VERSION 5.8 ;
BUSBITCHARS "[]" ;
DIVIDERCHAR "/" ;
UNITS
    DATABASE MICRONS 1000 ;
END UNITS

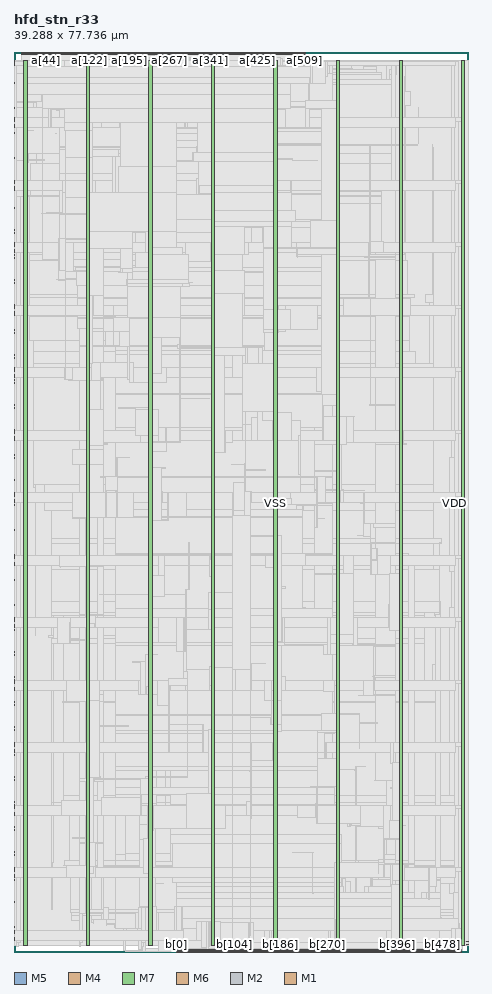
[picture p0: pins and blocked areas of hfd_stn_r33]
MACRO hfd_stn_r33
  FOREIGN hfd_stn_r33 0 0 ;
  CLASS BLOCK ;
  SIZE 39.288 BY 77.736 ;
  PIN a[0]
    DIRECTION INPUT ;
    USE SIGNAL ;
    PORT
      LAYER M5 ;
        RECT  0.624 77.544 0.648 77.736 ;
    END
  END a[0]
  PIN a[100]
    DIRECTION INPUT ;
    USE SIGNAL ;
    PORT
      LAYER M5 ;
        RECT  5.424 77.544 5.448 77.736 ;
    END
  END a[100]
  PIN a[101]
    DIRECTION INPUT ;
    USE SIGNAL ;
    PORT
      LAYER M5 ;
        RECT  5.472 77.544 5.496 77.736 ;
    END
  END a[101]
  PIN a[102]
    DIRECTION INPUT ;
    USE SIGNAL ;
    PORT
      LAYER M5 ;
        RECT  5.52 77.544 5.544 77.736 ;
    END
  END a[102]
  PIN a[103]
    DIRECTION INPUT ;
    USE SIGNAL ;
    PORT
      LAYER M5 ;
        RECT  5.568 77.544 5.592 77.736 ;
    END
  END a[103]
  PIN a[104]
    DIRECTION INPUT ;
    USE SIGNAL ;
    PORT
      LAYER M5 ;
        RECT  5.616 77.544 5.64 77.736 ;
    END
  END a[104]
  PIN a[105]
    DIRECTION INPUT ;
    USE SIGNAL ;
    PORT
      LAYER M5 ;
        RECT  5.664 77.544 5.688 77.736 ;
    END
  END a[105]
  PIN a[106]
    DIRECTION INPUT ;
    USE SIGNAL ;
    PORT
      LAYER M5 ;
        RECT  5.712 77.544 5.736 77.736 ;
    END
  END a[106]
  PIN a[107]
    DIRECTION INPUT ;
    USE SIGNAL ;
    PORT
      LAYER M5 ;
        RECT  5.76 77.544 5.784 77.736 ;
    END
  END a[107]
  PIN a[108]
    DIRECTION INPUT ;
    USE SIGNAL ;
    PORT
      LAYER M5 ;
        RECT  5.808 77.544 5.832 77.736 ;
    END
  END a[108]
  PIN a[109]
    DIRECTION INPUT ;
    USE SIGNAL ;
    PORT
      LAYER M5 ;
        RECT  5.856 77.544 5.88 77.736 ;
    END
  END a[109]
  PIN a[10]
    DIRECTION INPUT ;
    USE SIGNAL ;
    PORT
      LAYER M5 ;
        RECT  1.104 77.544 1.128 77.736 ;
    END
  END a[10]
  PIN a[110]
    DIRECTION INPUT ;
    USE SIGNAL ;
    PORT
      LAYER M5 ;
        RECT  5.904 77.544 5.928 77.736 ;
    END
  END a[110]
  PIN a[111]
    DIRECTION INPUT ;
    USE SIGNAL ;
    PORT
      LAYER M5 ;
        RECT  5.952 77.544 5.976 77.736 ;
    END
  END a[111]
  PIN a[112]
    DIRECTION INPUT ;
    USE SIGNAL ;
    PORT
      LAYER M5 ;
        RECT  6 77.544 6.024 77.736 ;
    END
  END a[112]
  PIN a[113]
    DIRECTION INPUT ;
    USE SIGNAL ;
    PORT
      LAYER M5 ;
        RECT  6.048 77.544 6.072 77.736 ;
    END
  END a[113]
  PIN a[114]
    DIRECTION INPUT ;
    USE SIGNAL ;
    PORT
      LAYER M5 ;
        RECT  6.096 77.544 6.12 77.736 ;
    END
  END a[114]
  PIN a[115]
    DIRECTION INPUT ;
    USE SIGNAL ;
    PORT
      LAYER M5 ;
        RECT  6.144 77.544 6.168 77.736 ;
    END
  END a[115]
  PIN a[116]
    DIRECTION INPUT ;
    USE SIGNAL ;
    PORT
      LAYER M5 ;
        RECT  6.192 77.544 6.216 77.736 ;
    END
  END a[116]
  PIN a[117]
    DIRECTION INPUT ;
    USE SIGNAL ;
    PORT
      LAYER M5 ;
        RECT  6.24 77.544 6.264 77.736 ;
    END
  END a[117]
  PIN a[118]
    DIRECTION INPUT ;
    USE SIGNAL ;
    PORT
      LAYER M5 ;
        RECT  6.288 77.544 6.312 77.736 ;
    END
  END a[118]
  PIN a[119]
    DIRECTION INPUT ;
    USE SIGNAL ;
    PORT
      LAYER M5 ;
        RECT  6.336 77.544 6.36 77.736 ;
    END
  END a[119]
  PIN a[11]
    DIRECTION INPUT ;
    USE SIGNAL ;
    PORT
      LAYER M5 ;
        RECT  1.152 77.544 1.176 77.736 ;
    END
  END a[11]
  PIN a[120]
    DIRECTION INPUT ;
    USE SIGNAL ;
    PORT
      LAYER M5 ;
        RECT  6.384 77.544 6.408 77.736 ;
    END
  END a[120]
  PIN a[121]
    DIRECTION INPUT ;
    USE SIGNAL ;
    PORT
      LAYER M5 ;
        RECT  6.432 77.544 6.456 77.736 ;
    END
  END a[121]
  PIN a[122]
    DIRECTION INPUT ;
    USE SIGNAL ;
    PORT
      LAYER M5 ;
        RECT  6.48 77.544 6.504 77.736 ;
    END
  END a[122]
  PIN a[123]
    DIRECTION INPUT ;
    USE SIGNAL ;
    PORT
      LAYER M5 ;
        RECT  6.528 77.544 6.552 77.736 ;
    END
  END a[123]
  PIN a[124]
    DIRECTION INPUT ;
    USE SIGNAL ;
    PORT
      LAYER M5 ;
        RECT  6.576 77.544 6.6 77.736 ;
    END
  END a[124]
  PIN a[125]
    DIRECTION INPUT ;
    USE SIGNAL ;
    PORT
      LAYER M5 ;
        RECT  6.624 77.544 6.648 77.736 ;
    END
  END a[125]
  PIN a[126]
    DIRECTION INPUT ;
    USE SIGNAL ;
    PORT
      LAYER M5 ;
        RECT  6.672 77.544 6.696 77.736 ;
    END
  END a[126]
  PIN a[127]
    DIRECTION INPUT ;
    USE SIGNAL ;
    PORT
      LAYER M5 ;
        RECT  6.72 77.544 6.744 77.736 ;
    END
  END a[127]
  PIN a[128]
    DIRECTION INPUT ;
    USE SIGNAL ;
    PORT
      LAYER M5 ;
        RECT  6.768 77.544 6.792 77.736 ;
    END
  END a[128]
  PIN a[129]
    DIRECTION INPUT ;
    USE SIGNAL ;
    PORT
      LAYER M5 ;
        RECT  6.816 77.544 6.84 77.736 ;
    END
  END a[129]
  PIN a[12]
    DIRECTION INPUT ;
    USE SIGNAL ;
    PORT
      LAYER M5 ;
        RECT  1.2 77.544 1.224 77.736 ;
    END
  END a[12]
  PIN a[130]
    DIRECTION INPUT ;
    USE SIGNAL ;
    PORT
      LAYER M5 ;
        RECT  6.864 77.544 6.888 77.736 ;
    END
  END a[130]
  PIN a[131]
    DIRECTION INPUT ;
    USE SIGNAL ;
    PORT
      LAYER M5 ;
        RECT  6.912 77.544 6.936 77.736 ;
    END
  END a[131]
  PIN a[132]
    DIRECTION INPUT ;
    USE SIGNAL ;
    PORT
      LAYER M5 ;
        RECT  6.96 77.544 6.984 77.736 ;
    END
  END a[132]
  PIN a[133]
    DIRECTION INPUT ;
    USE SIGNAL ;
    PORT
      LAYER M5 ;
        RECT  7.008 77.544 7.032 77.736 ;
    END
  END a[133]
  PIN a[134]
    DIRECTION INPUT ;
    USE SIGNAL ;
    PORT
      LAYER M5 ;
        RECT  7.056 77.544 7.08 77.736 ;
    END
  END a[134]
  PIN a[135]
    DIRECTION INPUT ;
    USE SIGNAL ;
    PORT
      LAYER M5 ;
        RECT  7.104 77.544 7.128 77.736 ;
    END
  END a[135]
  PIN a[136]
    DIRECTION INPUT ;
    USE SIGNAL ;
    PORT
      LAYER M5 ;
        RECT  7.152 77.544 7.176 77.736 ;
    END
  END a[136]
  PIN a[137]
    DIRECTION INPUT ;
    USE SIGNAL ;
    PORT
      LAYER M5 ;
        RECT  7.2 77.544 7.224 77.736 ;
    END
  END a[137]
  PIN a[138]
    DIRECTION INPUT ;
    USE SIGNAL ;
    PORT
      LAYER M5 ;
        RECT  7.248 77.544 7.272 77.736 ;
    END
  END a[138]
  PIN a[139]
    DIRECTION INPUT ;
    USE SIGNAL ;
    PORT
      LAYER M5 ;
        RECT  7.296 77.544 7.32 77.736 ;
    END
  END a[139]
  PIN a[13]
    DIRECTION INPUT ;
    USE SIGNAL ;
    PORT
      LAYER M5 ;
        RECT  1.248 77.544 1.272 77.736 ;
    END
  END a[13]
  PIN a[140]
    DIRECTION INPUT ;
    USE SIGNAL ;
    PORT
      LAYER M5 ;
        RECT  7.344 77.544 7.368 77.736 ;
    END
  END a[140]
  PIN a[141]
    DIRECTION INPUT ;
    USE SIGNAL ;
    PORT
      LAYER M5 ;
        RECT  7.392 77.544 7.416 77.736 ;
    END
  END a[141]
  PIN a[142]
    DIRECTION INPUT ;
    USE SIGNAL ;
    PORT
      LAYER M5 ;
        RECT  7.44 77.544 7.464 77.736 ;
    END
  END a[142]
  PIN a[143]
    DIRECTION INPUT ;
    USE SIGNAL ;
    PORT
      LAYER M5 ;
        RECT  7.488 77.544 7.512 77.736 ;
    END
  END a[143]
  PIN a[144]
    DIRECTION INPUT ;
    USE SIGNAL ;
    PORT
      LAYER M5 ;
        RECT  7.536 77.544 7.56 77.736 ;
    END
  END a[144]
  PIN a[145]
    DIRECTION INPUT ;
    USE SIGNAL ;
    PORT
      LAYER M5 ;
        RECT  7.584 77.544 7.608 77.736 ;
    END
  END a[145]
  PIN a[146]
    DIRECTION INPUT ;
    USE SIGNAL ;
    PORT
      LAYER M5 ;
        RECT  7.632 77.544 7.656 77.736 ;
    END
  END a[146]
  PIN a[147]
    DIRECTION INPUT ;
    USE SIGNAL ;
    PORT
      LAYER M5 ;
        RECT  7.68 77.544 7.704 77.736 ;
    END
  END a[147]
  PIN a[148]
    DIRECTION INPUT ;
    USE SIGNAL ;
    PORT
      LAYER M5 ;
        RECT  7.728 77.544 7.752 77.736 ;
    END
  END a[148]
  PIN a[149]
    DIRECTION INPUT ;
    USE SIGNAL ;
    PORT
      LAYER M5 ;
        RECT  7.776 77.544 7.8 77.736 ;
    END
  END a[149]
  PIN a[14]
    DIRECTION INPUT ;
    USE SIGNAL ;
    PORT
      LAYER M5 ;
        RECT  1.296 77.544 1.32 77.736 ;
    END
  END a[14]
  PIN a[150]
    DIRECTION INPUT ;
    USE SIGNAL ;
    PORT
      LAYER M5 ;
        RECT  7.824 77.544 7.848 77.736 ;
    END
  END a[150]
  PIN a[151]
    DIRECTION INPUT ;
    USE SIGNAL ;
    PORT
      LAYER M5 ;
        RECT  7.872 77.544 7.896 77.736 ;
    END
  END a[151]
  PIN a[152]
    DIRECTION INPUT ;
    USE SIGNAL ;
    PORT
      LAYER M5 ;
        RECT  7.92 77.544 7.944 77.736 ;
    END
  END a[152]
  PIN a[153]
    DIRECTION INPUT ;
    USE SIGNAL ;
    PORT
      LAYER M5 ;
        RECT  7.968 77.544 7.992 77.736 ;
    END
  END a[153]
  PIN a[154]
    DIRECTION INPUT ;
    USE SIGNAL ;
    PORT
      LAYER M5 ;
        RECT  8.016 77.544 8.04 77.736 ;
    END
  END a[154]
  PIN a[155]
    DIRECTION INPUT ;
    USE SIGNAL ;
    PORT
      LAYER M5 ;
        RECT  8.064 77.544 8.088 77.736 ;
    END
  END a[155]
  PIN a[156]
    DIRECTION INPUT ;
    USE SIGNAL ;
    PORT
      LAYER M5 ;
        RECT  8.112 77.544 8.136 77.736 ;
    END
  END a[156]
  PIN a[157]
    DIRECTION INPUT ;
    USE SIGNAL ;
    PORT
      LAYER M5 ;
        RECT  8.16 77.544 8.184 77.736 ;
    END
  END a[157]
  PIN a[158]
    DIRECTION INPUT ;
    USE SIGNAL ;
    PORT
      LAYER M5 ;
        RECT  8.208 77.544 8.232 77.736 ;
    END
  END a[158]
  PIN a[159]
    DIRECTION INPUT ;
    USE SIGNAL ;
    PORT
      LAYER M5 ;
        RECT  8.256 77.544 8.28 77.736 ;
    END
  END a[159]
  PIN a[15]
    DIRECTION INPUT ;
    USE SIGNAL ;
    PORT
      LAYER M5 ;
        RECT  1.344 77.544 1.368 77.736 ;
    END
  END a[15]
  PIN a[160]
    DIRECTION INPUT ;
    USE SIGNAL ;
    PORT
      LAYER M5 ;
        RECT  8.304 77.544 8.328 77.736 ;
    END
  END a[160]
  PIN a[161]
    DIRECTION INPUT ;
    USE SIGNAL ;
    PORT
      LAYER M5 ;
        RECT  8.352 77.544 8.376 77.736 ;
    END
  END a[161]
  PIN a[162]
    DIRECTION INPUT ;
    USE SIGNAL ;
    PORT
      LAYER M5 ;
        RECT  8.4 77.544 8.424 77.736 ;
    END
  END a[162]
  PIN a[163]
    DIRECTION INPUT ;
    USE SIGNAL ;
    PORT
      LAYER M5 ;
        RECT  8.448 77.544 8.472 77.736 ;
    END
  END a[163]
  PIN a[164]
    DIRECTION INPUT ;
    USE SIGNAL ;
    PORT
      LAYER M5 ;
        RECT  8.496 77.544 8.52 77.736 ;
    END
  END a[164]
  PIN a[165]
    DIRECTION INPUT ;
    USE SIGNAL ;
    PORT
      LAYER M5 ;
        RECT  8.544 77.544 8.568 77.736 ;
    END
  END a[165]
  PIN a[166]
    DIRECTION INPUT ;
    USE SIGNAL ;
    PORT
      LAYER M5 ;
        RECT  8.592 77.544 8.616 77.736 ;
    END
  END a[166]
  PIN a[167]
    DIRECTION INPUT ;
    USE SIGNAL ;
    PORT
      LAYER M5 ;
        RECT  8.64 77.544 8.664 77.736 ;
    END
  END a[167]
  PIN a[168]
    DIRECTION INPUT ;
    USE SIGNAL ;
    PORT
      LAYER M5 ;
        RECT  8.688 77.544 8.712 77.736 ;
    END
  END a[168]
  PIN a[169]
    DIRECTION INPUT ;
    USE SIGNAL ;
    PORT
      LAYER M5 ;
        RECT  8.736 77.544 8.76 77.736 ;
    END
  END a[169]
  PIN a[16]
    DIRECTION INPUT ;
    USE SIGNAL ;
    PORT
      LAYER M5 ;
        RECT  1.392 77.544 1.416 77.736 ;
    END
  END a[16]
  PIN a[170]
    DIRECTION INPUT ;
    USE SIGNAL ;
    PORT
      LAYER M5 ;
        RECT  8.784 77.544 8.808 77.736 ;
    END
  END a[170]
  PIN a[171]
    DIRECTION INPUT ;
    USE SIGNAL ;
    PORT
      LAYER M5 ;
        RECT  8.832 77.544 8.856 77.736 ;
    END
  END a[171]
  PIN a[172]
    DIRECTION INPUT ;
    USE SIGNAL ;
    PORT
      LAYER M5 ;
        RECT  8.88 77.544 8.904 77.736 ;
    END
  END a[172]
  PIN a[173]
    DIRECTION INPUT ;
    USE SIGNAL ;
    PORT
      LAYER M5 ;
        RECT  8.928 77.544 8.952 77.736 ;
    END
  END a[173]
  PIN a[174]
    DIRECTION INPUT ;
    USE SIGNAL ;
    PORT
      LAYER M5 ;
        RECT  8.976 77.544 9 77.736 ;
    END
  END a[174]
  PIN a[175]
    DIRECTION INPUT ;
    USE SIGNAL ;
    PORT
      LAYER M5 ;
        RECT  9.024 77.544 9.048 77.736 ;
    END
  END a[175]
  PIN a[176]
    DIRECTION INPUT ;
    USE SIGNAL ;
    PORT
      LAYER M5 ;
        RECT  9.072 77.544 9.096 77.736 ;
    END
  END a[176]
  PIN a[177]
    DIRECTION INPUT ;
    USE SIGNAL ;
    PORT
      LAYER M5 ;
        RECT  9.12 77.544 9.144 77.736 ;
    END
  END a[177]
  PIN a[178]
    DIRECTION INPUT ;
    USE SIGNAL ;
    PORT
      LAYER M5 ;
        RECT  9.168 77.544 9.192 77.736 ;
    END
  END a[178]
  PIN a[179]
    DIRECTION INPUT ;
    USE SIGNAL ;
    PORT
      LAYER M5 ;
        RECT  9.216 77.544 9.24 77.736 ;
    END
  END a[179]
  PIN a[17]
    DIRECTION INPUT ;
    USE SIGNAL ;
    PORT
      LAYER M5 ;
        RECT  1.44 77.544 1.464 77.736 ;
    END
  END a[17]
  PIN a[180]
    DIRECTION INPUT ;
    USE SIGNAL ;
    PORT
      LAYER M5 ;
        RECT  9.264 77.544 9.288 77.736 ;
    END
  END a[180]
  PIN a[181]
    DIRECTION INPUT ;
    USE SIGNAL ;
    PORT
      LAYER M5 ;
        RECT  9.312 77.544 9.336 77.736 ;
    END
  END a[181]
  PIN a[182]
    DIRECTION INPUT ;
    USE SIGNAL ;
    PORT
      LAYER M5 ;
        RECT  9.36 77.544 9.384 77.736 ;
    END
  END a[182]
  PIN a[183]
    DIRECTION INPUT ;
    USE SIGNAL ;
    PORT
      LAYER M5 ;
        RECT  9.408 77.544 9.432 77.736 ;
    END
  END a[183]
  PIN a[184]
    DIRECTION INPUT ;
    USE SIGNAL ;
    PORT
      LAYER M5 ;
        RECT  9.456 77.544 9.48 77.736 ;
    END
  END a[184]
  PIN a[185]
    DIRECTION INPUT ;
    USE SIGNAL ;
    PORT
      LAYER M5 ;
        RECT  9.504 77.544 9.528 77.736 ;
    END
  END a[185]
  PIN a[186]
    DIRECTION INPUT ;
    USE SIGNAL ;
    PORT
      LAYER M5 ;
        RECT  9.552 77.544 9.576 77.736 ;
    END
  END a[186]
  PIN a[187]
    DIRECTION INPUT ;
    USE SIGNAL ;
    PORT
      LAYER M5 ;
        RECT  9.6 77.544 9.624 77.736 ;
    END
  END a[187]
  PIN a[188]
    DIRECTION INPUT ;
    USE SIGNAL ;
    PORT
      LAYER M5 ;
        RECT  9.648 77.544 9.672 77.736 ;
    END
  END a[188]
  PIN a[189]
    DIRECTION INPUT ;
    USE SIGNAL ;
    PORT
      LAYER M5 ;
        RECT  9.696 77.544 9.72 77.736 ;
    END
  END a[189]
  PIN a[18]
    DIRECTION INPUT ;
    USE SIGNAL ;
    PORT
      LAYER M5 ;
        RECT  1.488 77.544 1.512 77.736 ;
    END
  END a[18]
  PIN a[190]
    DIRECTION INPUT ;
    USE SIGNAL ;
    PORT
      LAYER M5 ;
        RECT  9.744 77.544 9.768 77.736 ;
    END
  END a[190]
  PIN a[191]
    DIRECTION INPUT ;
    USE SIGNAL ;
    PORT
      LAYER M5 ;
        RECT  9.792 77.544 9.816 77.736 ;
    END
  END a[191]
  PIN a[192]
    DIRECTION INPUT ;
    USE SIGNAL ;
    PORT
      LAYER M5 ;
        RECT  9.84 77.544 9.864 77.736 ;
    END
  END a[192]
  PIN a[193]
    DIRECTION INPUT ;
    USE SIGNAL ;
    PORT
      LAYER M5 ;
        RECT  9.888 77.544 9.912 77.736 ;
    END
  END a[193]
  PIN a[194]
    DIRECTION INPUT ;
    USE SIGNAL ;
    PORT
      LAYER M5 ;
        RECT  9.936 77.544 9.96 77.736 ;
    END
  END a[194]
  PIN a[195]
    DIRECTION INPUT ;
    USE SIGNAL ;
    PORT
      LAYER M5 ;
        RECT  9.984 77.544 10.008 77.736 ;
    END
  END a[195]
  PIN a[196]
    DIRECTION INPUT ;
    USE SIGNAL ;
    PORT
      LAYER M5 ;
        RECT  10.032 77.544 10.056 77.736 ;
    END
  END a[196]
  PIN a[197]
    DIRECTION INPUT ;
    USE SIGNAL ;
    PORT
      LAYER M5 ;
        RECT  10.08 77.544 10.104 77.736 ;
    END
  END a[197]
  PIN a[198]
    DIRECTION INPUT ;
    USE SIGNAL ;
    PORT
      LAYER M5 ;
        RECT  10.128 77.544 10.152 77.736 ;
    END
  END a[198]
  PIN a[199]
    DIRECTION INPUT ;
    USE SIGNAL ;
    PORT
      LAYER M5 ;
        RECT  10.176 77.544 10.2 77.736 ;
    END
  END a[199]
  PIN a[19]
    DIRECTION INPUT ;
    USE SIGNAL ;
    PORT
      LAYER M5 ;
        RECT  1.536 77.544 1.56 77.736 ;
    END
  END a[19]
  PIN a[1]
    DIRECTION INPUT ;
    USE SIGNAL ;
    PORT
      LAYER M5 ;
        RECT  0.672 77.544 0.696 77.736 ;
    END
  END a[1]
  PIN a[200]
    DIRECTION INPUT ;
    USE SIGNAL ;
    PORT
      LAYER M5 ;
        RECT  10.224 77.544 10.248 77.736 ;
    END
  END a[200]
  PIN a[201]
    DIRECTION INPUT ;
    USE SIGNAL ;
    PORT
      LAYER M5 ;
        RECT  10.272 77.544 10.296 77.736 ;
    END
  END a[201]
  PIN a[202]
    DIRECTION INPUT ;
    USE SIGNAL ;
    PORT
      LAYER M5 ;
        RECT  10.32 77.544 10.344 77.736 ;
    END
  END a[202]
  PIN a[203]
    DIRECTION INPUT ;
    USE SIGNAL ;
    PORT
      LAYER M5 ;
        RECT  10.368 77.544 10.392 77.736 ;
    END
  END a[203]
  PIN a[204]
    DIRECTION INPUT ;
    USE SIGNAL ;
    PORT
      LAYER M5 ;
        RECT  10.416 77.544 10.44 77.736 ;
    END
  END a[204]
  PIN a[205]
    DIRECTION INPUT ;
    USE SIGNAL ;
    PORT
      LAYER M5 ;
        RECT  10.464 77.544 10.488 77.736 ;
    END
  END a[205]
  PIN a[206]
    DIRECTION INPUT ;
    USE SIGNAL ;
    PORT
      LAYER M5 ;
        RECT  10.512 77.544 10.536 77.736 ;
    END
  END a[206]
  PIN a[207]
    DIRECTION INPUT ;
    USE SIGNAL ;
    PORT
      LAYER M5 ;
        RECT  10.56 77.544 10.584 77.736 ;
    END
  END a[207]
  PIN a[208]
    DIRECTION INPUT ;
    USE SIGNAL ;
    PORT
      LAYER M5 ;
        RECT  10.608 77.544 10.632 77.736 ;
    END
  END a[208]
  PIN a[209]
    DIRECTION INPUT ;
    USE SIGNAL ;
    PORT
      LAYER M5 ;
        RECT  10.656 77.544 10.68 77.736 ;
    END
  END a[209]
  PIN a[20]
    DIRECTION INPUT ;
    USE SIGNAL ;
    PORT
      LAYER M5 ;
        RECT  1.584 77.544 1.608 77.736 ;
    END
  END a[20]
  PIN a[210]
    DIRECTION INPUT ;
    USE SIGNAL ;
    PORT
      LAYER M5 ;
        RECT  10.704 77.544 10.728 77.736 ;
    END
  END a[210]
  PIN a[211]
    DIRECTION INPUT ;
    USE SIGNAL ;
    PORT
      LAYER M5 ;
        RECT  10.752 77.544 10.776 77.736 ;
    END
  END a[211]
  PIN a[212]
    DIRECTION INPUT ;
    USE SIGNAL ;
    PORT
      LAYER M5 ;
        RECT  10.8 77.544 10.824 77.736 ;
    END
  END a[212]
  PIN a[213]
    DIRECTION INPUT ;
    USE SIGNAL ;
    PORT
      LAYER M5 ;
        RECT  10.848 77.544 10.872 77.736 ;
    END
  END a[213]
  PIN a[214]
    DIRECTION INPUT ;
    USE SIGNAL ;
    PORT
      LAYER M5 ;
        RECT  10.896 77.544 10.92 77.736 ;
    END
  END a[214]
  PIN a[215]
    DIRECTION INPUT ;
    USE SIGNAL ;
    PORT
      LAYER M5 ;
        RECT  10.944 77.544 10.968 77.736 ;
    END
  END a[215]
  PIN a[216]
    DIRECTION INPUT ;
    USE SIGNAL ;
    PORT
      LAYER M5 ;
        RECT  10.992 77.544 11.016 77.736 ;
    END
  END a[216]
  PIN a[217]
    DIRECTION INPUT ;
    USE SIGNAL ;
    PORT
      LAYER M5 ;
        RECT  11.04 77.544 11.064 77.736 ;
    END
  END a[217]
  PIN a[218]
    DIRECTION INPUT ;
    USE SIGNAL ;
    PORT
      LAYER M5 ;
        RECT  11.088 77.544 11.112 77.736 ;
    END
  END a[218]
  PIN a[219]
    DIRECTION INPUT ;
    USE SIGNAL ;
    PORT
      LAYER M5 ;
        RECT  11.136 77.544 11.16 77.736 ;
    END
  END a[219]
  PIN a[21]
    DIRECTION INPUT ;
    USE SIGNAL ;
    PORT
      LAYER M5 ;
        RECT  1.632 77.544 1.656 77.736 ;
    END
  END a[21]
  PIN a[220]
    DIRECTION INPUT ;
    USE SIGNAL ;
    PORT
      LAYER M5 ;
        RECT  11.184 77.544 11.208 77.736 ;
    END
  END a[220]
  PIN a[221]
    DIRECTION INPUT ;
    USE SIGNAL ;
    PORT
      LAYER M5 ;
        RECT  11.232 77.544 11.256 77.736 ;
    END
  END a[221]
  PIN a[222]
    DIRECTION INPUT ;
    USE SIGNAL ;
    PORT
      LAYER M5 ;
        RECT  11.28 77.544 11.304 77.736 ;
    END
  END a[222]
  PIN a[223]
    DIRECTION INPUT ;
    USE SIGNAL ;
    PORT
      LAYER M5 ;
        RECT  11.328 77.544 11.352 77.736 ;
    END
  END a[223]
  PIN a[224]
    DIRECTION INPUT ;
    USE SIGNAL ;
    PORT
      LAYER M5 ;
        RECT  11.376 77.544 11.4 77.736 ;
    END
  END a[224]
  PIN a[225]
    DIRECTION INPUT ;
    USE SIGNAL ;
    PORT
      LAYER M5 ;
        RECT  11.424 77.544 11.448 77.736 ;
    END
  END a[225]
  PIN a[226]
    DIRECTION INPUT ;
    USE SIGNAL ;
    PORT
      LAYER M5 ;
        RECT  11.472 77.544 11.496 77.736 ;
    END
  END a[226]
  PIN a[227]
    DIRECTION INPUT ;
    USE SIGNAL ;
    PORT
      LAYER M5 ;
        RECT  11.52 77.544 11.544 77.736 ;
    END
  END a[227]
  PIN a[228]
    DIRECTION INPUT ;
    USE SIGNAL ;
    PORT
      LAYER M5 ;
        RECT  11.568 77.544 11.592 77.736 ;
    END
  END a[228]
  PIN a[229]
    DIRECTION INPUT ;
    USE SIGNAL ;
    PORT
      LAYER M5 ;
        RECT  11.616 77.544 11.64 77.736 ;
    END
  END a[229]
  PIN a[22]
    DIRECTION INPUT ;
    USE SIGNAL ;
    PORT
      LAYER M5 ;
        RECT  1.68 77.544 1.704 77.736 ;
    END
  END a[22]
  PIN a[230]
    DIRECTION INPUT ;
    USE SIGNAL ;
    PORT
      LAYER M5 ;
        RECT  11.664 77.544 11.688 77.736 ;
    END
  END a[230]
  PIN a[231]
    DIRECTION INPUT ;
    USE SIGNAL ;
    PORT
      LAYER M5 ;
        RECT  11.712 77.544 11.736 77.736 ;
    END
  END a[231]
  PIN a[232]
    DIRECTION INPUT ;
    USE SIGNAL ;
    PORT
      LAYER M5 ;
        RECT  11.76 77.544 11.784 77.736 ;
    END
  END a[232]
  PIN a[233]
    DIRECTION INPUT ;
    USE SIGNAL ;
    PORT
      LAYER M5 ;
        RECT  11.808 77.544 11.832 77.736 ;
    END
  END a[233]
  PIN a[234]
    DIRECTION INPUT ;
    USE SIGNAL ;
    PORT
      LAYER M5 ;
        RECT  11.856 77.544 11.88 77.736 ;
    END
  END a[234]
  PIN a[235]
    DIRECTION INPUT ;
    USE SIGNAL ;
    PORT
      LAYER M5 ;
        RECT  11.904 77.544 11.928 77.736 ;
    END
  END a[235]
  PIN a[236]
    DIRECTION INPUT ;
    USE SIGNAL ;
    PORT
      LAYER M5 ;
        RECT  11.952 77.544 11.976 77.736 ;
    END
  END a[236]
  PIN a[237]
    DIRECTION INPUT ;
    USE SIGNAL ;
    PORT
      LAYER M5 ;
        RECT  12 77.544 12.024 77.736 ;
    END
  END a[237]
  PIN a[238]
    DIRECTION INPUT ;
    USE SIGNAL ;
    PORT
      LAYER M5 ;
        RECT  12.048 77.544 12.072 77.736 ;
    END
  END a[238]
  PIN a[239]
    DIRECTION INPUT ;
    USE SIGNAL ;
    PORT
      LAYER M5 ;
        RECT  12.096 77.544 12.12 77.736 ;
    END
  END a[239]
  PIN a[23]
    DIRECTION INPUT ;
    USE SIGNAL ;
    PORT
      LAYER M5 ;
        RECT  1.728 77.544 1.752 77.736 ;
    END
  END a[23]
  PIN a[240]
    DIRECTION INPUT ;
    USE SIGNAL ;
    PORT
      LAYER M5 ;
        RECT  12.144 77.544 12.168 77.736 ;
    END
  END a[240]
  PIN a[241]
    DIRECTION INPUT ;
    USE SIGNAL ;
    PORT
      LAYER M5 ;
        RECT  12.192 77.544 12.216 77.736 ;
    END
  END a[241]
  PIN a[242]
    DIRECTION INPUT ;
    USE SIGNAL ;
    PORT
      LAYER M5 ;
        RECT  12.24 77.544 12.264 77.736 ;
    END
  END a[242]
  PIN a[243]
    DIRECTION INPUT ;
    USE SIGNAL ;
    PORT
      LAYER M5 ;
        RECT  12.288 77.544 12.312 77.736 ;
    END
  END a[243]
  PIN a[244]
    DIRECTION INPUT ;
    USE SIGNAL ;
    PORT
      LAYER M5 ;
        RECT  12.336 77.544 12.36 77.736 ;
    END
  END a[244]
  PIN a[245]
    DIRECTION INPUT ;
    USE SIGNAL ;
    PORT
      LAYER M5 ;
        RECT  12.384 77.544 12.408 77.736 ;
    END
  END a[245]
  PIN a[246]
    DIRECTION INPUT ;
    USE SIGNAL ;
    PORT
      LAYER M5 ;
        RECT  12.432 77.544 12.456 77.736 ;
    END
  END a[246]
  PIN a[247]
    DIRECTION INPUT ;
    USE SIGNAL ;
    PORT
      LAYER M5 ;
        RECT  12.48 77.544 12.504 77.736 ;
    END
  END a[247]
  PIN a[248]
    DIRECTION INPUT ;
    USE SIGNAL ;
    PORT
      LAYER M5 ;
        RECT  12.528 77.544 12.552 77.736 ;
    END
  END a[248]
  PIN a[249]
    DIRECTION INPUT ;
    USE SIGNAL ;
    PORT
      LAYER M5 ;
        RECT  12.576 77.544 12.6 77.736 ;
    END
  END a[249]
  PIN a[24]
    DIRECTION INPUT ;
    USE SIGNAL ;
    PORT
      LAYER M5 ;
        RECT  1.776 77.544 1.8 77.736 ;
    END
  END a[24]
  PIN a[250]
    DIRECTION INPUT ;
    USE SIGNAL ;
    PORT
      LAYER M5 ;
        RECT  12.624 77.544 12.648 77.736 ;
    END
  END a[250]
  PIN a[251]
    DIRECTION INPUT ;
    USE SIGNAL ;
    PORT
      LAYER M5 ;
        RECT  12.672 77.544 12.696 77.736 ;
    END
  END a[251]
  PIN a[252]
    DIRECTION INPUT ;
    USE SIGNAL ;
    PORT
      LAYER M5 ;
        RECT  12.72 77.544 12.744 77.736 ;
    END
  END a[252]
  PIN a[253]
    DIRECTION INPUT ;
    USE SIGNAL ;
    PORT
      LAYER M5 ;
        RECT  12.768 77.544 12.792 77.736 ;
    END
  END a[253]
  PIN a[254]
    DIRECTION INPUT ;
    USE SIGNAL ;
    PORT
      LAYER M5 ;
        RECT  12.816 77.544 12.84 77.736 ;
    END
  END a[254]
  PIN a[255]
    DIRECTION INPUT ;
    USE SIGNAL ;
    PORT
      LAYER M5 ;
        RECT  12.864 77.544 12.888 77.736 ;
    END
  END a[255]
  PIN a[256]
    DIRECTION INPUT ;
    USE SIGNAL ;
    PORT
      LAYER M5 ;
        RECT  12.912 77.544 12.936 77.736 ;
    END
  END a[256]
  PIN a[257]
    DIRECTION INPUT ;
    USE SIGNAL ;
    PORT
      LAYER M5 ;
        RECT  12.96 77.544 12.984 77.736 ;
    END
  END a[257]
  PIN a[258]
    DIRECTION INPUT ;
    USE SIGNAL ;
    PORT
      LAYER M5 ;
        RECT  13.008 77.544 13.032 77.736 ;
    END
  END a[258]
  PIN a[259]
    DIRECTION INPUT ;
    USE SIGNAL ;
    PORT
      LAYER M5 ;
        RECT  13.056 77.544 13.08 77.736 ;
    END
  END a[259]
  PIN a[25]
    DIRECTION INPUT ;
    USE SIGNAL ;
    PORT
      LAYER M5 ;
        RECT  1.824 77.544 1.848 77.736 ;
    END
  END a[25]
  PIN a[260]
    DIRECTION INPUT ;
    USE SIGNAL ;
    PORT
      LAYER M5 ;
        RECT  13.104 77.544 13.128 77.736 ;
    END
  END a[260]
  PIN a[261]
    DIRECTION INPUT ;
    USE SIGNAL ;
    PORT
      LAYER M5 ;
        RECT  13.152 77.544 13.176 77.736 ;
    END
  END a[261]
  PIN a[262]
    DIRECTION INPUT ;
    USE SIGNAL ;
    PORT
      LAYER M5 ;
        RECT  13.2 77.544 13.224 77.736 ;
    END
  END a[262]
  PIN a[263]
    DIRECTION INPUT ;
    USE SIGNAL ;
    PORT
      LAYER M5 ;
        RECT  13.248 77.544 13.272 77.736 ;
    END
  END a[263]
  PIN a[264]
    DIRECTION INPUT ;
    USE SIGNAL ;
    PORT
      LAYER M5 ;
        RECT  13.296 77.544 13.32 77.736 ;
    END
  END a[264]
  PIN a[265]
    DIRECTION INPUT ;
    USE SIGNAL ;
    PORT
      LAYER M5 ;
        RECT  13.344 77.544 13.368 77.736 ;
    END
  END a[265]
  PIN a[266]
    DIRECTION INPUT ;
    USE SIGNAL ;
    PORT
      LAYER M5 ;
        RECT  13.392 77.544 13.416 77.736 ;
    END
  END a[266]
  PIN a[267]
    DIRECTION INPUT ;
    USE SIGNAL ;
    PORT
      LAYER M5 ;
        RECT  13.44 77.544 13.464 77.736 ;
    END
  END a[267]
  PIN a[268]
    DIRECTION INPUT ;
    USE SIGNAL ;
    PORT
      LAYER M5 ;
        RECT  13.488 77.544 13.512 77.736 ;
    END
  END a[268]
  PIN a[269]
    DIRECTION INPUT ;
    USE SIGNAL ;
    PORT
      LAYER M5 ;
        RECT  13.536 77.544 13.56 77.736 ;
    END
  END a[269]
  PIN a[26]
    DIRECTION INPUT ;
    USE SIGNAL ;
    PORT
      LAYER M5 ;
        RECT  1.872 77.544 1.896 77.736 ;
    END
  END a[26]
  PIN a[270]
    DIRECTION INPUT ;
    USE SIGNAL ;
    PORT
      LAYER M5 ;
        RECT  13.584 77.544 13.608 77.736 ;
    END
  END a[270]
  PIN a[271]
    DIRECTION INPUT ;
    USE SIGNAL ;
    PORT
      LAYER M5 ;
        RECT  13.632 77.544 13.656 77.736 ;
    END
  END a[271]
  PIN a[272]
    DIRECTION INPUT ;
    USE SIGNAL ;
    PORT
      LAYER M5 ;
        RECT  13.68 77.544 13.704 77.736 ;
    END
  END a[272]
  PIN a[273]
    DIRECTION INPUT ;
    USE SIGNAL ;
    PORT
      LAYER M5 ;
        RECT  13.728 77.544 13.752 77.736 ;
    END
  END a[273]
  PIN a[274]
    DIRECTION INPUT ;
    USE SIGNAL ;
    PORT
      LAYER M5 ;
        RECT  13.776 77.544 13.8 77.736 ;
    END
  END a[274]
  PIN a[275]
    DIRECTION INPUT ;
    USE SIGNAL ;
    PORT
      LAYER M5 ;
        RECT  13.824 77.544 13.848 77.736 ;
    END
  END a[275]
  PIN a[276]
    DIRECTION INPUT ;
    USE SIGNAL ;
    PORT
      LAYER M5 ;
        RECT  13.872 77.544 13.896 77.736 ;
    END
  END a[276]
  PIN a[277]
    DIRECTION INPUT ;
    USE SIGNAL ;
    PORT
      LAYER M5 ;
        RECT  13.92 77.544 13.944 77.736 ;
    END
  END a[277]
  PIN a[278]
    DIRECTION INPUT ;
    USE SIGNAL ;
    PORT
      LAYER M5 ;
        RECT  13.968 77.544 13.992 77.736 ;
    END
  END a[278]
  PIN a[279]
    DIRECTION INPUT ;
    USE SIGNAL ;
    PORT
      LAYER M5 ;
        RECT  14.016 77.544 14.04 77.736 ;
    END
  END a[279]
  PIN a[27]
    DIRECTION INPUT ;
    USE SIGNAL ;
    PORT
      LAYER M5 ;
        RECT  1.92 77.544 1.944 77.736 ;
    END
  END a[27]
  PIN a[280]
    DIRECTION INPUT ;
    USE SIGNAL ;
    PORT
      LAYER M5 ;
        RECT  14.064 77.544 14.088 77.736 ;
    END
  END a[280]
  PIN a[281]
    DIRECTION INPUT ;
    USE SIGNAL ;
    PORT
      LAYER M5 ;
        RECT  14.112 77.544 14.136 77.736 ;
    END
  END a[281]
  PIN a[282]
    DIRECTION INPUT ;
    USE SIGNAL ;
    PORT
      LAYER M5 ;
        RECT  14.16 77.544 14.184 77.736 ;
    END
  END a[282]
  PIN a[283]
    DIRECTION INPUT ;
    USE SIGNAL ;
    PORT
      LAYER M5 ;
        RECT  14.208 77.544 14.232 77.736 ;
    END
  END a[283]
  PIN a[284]
    DIRECTION INPUT ;
    USE SIGNAL ;
    PORT
      LAYER M5 ;
        RECT  14.256 77.544 14.28 77.736 ;
    END
  END a[284]
  PIN a[285]
    DIRECTION INPUT ;
    USE SIGNAL ;
    PORT
      LAYER M5 ;
        RECT  14.304 77.544 14.328 77.736 ;
    END
  END a[285]
  PIN a[286]
    DIRECTION INPUT ;
    USE SIGNAL ;
    PORT
      LAYER M5 ;
        RECT  14.352 77.544 14.376 77.736 ;
    END
  END a[286]
  PIN a[287]
    DIRECTION INPUT ;
    USE SIGNAL ;
    PORT
      LAYER M5 ;
        RECT  14.4 77.544 14.424 77.736 ;
    END
  END a[287]
  PIN a[288]
    DIRECTION INPUT ;
    USE SIGNAL ;
    PORT
      LAYER M5 ;
        RECT  14.448 77.544 14.472 77.736 ;
    END
  END a[288]
  PIN a[289]
    DIRECTION INPUT ;
    USE SIGNAL ;
    PORT
      LAYER M5 ;
        RECT  14.496 77.544 14.52 77.736 ;
    END
  END a[289]
  PIN a[28]
    DIRECTION INPUT ;
    USE SIGNAL ;
    PORT
      LAYER M5 ;
        RECT  1.968 77.544 1.992 77.736 ;
    END
  END a[28]
  PIN a[290]
    DIRECTION INPUT ;
    USE SIGNAL ;
    PORT
      LAYER M5 ;
        RECT  14.544 77.544 14.568 77.736 ;
    END
  END a[290]
  PIN a[291]
    DIRECTION INPUT ;
    USE SIGNAL ;
    PORT
      LAYER M5 ;
        RECT  14.592 77.544 14.616 77.736 ;
    END
  END a[291]
  PIN a[292]
    DIRECTION INPUT ;
    USE SIGNAL ;
    PORT
      LAYER M5 ;
        RECT  14.64 77.544 14.664 77.736 ;
    END
  END a[292]
  PIN a[293]
    DIRECTION INPUT ;
    USE SIGNAL ;
    PORT
      LAYER M5 ;
        RECT  14.688 77.544 14.712 77.736 ;
    END
  END a[293]
  PIN a[294]
    DIRECTION INPUT ;
    USE SIGNAL ;
    PORT
      LAYER M5 ;
        RECT  14.736 77.544 14.76 77.736 ;
    END
  END a[294]
  PIN a[295]
    DIRECTION INPUT ;
    USE SIGNAL ;
    PORT
      LAYER M5 ;
        RECT  14.784 77.544 14.808 77.736 ;
    END
  END a[295]
  PIN a[296]
    DIRECTION INPUT ;
    USE SIGNAL ;
    PORT
      LAYER M5 ;
        RECT  14.832 77.544 14.856 77.736 ;
    END
  END a[296]
  PIN a[297]
    DIRECTION INPUT ;
    USE SIGNAL ;
    PORT
      LAYER M5 ;
        RECT  14.88 77.544 14.904 77.736 ;
    END
  END a[297]
  PIN a[298]
    DIRECTION INPUT ;
    USE SIGNAL ;
    PORT
      LAYER M5 ;
        RECT  14.928 77.544 14.952 77.736 ;
    END
  END a[298]
  PIN a[299]
    DIRECTION INPUT ;
    USE SIGNAL ;
    PORT
      LAYER M5 ;
        RECT  14.976 77.544 15 77.736 ;
    END
  END a[299]
  PIN a[29]
    DIRECTION INPUT ;
    USE SIGNAL ;
    PORT
      LAYER M5 ;
        RECT  2.016 77.544 2.04 77.736 ;
    END
  END a[29]
  PIN a[2]
    DIRECTION INPUT ;
    USE SIGNAL ;
    PORT
      LAYER M5 ;
        RECT  0.72 77.544 0.744 77.736 ;
    END
  END a[2]
  PIN a[300]
    DIRECTION INPUT ;
    USE SIGNAL ;
    PORT
      LAYER M5 ;
        RECT  15.024 77.544 15.048 77.736 ;
    END
  END a[300]
  PIN a[301]
    DIRECTION INPUT ;
    USE SIGNAL ;
    PORT
      LAYER M5 ;
        RECT  15.072 77.544 15.096 77.736 ;
    END
  END a[301]
  PIN a[302]
    DIRECTION INPUT ;
    USE SIGNAL ;
    PORT
      LAYER M5 ;
        RECT  15.12 77.544 15.144 77.736 ;
    END
  END a[302]
  PIN a[303]
    DIRECTION INPUT ;
    USE SIGNAL ;
    PORT
      LAYER M5 ;
        RECT  15.168 77.544 15.192 77.736 ;
    END
  END a[303]
  PIN a[304]
    DIRECTION INPUT ;
    USE SIGNAL ;
    PORT
      LAYER M5 ;
        RECT  15.216 77.544 15.24 77.736 ;
    END
  END a[304]
  PIN a[305]
    DIRECTION INPUT ;
    USE SIGNAL ;
    PORT
      LAYER M5 ;
        RECT  15.264 77.544 15.288 77.736 ;
    END
  END a[305]
  PIN a[306]
    DIRECTION INPUT ;
    USE SIGNAL ;
    PORT
      LAYER M5 ;
        RECT  15.312 77.544 15.336 77.736 ;
    END
  END a[306]
  PIN a[307]
    DIRECTION INPUT ;
    USE SIGNAL ;
    PORT
      LAYER M5 ;
        RECT  15.36 77.544 15.384 77.736 ;
    END
  END a[307]
  PIN a[308]
    DIRECTION INPUT ;
    USE SIGNAL ;
    PORT
      LAYER M5 ;
        RECT  15.408 77.544 15.432 77.736 ;
    END
  END a[308]
  PIN a[309]
    DIRECTION INPUT ;
    USE SIGNAL ;
    PORT
      LAYER M5 ;
        RECT  15.456 77.544 15.48 77.736 ;
    END
  END a[309]
  PIN a[30]
    DIRECTION INPUT ;
    USE SIGNAL ;
    PORT
      LAYER M5 ;
        RECT  2.064 77.544 2.088 77.736 ;
    END
  END a[30]
  PIN a[310]
    DIRECTION INPUT ;
    USE SIGNAL ;
    PORT
      LAYER M5 ;
        RECT  15.504 77.544 15.528 77.736 ;
    END
  END a[310]
  PIN a[311]
    DIRECTION INPUT ;
    USE SIGNAL ;
    PORT
      LAYER M5 ;
        RECT  15.552 77.544 15.576 77.736 ;
    END
  END a[311]
  PIN a[312]
    DIRECTION INPUT ;
    USE SIGNAL ;
    PORT
      LAYER M5 ;
        RECT  15.6 77.544 15.624 77.736 ;
    END
  END a[312]
  PIN a[313]
    DIRECTION INPUT ;
    USE SIGNAL ;
    PORT
      LAYER M5 ;
        RECT  15.648 77.544 15.672 77.736 ;
    END
  END a[313]
  PIN a[314]
    DIRECTION INPUT ;
    USE SIGNAL ;
    PORT
      LAYER M5 ;
        RECT  15.696 77.544 15.72 77.736 ;
    END
  END a[314]
  PIN a[315]
    DIRECTION INPUT ;
    USE SIGNAL ;
    PORT
      LAYER M5 ;
        RECT  15.744 77.544 15.768 77.736 ;
    END
  END a[315]
  PIN a[316]
    DIRECTION INPUT ;
    USE SIGNAL ;
    PORT
      LAYER M5 ;
        RECT  15.792 77.544 15.816 77.736 ;
    END
  END a[316]
  PIN a[317]
    DIRECTION INPUT ;
    USE SIGNAL ;
    PORT
      LAYER M5 ;
        RECT  15.84 77.544 15.864 77.736 ;
    END
  END a[317]
  PIN a[318]
    DIRECTION INPUT ;
    USE SIGNAL ;
    PORT
      LAYER M5 ;
        RECT  15.888 77.544 15.912 77.736 ;
    END
  END a[318]
  PIN a[319]
    DIRECTION INPUT ;
    USE SIGNAL ;
    PORT
      LAYER M5 ;
        RECT  15.936 77.544 15.96 77.736 ;
    END
  END a[319]
  PIN a[31]
    DIRECTION INPUT ;
    USE SIGNAL ;
    PORT
      LAYER M5 ;
        RECT  2.112 77.544 2.136 77.736 ;
    END
  END a[31]
  PIN a[320]
    DIRECTION INPUT ;
    USE SIGNAL ;
    PORT
      LAYER M5 ;
        RECT  15.984 77.544 16.008 77.736 ;
    END
  END a[320]
  PIN a[321]
    DIRECTION INPUT ;
    USE SIGNAL ;
    PORT
      LAYER M5 ;
        RECT  16.032 77.544 16.056 77.736 ;
    END
  END a[321]
  PIN a[322]
    DIRECTION INPUT ;
    USE SIGNAL ;
    PORT
      LAYER M5 ;
        RECT  16.08 77.544 16.104 77.736 ;
    END
  END a[322]
  PIN a[323]
    DIRECTION INPUT ;
    USE SIGNAL ;
    PORT
      LAYER M5 ;
        RECT  16.128 77.544 16.152 77.736 ;
    END
  END a[323]
  PIN a[324]
    DIRECTION INPUT ;
    USE SIGNAL ;
    PORT
      LAYER M5 ;
        RECT  16.176 77.544 16.2 77.736 ;
    END
  END a[324]
  PIN a[325]
    DIRECTION INPUT ;
    USE SIGNAL ;
    PORT
      LAYER M5 ;
        RECT  16.224 77.544 16.248 77.736 ;
    END
  END a[325]
  PIN a[326]
    DIRECTION INPUT ;
    USE SIGNAL ;
    PORT
      LAYER M5 ;
        RECT  16.272 77.544 16.296 77.736 ;
    END
  END a[326]
  PIN a[327]
    DIRECTION INPUT ;
    USE SIGNAL ;
    PORT
      LAYER M5 ;
        RECT  16.32 77.544 16.344 77.736 ;
    END
  END a[327]
  PIN a[328]
    DIRECTION INPUT ;
    USE SIGNAL ;
    PORT
      LAYER M5 ;
        RECT  16.368 77.544 16.392 77.736 ;
    END
  END a[328]
  PIN a[329]
    DIRECTION INPUT ;
    USE SIGNAL ;
    PORT
      LAYER M5 ;
        RECT  16.416 77.544 16.44 77.736 ;
    END
  END a[329]
  PIN a[32]
    DIRECTION INPUT ;
    USE SIGNAL ;
    PORT
      LAYER M5 ;
        RECT  2.16 77.544 2.184 77.736 ;
    END
  END a[32]
  PIN a[330]
    DIRECTION INPUT ;
    USE SIGNAL ;
    PORT
      LAYER M5 ;
        RECT  16.464 77.544 16.488 77.736 ;
    END
  END a[330]
  PIN a[331]
    DIRECTION INPUT ;
    USE SIGNAL ;
    PORT
      LAYER M5 ;
        RECT  16.512 77.544 16.536 77.736 ;
    END
  END a[331]
  PIN a[332]
    DIRECTION INPUT ;
    USE SIGNAL ;
    PORT
      LAYER M5 ;
        RECT  16.56 77.544 16.584 77.736 ;
    END
  END a[332]
  PIN a[333]
    DIRECTION INPUT ;
    USE SIGNAL ;
    PORT
      LAYER M5 ;
        RECT  16.608 77.544 16.632 77.736 ;
    END
  END a[333]
  PIN a[334]
    DIRECTION INPUT ;
    USE SIGNAL ;
    PORT
      LAYER M5 ;
        RECT  16.656 77.544 16.68 77.736 ;
    END
  END a[334]
  PIN a[335]
    DIRECTION INPUT ;
    USE SIGNAL ;
    PORT
      LAYER M5 ;
        RECT  16.704 77.544 16.728 77.736 ;
    END
  END a[335]
  PIN a[336]
    DIRECTION INPUT ;
    USE SIGNAL ;
    PORT
      LAYER M5 ;
        RECT  16.752 77.544 16.776 77.736 ;
    END
  END a[336]
  PIN a[337]
    DIRECTION INPUT ;
    USE SIGNAL ;
    PORT
      LAYER M5 ;
        RECT  16.8 77.544 16.824 77.736 ;
    END
  END a[337]
  PIN a[338]
    DIRECTION INPUT ;
    USE SIGNAL ;
    PORT
      LAYER M5 ;
        RECT  16.848 77.544 16.872 77.736 ;
    END
  END a[338]
  PIN a[339]
    DIRECTION INPUT ;
    USE SIGNAL ;
    PORT
      LAYER M5 ;
        RECT  16.896 77.544 16.92 77.736 ;
    END
  END a[339]
  PIN a[33]
    DIRECTION INPUT ;
    USE SIGNAL ;
    PORT
      LAYER M5 ;
        RECT  2.208 77.544 2.232 77.736 ;
    END
  END a[33]
  PIN a[340]
    DIRECTION INPUT ;
    USE SIGNAL ;
    PORT
      LAYER M5 ;
        RECT  16.944 77.544 16.968 77.736 ;
    END
  END a[340]
  PIN a[341]
    DIRECTION INPUT ;
    USE SIGNAL ;
    PORT
      LAYER M5 ;
        RECT  16.992 77.544 17.016 77.736 ;
    END
  END a[341]
  PIN a[342]
    DIRECTION INPUT ;
    USE SIGNAL ;
    PORT
      LAYER M5 ;
        RECT  17.04 77.544 17.064 77.736 ;
    END
  END a[342]
  PIN a[343]
    DIRECTION INPUT ;
    USE SIGNAL ;
    PORT
      LAYER M5 ;
        RECT  17.088 77.544 17.112 77.736 ;
    END
  END a[343]
  PIN a[344]
    DIRECTION INPUT ;
    USE SIGNAL ;
    PORT
      LAYER M5 ;
        RECT  17.136 77.544 17.16 77.736 ;
    END
  END a[344]
  PIN a[345]
    DIRECTION INPUT ;
    USE SIGNAL ;
    PORT
      LAYER M5 ;
        RECT  17.184 77.544 17.208 77.736 ;
    END
  END a[345]
  PIN a[346]
    DIRECTION INPUT ;
    USE SIGNAL ;
    PORT
      LAYER M5 ;
        RECT  17.232 77.544 17.256 77.736 ;
    END
  END a[346]
  PIN a[347]
    DIRECTION INPUT ;
    USE SIGNAL ;
    PORT
      LAYER M5 ;
        RECT  17.28 77.544 17.304 77.736 ;
    END
  END a[347]
  PIN a[348]
    DIRECTION INPUT ;
    USE SIGNAL ;
    PORT
      LAYER M5 ;
        RECT  17.328 77.544 17.352 77.736 ;
    END
  END a[348]
  PIN a[349]
    DIRECTION INPUT ;
    USE SIGNAL ;
    PORT
      LAYER M5 ;
        RECT  17.376 77.544 17.4 77.736 ;
    END
  END a[349]
  PIN a[34]
    DIRECTION INPUT ;
    USE SIGNAL ;
    PORT
      LAYER M5 ;
        RECT  2.256 77.544 2.28 77.736 ;
    END
  END a[34]
  PIN a[350]
    DIRECTION INPUT ;
    USE SIGNAL ;
    PORT
      LAYER M5 ;
        RECT  17.424 77.544 17.448 77.736 ;
    END
  END a[350]
  PIN a[351]
    DIRECTION INPUT ;
    USE SIGNAL ;
    PORT
      LAYER M5 ;
        RECT  17.472 77.544 17.496 77.736 ;
    END
  END a[351]
  PIN a[352]
    DIRECTION INPUT ;
    USE SIGNAL ;
    PORT
      LAYER M5 ;
        RECT  17.52 77.544 17.544 77.736 ;
    END
  END a[352]
  PIN a[353]
    DIRECTION INPUT ;
    USE SIGNAL ;
    PORT
      LAYER M5 ;
        RECT  17.568 77.544 17.592 77.736 ;
    END
  END a[353]
  PIN a[354]
    DIRECTION INPUT ;
    USE SIGNAL ;
    PORT
      LAYER M5 ;
        RECT  17.616 77.544 17.64 77.736 ;
    END
  END a[354]
  PIN a[355]
    DIRECTION INPUT ;
    USE SIGNAL ;
    PORT
      LAYER M5 ;
        RECT  17.664 77.544 17.688 77.736 ;
    END
  END a[355]
  PIN a[356]
    DIRECTION INPUT ;
    USE SIGNAL ;
    PORT
      LAYER M5 ;
        RECT  17.712 77.544 17.736 77.736 ;
    END
  END a[356]
  PIN a[357]
    DIRECTION INPUT ;
    USE SIGNAL ;
    PORT
      LAYER M5 ;
        RECT  17.76 77.544 17.784 77.736 ;
    END
  END a[357]
  PIN a[358]
    DIRECTION INPUT ;
    USE SIGNAL ;
    PORT
      LAYER M5 ;
        RECT  17.808 77.544 17.832 77.736 ;
    END
  END a[358]
  PIN a[359]
    DIRECTION INPUT ;
    USE SIGNAL ;
    PORT
      LAYER M5 ;
        RECT  17.856 77.544 17.88 77.736 ;
    END
  END a[359]
  PIN a[35]
    DIRECTION INPUT ;
    USE SIGNAL ;
    PORT
      LAYER M5 ;
        RECT  2.304 77.544 2.328 77.736 ;
    END
  END a[35]
  PIN a[360]
    DIRECTION INPUT ;
    USE SIGNAL ;
    PORT
      LAYER M5 ;
        RECT  17.904 77.544 17.928 77.736 ;
    END
  END a[360]
  PIN a[361]
    DIRECTION INPUT ;
    USE SIGNAL ;
    PORT
      LAYER M5 ;
        RECT  17.952 77.544 17.976 77.736 ;
    END
  END a[361]
  PIN a[362]
    DIRECTION INPUT ;
    USE SIGNAL ;
    PORT
      LAYER M5 ;
        RECT  18 77.544 18.024 77.736 ;
    END
  END a[362]
  PIN a[363]
    DIRECTION INPUT ;
    USE SIGNAL ;
    PORT
      LAYER M5 ;
        RECT  18.048 77.544 18.072 77.736 ;
    END
  END a[363]
  PIN a[364]
    DIRECTION INPUT ;
    USE SIGNAL ;
    PORT
      LAYER M5 ;
        RECT  18.096 77.544 18.12 77.736 ;
    END
  END a[364]
  PIN a[365]
    DIRECTION INPUT ;
    USE SIGNAL ;
    PORT
      LAYER M5 ;
        RECT  18.144 77.544 18.168 77.736 ;
    END
  END a[365]
  PIN a[366]
    DIRECTION INPUT ;
    USE SIGNAL ;
    PORT
      LAYER M5 ;
        RECT  18.192 77.544 18.216 77.736 ;
    END
  END a[366]
  PIN a[367]
    DIRECTION INPUT ;
    USE SIGNAL ;
    PORT
      LAYER M5 ;
        RECT  18.24 77.544 18.264 77.736 ;
    END
  END a[367]
  PIN a[368]
    DIRECTION INPUT ;
    USE SIGNAL ;
    PORT
      LAYER M5 ;
        RECT  18.288 77.544 18.312 77.736 ;
    END
  END a[368]
  PIN a[369]
    DIRECTION INPUT ;
    USE SIGNAL ;
    PORT
      LAYER M5 ;
        RECT  18.336 77.544 18.36 77.736 ;
    END
  END a[369]
  PIN a[36]
    DIRECTION INPUT ;
    USE SIGNAL ;
    PORT
      LAYER M5 ;
        RECT  2.352 77.544 2.376 77.736 ;
    END
  END a[36]
  PIN a[370]
    DIRECTION INPUT ;
    USE SIGNAL ;
    PORT
      LAYER M5 ;
        RECT  18.384 77.544 18.408 77.736 ;
    END
  END a[370]
  PIN a[371]
    DIRECTION INPUT ;
    USE SIGNAL ;
    PORT
      LAYER M5 ;
        RECT  18.432 77.544 18.456 77.736 ;
    END
  END a[371]
  PIN a[372]
    DIRECTION INPUT ;
    USE SIGNAL ;
    PORT
      LAYER M5 ;
        RECT  18.48 77.544 18.504 77.736 ;
    END
  END a[372]
  PIN a[373]
    DIRECTION INPUT ;
    USE SIGNAL ;
    PORT
      LAYER M5 ;
        RECT  18.528 77.544 18.552 77.736 ;
    END
  END a[373]
  PIN a[374]
    DIRECTION INPUT ;
    USE SIGNAL ;
    PORT
      LAYER M5 ;
        RECT  18.576 77.544 18.6 77.736 ;
    END
  END a[374]
  PIN a[375]
    DIRECTION INPUT ;
    USE SIGNAL ;
    PORT
      LAYER M5 ;
        RECT  18.624 77.544 18.648 77.736 ;
    END
  END a[375]
  PIN a[376]
    DIRECTION INPUT ;
    USE SIGNAL ;
    PORT
      LAYER M5 ;
        RECT  18.672 77.544 18.696 77.736 ;
    END
  END a[376]
  PIN a[377]
    DIRECTION INPUT ;
    USE SIGNAL ;
    PORT
      LAYER M5 ;
        RECT  18.72 77.544 18.744 77.736 ;
    END
  END a[377]
  PIN a[378]
    DIRECTION INPUT ;
    USE SIGNAL ;
    PORT
      LAYER M5 ;
        RECT  18.768 77.544 18.792 77.736 ;
    END
  END a[378]
  PIN a[379]
    DIRECTION INPUT ;
    USE SIGNAL ;
    PORT
      LAYER M5 ;
        RECT  18.816 77.544 18.84 77.736 ;
    END
  END a[379]
  PIN a[37]
    DIRECTION INPUT ;
    USE SIGNAL ;
    PORT
      LAYER M5 ;
        RECT  2.4 77.544 2.424 77.736 ;
    END
  END a[37]
  PIN a[380]
    DIRECTION INPUT ;
    USE SIGNAL ;
    PORT
      LAYER M5 ;
        RECT  18.864 77.544 18.888 77.736 ;
    END
  END a[380]
  PIN a[381]
    DIRECTION INPUT ;
    USE SIGNAL ;
    PORT
      LAYER M5 ;
        RECT  18.912 77.544 18.936 77.736 ;
    END
  END a[381]
  PIN a[382]
    DIRECTION INPUT ;
    USE SIGNAL ;
    PORT
      LAYER M5 ;
        RECT  18.96 77.544 18.984 77.736 ;
    END
  END a[382]
  PIN a[383]
    DIRECTION INPUT ;
    USE SIGNAL ;
    PORT
      LAYER M5 ;
        RECT  19.008 77.544 19.032 77.736 ;
    END
  END a[383]
  PIN a[384]
    DIRECTION INPUT ;
    USE SIGNAL ;
    PORT
      LAYER M5 ;
        RECT  19.056 77.544 19.08 77.736 ;
    END
  END a[384]
  PIN a[385]
    DIRECTION INPUT ;
    USE SIGNAL ;
    PORT
      LAYER M5 ;
        RECT  19.104 77.544 19.128 77.736 ;
    END
  END a[385]
  PIN a[386]
    DIRECTION INPUT ;
    USE SIGNAL ;
    PORT
      LAYER M5 ;
        RECT  19.152 77.544 19.176 77.736 ;
    END
  END a[386]
  PIN a[387]
    DIRECTION INPUT ;
    USE SIGNAL ;
    PORT
      LAYER M5 ;
        RECT  19.2 77.544 19.224 77.736 ;
    END
  END a[387]
  PIN a[388]
    DIRECTION INPUT ;
    USE SIGNAL ;
    PORT
      LAYER M5 ;
        RECT  19.248 77.544 19.272 77.736 ;
    END
  END a[388]
  PIN a[389]
    DIRECTION INPUT ;
    USE SIGNAL ;
    PORT
      LAYER M5 ;
        RECT  19.296 77.544 19.32 77.736 ;
    END
  END a[389]
  PIN a[38]
    DIRECTION INPUT ;
    USE SIGNAL ;
    PORT
      LAYER M5 ;
        RECT  2.448 77.544 2.472 77.736 ;
    END
  END a[38]
  PIN a[390]
    DIRECTION INPUT ;
    USE SIGNAL ;
    PORT
      LAYER M5 ;
        RECT  19.344 77.544 19.368 77.736 ;
    END
  END a[390]
  PIN a[391]
    DIRECTION INPUT ;
    USE SIGNAL ;
    PORT
      LAYER M5 ;
        RECT  19.392 77.544 19.416 77.736 ;
    END
  END a[391]
  PIN a[392]
    DIRECTION INPUT ;
    USE SIGNAL ;
    PORT
      LAYER M5 ;
        RECT  19.44 77.544 19.464 77.736 ;
    END
  END a[392]
  PIN a[393]
    DIRECTION INPUT ;
    USE SIGNAL ;
    PORT
      LAYER M5 ;
        RECT  19.488 77.544 19.512 77.736 ;
    END
  END a[393]
  PIN a[394]
    DIRECTION INPUT ;
    USE SIGNAL ;
    PORT
      LAYER M5 ;
        RECT  19.536 77.544 19.56 77.736 ;
    END
  END a[394]
  PIN a[395]
    DIRECTION INPUT ;
    USE SIGNAL ;
    PORT
      LAYER M5 ;
        RECT  19.584 77.544 19.608 77.736 ;
    END
  END a[395]
  PIN a[396]
    DIRECTION INPUT ;
    USE SIGNAL ;
    PORT
      LAYER M5 ;
        RECT  19.632 77.544 19.656 77.736 ;
    END
  END a[396]
  PIN a[397]
    DIRECTION INPUT ;
    USE SIGNAL ;
    PORT
      LAYER M5 ;
        RECT  19.68 77.544 19.704 77.736 ;
    END
  END a[397]
  PIN a[398]
    DIRECTION INPUT ;
    USE SIGNAL ;
    PORT
      LAYER M5 ;
        RECT  19.728 77.544 19.752 77.736 ;
    END
  END a[398]
  PIN a[399]
    DIRECTION INPUT ;
    USE SIGNAL ;
    PORT
      LAYER M5 ;
        RECT  19.776 77.544 19.8 77.736 ;
    END
  END a[399]
  PIN a[39]
    DIRECTION INPUT ;
    USE SIGNAL ;
    PORT
      LAYER M5 ;
        RECT  2.496 77.544 2.52 77.736 ;
    END
  END a[39]
  PIN a[3]
    DIRECTION INPUT ;
    USE SIGNAL ;
    PORT
      LAYER M5 ;
        RECT  0.768 77.544 0.792 77.736 ;
    END
  END a[3]
  PIN a[400]
    DIRECTION INPUT ;
    USE SIGNAL ;
    PORT
      LAYER M5 ;
        RECT  19.824 77.544 19.848 77.736 ;
    END
  END a[400]
  PIN a[401]
    DIRECTION INPUT ;
    USE SIGNAL ;
    PORT
      LAYER M5 ;
        RECT  19.872 77.544 19.896 77.736 ;
    END
  END a[401]
  PIN a[402]
    DIRECTION INPUT ;
    USE SIGNAL ;
    PORT
      LAYER M5 ;
        RECT  19.92 77.544 19.944 77.736 ;
    END
  END a[402]
  PIN a[403]
    DIRECTION INPUT ;
    USE SIGNAL ;
    PORT
      LAYER M5 ;
        RECT  19.968 77.544 19.992 77.736 ;
    END
  END a[403]
  PIN a[404]
    DIRECTION INPUT ;
    USE SIGNAL ;
    PORT
      LAYER M5 ;
        RECT  20.016 77.544 20.04 77.736 ;
    END
  END a[404]
  PIN a[405]
    DIRECTION INPUT ;
    USE SIGNAL ;
    PORT
      LAYER M5 ;
        RECT  20.064 77.544 20.088 77.736 ;
    END
  END a[405]
  PIN a[406]
    DIRECTION INPUT ;
    USE SIGNAL ;
    PORT
      LAYER M5 ;
        RECT  20.112 77.544 20.136 77.736 ;
    END
  END a[406]
  PIN a[407]
    DIRECTION INPUT ;
    USE SIGNAL ;
    PORT
      LAYER M5 ;
        RECT  20.16 77.544 20.184 77.736 ;
    END
  END a[407]
  PIN a[408]
    DIRECTION INPUT ;
    USE SIGNAL ;
    PORT
      LAYER M5 ;
        RECT  20.208 77.544 20.232 77.736 ;
    END
  END a[408]
  PIN a[409]
    DIRECTION INPUT ;
    USE SIGNAL ;
    PORT
      LAYER M5 ;
        RECT  20.256 77.544 20.28 77.736 ;
    END
  END a[409]
  PIN a[40]
    DIRECTION INPUT ;
    USE SIGNAL ;
    PORT
      LAYER M5 ;
        RECT  2.544 77.544 2.568 77.736 ;
    END
  END a[40]
  PIN a[410]
    DIRECTION INPUT ;
    USE SIGNAL ;
    PORT
      LAYER M5 ;
        RECT  20.304 77.544 20.328 77.736 ;
    END
  END a[410]
  PIN a[411]
    DIRECTION INPUT ;
    USE SIGNAL ;
    PORT
      LAYER M5 ;
        RECT  20.352 77.544 20.376 77.736 ;
    END
  END a[411]
  PIN a[412]
    DIRECTION INPUT ;
    USE SIGNAL ;
    PORT
      LAYER M5 ;
        RECT  20.4 77.544 20.424 77.736 ;
    END
  END a[412]
  PIN a[413]
    DIRECTION INPUT ;
    USE SIGNAL ;
    PORT
      LAYER M5 ;
        RECT  20.448 77.544 20.472 77.736 ;
    END
  END a[413]
  PIN a[414]
    DIRECTION INPUT ;
    USE SIGNAL ;
    PORT
      LAYER M5 ;
        RECT  20.496 77.544 20.52 77.736 ;
    END
  END a[414]
  PIN a[415]
    DIRECTION INPUT ;
    USE SIGNAL ;
    PORT
      LAYER M5 ;
        RECT  20.544 77.544 20.568 77.736 ;
    END
  END a[415]
  PIN a[416]
    DIRECTION INPUT ;
    USE SIGNAL ;
    PORT
      LAYER M5 ;
        RECT  20.592 77.544 20.616 77.736 ;
    END
  END a[416]
  PIN a[417]
    DIRECTION INPUT ;
    USE SIGNAL ;
    PORT
      LAYER M5 ;
        RECT  20.64 77.544 20.664 77.736 ;
    END
  END a[417]
  PIN a[418]
    DIRECTION INPUT ;
    USE SIGNAL ;
    PORT
      LAYER M5 ;
        RECT  20.688 77.544 20.712 77.736 ;
    END
  END a[418]
  PIN a[419]
    DIRECTION INPUT ;
    USE SIGNAL ;
    PORT
      LAYER M5 ;
        RECT  20.736 77.544 20.76 77.736 ;
    END
  END a[419]
  PIN a[41]
    DIRECTION INPUT ;
    USE SIGNAL ;
    PORT
      LAYER M5 ;
        RECT  2.592 77.544 2.616 77.736 ;
    END
  END a[41]
  PIN a[420]
    DIRECTION INPUT ;
    USE SIGNAL ;
    PORT
      LAYER M5 ;
        RECT  20.784 77.544 20.808 77.736 ;
    END
  END a[420]
  PIN a[421]
    DIRECTION INPUT ;
    USE SIGNAL ;
    PORT
      LAYER M5 ;
        RECT  20.832 77.544 20.856 77.736 ;
    END
  END a[421]
  PIN a[422]
    DIRECTION INPUT ;
    USE SIGNAL ;
    PORT
      LAYER M5 ;
        RECT  20.88 77.544 20.904 77.736 ;
    END
  END a[422]
  PIN a[423]
    DIRECTION INPUT ;
    USE SIGNAL ;
    PORT
      LAYER M5 ;
        RECT  20.928 77.544 20.952 77.736 ;
    END
  END a[423]
  PIN a[424]
    DIRECTION INPUT ;
    USE SIGNAL ;
    PORT
      LAYER M5 ;
        RECT  20.976 77.544 21 77.736 ;
    END
  END a[424]
  PIN a[425]
    DIRECTION INPUT ;
    USE SIGNAL ;
    PORT
      LAYER M5 ;
        RECT  21.024 77.544 21.048 77.736 ;
    END
  END a[425]
  PIN a[426]
    DIRECTION INPUT ;
    USE SIGNAL ;
    PORT
      LAYER M5 ;
        RECT  21.072 77.544 21.096 77.736 ;
    END
  END a[426]
  PIN a[427]
    DIRECTION INPUT ;
    USE SIGNAL ;
    PORT
      LAYER M5 ;
        RECT  21.12 77.544 21.144 77.736 ;
    END
  END a[427]
  PIN a[428]
    DIRECTION INPUT ;
    USE SIGNAL ;
    PORT
      LAYER M5 ;
        RECT  21.168 77.544 21.192 77.736 ;
    END
  END a[428]
  PIN a[429]
    DIRECTION INPUT ;
    USE SIGNAL ;
    PORT
      LAYER M5 ;
        RECT  21.216 77.544 21.24 77.736 ;
    END
  END a[429]
  PIN a[42]
    DIRECTION INPUT ;
    USE SIGNAL ;
    PORT
      LAYER M5 ;
        RECT  2.64 77.544 2.664 77.736 ;
    END
  END a[42]
  PIN a[430]
    DIRECTION INPUT ;
    USE SIGNAL ;
    PORT
      LAYER M5 ;
        RECT  21.264 77.544 21.288 77.736 ;
    END
  END a[430]
  PIN a[431]
    DIRECTION INPUT ;
    USE SIGNAL ;
    PORT
      LAYER M5 ;
        RECT  21.312 77.544 21.336 77.736 ;
    END
  END a[431]
  PIN a[432]
    DIRECTION INPUT ;
    USE SIGNAL ;
    PORT
      LAYER M5 ;
        RECT  21.36 77.544 21.384 77.736 ;
    END
  END a[432]
  PIN a[433]
    DIRECTION INPUT ;
    USE SIGNAL ;
    PORT
      LAYER M5 ;
        RECT  21.408 77.544 21.432 77.736 ;
    END
  END a[433]
  PIN a[434]
    DIRECTION INPUT ;
    USE SIGNAL ;
    PORT
      LAYER M5 ;
        RECT  21.456 77.544 21.48 77.736 ;
    END
  END a[434]
  PIN a[435]
    DIRECTION INPUT ;
    USE SIGNAL ;
    PORT
      LAYER M5 ;
        RECT  21.504 77.544 21.528 77.736 ;
    END
  END a[435]
  PIN a[436]
    DIRECTION INPUT ;
    USE SIGNAL ;
    PORT
      LAYER M5 ;
        RECT  21.552 77.544 21.576 77.736 ;
    END
  END a[436]
  PIN a[437]
    DIRECTION INPUT ;
    USE SIGNAL ;
    PORT
      LAYER M5 ;
        RECT  21.6 77.544 21.624 77.736 ;
    END
  END a[437]
  PIN a[438]
    DIRECTION INPUT ;
    USE SIGNAL ;
    PORT
      LAYER M5 ;
        RECT  21.648 77.544 21.672 77.736 ;
    END
  END a[438]
  PIN a[439]
    DIRECTION INPUT ;
    USE SIGNAL ;
    PORT
      LAYER M5 ;
        RECT  21.696 77.544 21.72 77.736 ;
    END
  END a[439]
  PIN a[43]
    DIRECTION INPUT ;
    USE SIGNAL ;
    PORT
      LAYER M5 ;
        RECT  2.688 77.544 2.712 77.736 ;
    END
  END a[43]
  PIN a[440]
    DIRECTION INPUT ;
    USE SIGNAL ;
    PORT
      LAYER M5 ;
        RECT  21.744 77.544 21.768 77.736 ;
    END
  END a[440]
  PIN a[441]
    DIRECTION INPUT ;
    USE SIGNAL ;
    PORT
      LAYER M5 ;
        RECT  21.792 77.544 21.816 77.736 ;
    END
  END a[441]
  PIN a[442]
    DIRECTION INPUT ;
    USE SIGNAL ;
    PORT
      LAYER M5 ;
        RECT  21.84 77.544 21.864 77.736 ;
    END
  END a[442]
  PIN a[443]
    DIRECTION INPUT ;
    USE SIGNAL ;
    PORT
      LAYER M5 ;
        RECT  21.888 77.544 21.912 77.736 ;
    END
  END a[443]
  PIN a[444]
    DIRECTION INPUT ;
    USE SIGNAL ;
    PORT
      LAYER M5 ;
        RECT  21.936 77.544 21.96 77.736 ;
    END
  END a[444]
  PIN a[445]
    DIRECTION INPUT ;
    USE SIGNAL ;
    PORT
      LAYER M5 ;
        RECT  21.984 77.544 22.008 77.736 ;
    END
  END a[445]
  PIN a[446]
    DIRECTION INPUT ;
    USE SIGNAL ;
    PORT
      LAYER M5 ;
        RECT  22.032 77.544 22.056 77.736 ;
    END
  END a[446]
  PIN a[447]
    DIRECTION INPUT ;
    USE SIGNAL ;
    PORT
      LAYER M5 ;
        RECT  22.08 77.544 22.104 77.736 ;
    END
  END a[447]
  PIN a[448]
    DIRECTION INPUT ;
    USE SIGNAL ;
    PORT
      LAYER M5 ;
        RECT  22.128 77.544 22.152 77.736 ;
    END
  END a[448]
  PIN a[449]
    DIRECTION INPUT ;
    USE SIGNAL ;
    PORT
      LAYER M5 ;
        RECT  22.176 77.544 22.2 77.736 ;
    END
  END a[449]
  PIN a[44]
    DIRECTION INPUT ;
    USE SIGNAL ;
    PORT
      LAYER M5 ;
        RECT  2.736 77.544 2.76 77.736 ;
    END
  END a[44]
  PIN a[450]
    DIRECTION INPUT ;
    USE SIGNAL ;
    PORT
      LAYER M5 ;
        RECT  22.224 77.544 22.248 77.736 ;
    END
  END a[450]
  PIN a[451]
    DIRECTION INPUT ;
    USE SIGNAL ;
    PORT
      LAYER M5 ;
        RECT  22.272 77.544 22.296 77.736 ;
    END
  END a[451]
  PIN a[452]
    DIRECTION INPUT ;
    USE SIGNAL ;
    PORT
      LAYER M5 ;
        RECT  22.32 77.544 22.344 77.736 ;
    END
  END a[452]
  PIN a[453]
    DIRECTION INPUT ;
    USE SIGNAL ;
    PORT
      LAYER M5 ;
        RECT  22.368 77.544 22.392 77.736 ;
    END
  END a[453]
  PIN a[454]
    DIRECTION INPUT ;
    USE SIGNAL ;
    PORT
      LAYER M5 ;
        RECT  22.416 77.544 22.44 77.736 ;
    END
  END a[454]
  PIN a[455]
    DIRECTION INPUT ;
    USE SIGNAL ;
    PORT
      LAYER M5 ;
        RECT  22.464 77.544 22.488 77.736 ;
    END
  END a[455]
  PIN a[456]
    DIRECTION INPUT ;
    USE SIGNAL ;
    PORT
      LAYER M5 ;
        RECT  22.512 77.544 22.536 77.736 ;
    END
  END a[456]
  PIN a[457]
    DIRECTION INPUT ;
    USE SIGNAL ;
    PORT
      LAYER M5 ;
        RECT  22.56 77.544 22.584 77.736 ;
    END
  END a[457]
  PIN a[458]
    DIRECTION INPUT ;
    USE SIGNAL ;
    PORT
      LAYER M5 ;
        RECT  22.608 77.544 22.632 77.736 ;
    END
  END a[458]
  PIN a[459]
    DIRECTION INPUT ;
    USE SIGNAL ;
    PORT
      LAYER M5 ;
        RECT  22.656 77.544 22.68 77.736 ;
    END
  END a[459]
  PIN a[45]
    DIRECTION INPUT ;
    USE SIGNAL ;
    PORT
      LAYER M5 ;
        RECT  2.784 77.544 2.808 77.736 ;
    END
  END a[45]
  PIN a[460]
    DIRECTION INPUT ;
    USE SIGNAL ;
    PORT
      LAYER M5 ;
        RECT  22.704 77.544 22.728 77.736 ;
    END
  END a[460]
  PIN a[461]
    DIRECTION INPUT ;
    USE SIGNAL ;
    PORT
      LAYER M5 ;
        RECT  22.752 77.544 22.776 77.736 ;
    END
  END a[461]
  PIN a[462]
    DIRECTION INPUT ;
    USE SIGNAL ;
    PORT
      LAYER M5 ;
        RECT  22.8 77.544 22.824 77.736 ;
    END
  END a[462]
  PIN a[463]
    DIRECTION INPUT ;
    USE SIGNAL ;
    PORT
      LAYER M5 ;
        RECT  22.848 77.544 22.872 77.736 ;
    END
  END a[463]
  PIN a[464]
    DIRECTION INPUT ;
    USE SIGNAL ;
    PORT
      LAYER M5 ;
        RECT  22.896 77.544 22.92 77.736 ;
    END
  END a[464]
  PIN a[465]
    DIRECTION INPUT ;
    USE SIGNAL ;
    PORT
      LAYER M5 ;
        RECT  22.944 77.544 22.968 77.736 ;
    END
  END a[465]
  PIN a[466]
    DIRECTION INPUT ;
    USE SIGNAL ;
    PORT
      LAYER M5 ;
        RECT  22.992 77.544 23.016 77.736 ;
    END
  END a[466]
  PIN a[467]
    DIRECTION INPUT ;
    USE SIGNAL ;
    PORT
      LAYER M5 ;
        RECT  23.04 77.544 23.064 77.736 ;
    END
  END a[467]
  PIN a[468]
    DIRECTION INPUT ;
    USE SIGNAL ;
    PORT
      LAYER M5 ;
        RECT  23.088 77.544 23.112 77.736 ;
    END
  END a[468]
  PIN a[469]
    DIRECTION INPUT ;
    USE SIGNAL ;
    PORT
      LAYER M5 ;
        RECT  23.136 77.544 23.16 77.736 ;
    END
  END a[469]
  PIN a[46]
    DIRECTION INPUT ;
    USE SIGNAL ;
    PORT
      LAYER M5 ;
        RECT  2.832 77.544 2.856 77.736 ;
    END
  END a[46]
  PIN a[470]
    DIRECTION INPUT ;
    USE SIGNAL ;
    PORT
      LAYER M5 ;
        RECT  23.184 77.544 23.208 77.736 ;
    END
  END a[470]
  PIN a[471]
    DIRECTION INPUT ;
    USE SIGNAL ;
    PORT
      LAYER M5 ;
        RECT  23.232 77.544 23.256 77.736 ;
    END
  END a[471]
  PIN a[472]
    DIRECTION INPUT ;
    USE SIGNAL ;
    PORT
      LAYER M5 ;
        RECT  23.28 77.544 23.304 77.736 ;
    END
  END a[472]
  PIN a[473]
    DIRECTION INPUT ;
    USE SIGNAL ;
    PORT
      LAYER M5 ;
        RECT  23.328 77.544 23.352 77.736 ;
    END
  END a[473]
  PIN a[474]
    DIRECTION INPUT ;
    USE SIGNAL ;
    PORT
      LAYER M5 ;
        RECT  23.376 77.544 23.4 77.736 ;
    END
  END a[474]
  PIN a[475]
    DIRECTION INPUT ;
    USE SIGNAL ;
    PORT
      LAYER M5 ;
        RECT  23.424 77.544 23.448 77.736 ;
    END
  END a[475]
  PIN a[476]
    DIRECTION INPUT ;
    USE SIGNAL ;
    PORT
      LAYER M5 ;
        RECT  23.472 77.544 23.496 77.736 ;
    END
  END a[476]
  PIN a[477]
    DIRECTION INPUT ;
    USE SIGNAL ;
    PORT
      LAYER M5 ;
        RECT  23.52 77.544 23.544 77.736 ;
    END
  END a[477]
  PIN a[478]
    DIRECTION INPUT ;
    USE SIGNAL ;
    PORT
      LAYER M5 ;
        RECT  23.568 77.544 23.592 77.736 ;
    END
  END a[478]
  PIN a[479]
    DIRECTION INPUT ;
    USE SIGNAL ;
    PORT
      LAYER M5 ;
        RECT  23.616 77.544 23.64 77.736 ;
    END
  END a[479]
  PIN a[47]
    DIRECTION INPUT ;
    USE SIGNAL ;
    PORT
      LAYER M5 ;
        RECT  2.88 77.544 2.904 77.736 ;
    END
  END a[47]
  PIN a[480]
    DIRECTION INPUT ;
    USE SIGNAL ;
    PORT
      LAYER M5 ;
        RECT  23.664 77.544 23.688 77.736 ;
    END
  END a[480]
  PIN a[481]
    DIRECTION INPUT ;
    USE SIGNAL ;
    PORT
      LAYER M5 ;
        RECT  23.712 77.544 23.736 77.736 ;
    END
  END a[481]
  PIN a[482]
    DIRECTION INPUT ;
    USE SIGNAL ;
    PORT
      LAYER M5 ;
        RECT  23.76 77.544 23.784 77.736 ;
    END
  END a[482]
  PIN a[483]
    DIRECTION INPUT ;
    USE SIGNAL ;
    PORT
      LAYER M5 ;
        RECT  23.808 77.544 23.832 77.736 ;
    END
  END a[483]
  PIN a[484]
    DIRECTION INPUT ;
    USE SIGNAL ;
    PORT
      LAYER M5 ;
        RECT  23.856 77.544 23.88 77.736 ;
    END
  END a[484]
  PIN a[485]
    DIRECTION INPUT ;
    USE SIGNAL ;
    PORT
      LAYER M5 ;
        RECT  23.904 77.544 23.928 77.736 ;
    END
  END a[485]
  PIN a[486]
    DIRECTION INPUT ;
    USE SIGNAL ;
    PORT
      LAYER M5 ;
        RECT  23.952 77.544 23.976 77.736 ;
    END
  END a[486]
  PIN a[487]
    DIRECTION INPUT ;
    USE SIGNAL ;
    PORT
      LAYER M5 ;
        RECT  24 77.544 24.024 77.736 ;
    END
  END a[487]
  PIN a[488]
    DIRECTION INPUT ;
    USE SIGNAL ;
    PORT
      LAYER M5 ;
        RECT  24.048 77.544 24.072 77.736 ;
    END
  END a[488]
  PIN a[489]
    DIRECTION INPUT ;
    USE SIGNAL ;
    PORT
      LAYER M5 ;
        RECT  24.096 77.544 24.12 77.736 ;
    END
  END a[489]
  PIN a[48]
    DIRECTION INPUT ;
    USE SIGNAL ;
    PORT
      LAYER M5 ;
        RECT  2.928 77.544 2.952 77.736 ;
    END
  END a[48]
  PIN a[490]
    DIRECTION INPUT ;
    USE SIGNAL ;
    PORT
      LAYER M5 ;
        RECT  24.144 77.544 24.168 77.736 ;
    END
  END a[490]
  PIN a[491]
    DIRECTION INPUT ;
    USE SIGNAL ;
    PORT
      LAYER M5 ;
        RECT  24.192 77.544 24.216 77.736 ;
    END
  END a[491]
  PIN a[492]
    DIRECTION INPUT ;
    USE SIGNAL ;
    PORT
      LAYER M5 ;
        RECT  24.24 77.544 24.264 77.736 ;
    END
  END a[492]
  PIN a[493]
    DIRECTION INPUT ;
    USE SIGNAL ;
    PORT
      LAYER M5 ;
        RECT  24.288 77.544 24.312 77.736 ;
    END
  END a[493]
  PIN a[494]
    DIRECTION INPUT ;
    USE SIGNAL ;
    PORT
      LAYER M5 ;
        RECT  24.336 77.544 24.36 77.736 ;
    END
  END a[494]
  PIN a[495]
    DIRECTION INPUT ;
    USE SIGNAL ;
    PORT
      LAYER M5 ;
        RECT  24.384 77.544 24.408 77.736 ;
    END
  END a[495]
  PIN a[496]
    DIRECTION INPUT ;
    USE SIGNAL ;
    PORT
      LAYER M5 ;
        RECT  24.432 77.544 24.456 77.736 ;
    END
  END a[496]
  PIN a[497]
    DIRECTION INPUT ;
    USE SIGNAL ;
    PORT
      LAYER M5 ;
        RECT  24.48 77.544 24.504 77.736 ;
    END
  END a[497]
  PIN a[498]
    DIRECTION INPUT ;
    USE SIGNAL ;
    PORT
      LAYER M5 ;
        RECT  24.528 77.544 24.552 77.736 ;
    END
  END a[498]
  PIN a[499]
    DIRECTION INPUT ;
    USE SIGNAL ;
    PORT
      LAYER M5 ;
        RECT  24.576 77.544 24.6 77.736 ;
    END
  END a[499]
  PIN a[49]
    DIRECTION INPUT ;
    USE SIGNAL ;
    PORT
      LAYER M5 ;
        RECT  2.976 77.544 3 77.736 ;
    END
  END a[49]
  PIN a[4]
    DIRECTION INPUT ;
    USE SIGNAL ;
    PORT
      LAYER M5 ;
        RECT  0.816 77.544 0.84 77.736 ;
    END
  END a[4]
  PIN a[500]
    DIRECTION INPUT ;
    USE SIGNAL ;
    PORT
      LAYER M5 ;
        RECT  24.624 77.544 24.648 77.736 ;
    END
  END a[500]
  PIN a[501]
    DIRECTION INPUT ;
    USE SIGNAL ;
    PORT
      LAYER M5 ;
        RECT  24.672 77.544 24.696 77.736 ;
    END
  END a[501]
  PIN a[502]
    DIRECTION INPUT ;
    USE SIGNAL ;
    PORT
      LAYER M5 ;
        RECT  24.72 77.544 24.744 77.736 ;
    END
  END a[502]
  PIN a[503]
    DIRECTION INPUT ;
    USE SIGNAL ;
    PORT
      LAYER M5 ;
        RECT  24.768 77.544 24.792 77.736 ;
    END
  END a[503]
  PIN a[504]
    DIRECTION INPUT ;
    USE SIGNAL ;
    PORT
      LAYER M5 ;
        RECT  24.816 77.544 24.84 77.736 ;
    END
  END a[504]
  PIN a[505]
    DIRECTION INPUT ;
    USE SIGNAL ;
    PORT
      LAYER M5 ;
        RECT  24.864 77.544 24.888 77.736 ;
    END
  END a[505]
  PIN a[506]
    DIRECTION INPUT ;
    USE SIGNAL ;
    PORT
      LAYER M5 ;
        RECT  24.912 77.544 24.936 77.736 ;
    END
  END a[506]
  PIN a[507]
    DIRECTION INPUT ;
    USE SIGNAL ;
    PORT
      LAYER M5 ;
        RECT  24.96 77.544 24.984 77.736 ;
    END
  END a[507]
  PIN a[508]
    DIRECTION INPUT ;
    USE SIGNAL ;
    PORT
      LAYER M5 ;
        RECT  25.008 77.544 25.032 77.736 ;
    END
  END a[508]
  PIN a[509]
    DIRECTION INPUT ;
    USE SIGNAL ;
    PORT
      LAYER M5 ;
        RECT  25.056 77.544 25.08 77.736 ;
    END
  END a[509]
  PIN a[50]
    DIRECTION INPUT ;
    USE SIGNAL ;
    PORT
      LAYER M5 ;
        RECT  3.024 77.544 3.048 77.736 ;
    END
  END a[50]
  PIN a[510]
    DIRECTION INPUT ;
    USE SIGNAL ;
    PORT
      LAYER M5 ;
        RECT  25.104 77.544 25.128 77.736 ;
    END
  END a[510]
  PIN a[511]
    DIRECTION INPUT ;
    USE SIGNAL ;
    PORT
      LAYER M5 ;
        RECT  25.152 77.544 25.176 77.736 ;
    END
  END a[511]
  PIN a[51]
    DIRECTION INPUT ;
    USE SIGNAL ;
    PORT
      LAYER M5 ;
        RECT  3.072 77.544 3.096 77.736 ;
    END
  END a[51]
  PIN a[52]
    DIRECTION INPUT ;
    USE SIGNAL ;
    PORT
      LAYER M5 ;
        RECT  3.12 77.544 3.144 77.736 ;
    END
  END a[52]
  PIN a[53]
    DIRECTION INPUT ;
    USE SIGNAL ;
    PORT
      LAYER M5 ;
        RECT  3.168 77.544 3.192 77.736 ;
    END
  END a[53]
  PIN a[54]
    DIRECTION INPUT ;
    USE SIGNAL ;
    PORT
      LAYER M5 ;
        RECT  3.216 77.544 3.24 77.736 ;
    END
  END a[54]
  PIN a[55]
    DIRECTION INPUT ;
    USE SIGNAL ;
    PORT
      LAYER M5 ;
        RECT  3.264 77.544 3.288 77.736 ;
    END
  END a[55]
  PIN a[56]
    DIRECTION INPUT ;
    USE SIGNAL ;
    PORT
      LAYER M5 ;
        RECT  3.312 77.544 3.336 77.736 ;
    END
  END a[56]
  PIN a[57]
    DIRECTION INPUT ;
    USE SIGNAL ;
    PORT
      LAYER M5 ;
        RECT  3.36 77.544 3.384 77.736 ;
    END
  END a[57]
  PIN a[58]
    DIRECTION INPUT ;
    USE SIGNAL ;
    PORT
      LAYER M5 ;
        RECT  3.408 77.544 3.432 77.736 ;
    END
  END a[58]
  PIN a[59]
    DIRECTION INPUT ;
    USE SIGNAL ;
    PORT
      LAYER M5 ;
        RECT  3.456 77.544 3.48 77.736 ;
    END
  END a[59]
  PIN a[5]
    DIRECTION INPUT ;
    USE SIGNAL ;
    PORT
      LAYER M5 ;
        RECT  0.864 77.544 0.888 77.736 ;
    END
  END a[5]
  PIN a[60]
    DIRECTION INPUT ;
    USE SIGNAL ;
    PORT
      LAYER M5 ;
        RECT  3.504 77.544 3.528 77.736 ;
    END
  END a[60]
  PIN a[61]
    DIRECTION INPUT ;
    USE SIGNAL ;
    PORT
      LAYER M5 ;
        RECT  3.552 77.544 3.576 77.736 ;
    END
  END a[61]
  PIN a[62]
    DIRECTION INPUT ;
    USE SIGNAL ;
    PORT
      LAYER M5 ;
        RECT  3.6 77.544 3.624 77.736 ;
    END
  END a[62]
  PIN a[63]
    DIRECTION INPUT ;
    USE SIGNAL ;
    PORT
      LAYER M5 ;
        RECT  3.648 77.544 3.672 77.736 ;
    END
  END a[63]
  PIN a[64]
    DIRECTION INPUT ;
    USE SIGNAL ;
    PORT
      LAYER M5 ;
        RECT  3.696 77.544 3.72 77.736 ;
    END
  END a[64]
  PIN a[65]
    DIRECTION INPUT ;
    USE SIGNAL ;
    PORT
      LAYER M5 ;
        RECT  3.744 77.544 3.768 77.736 ;
    END
  END a[65]
  PIN a[66]
    DIRECTION INPUT ;
    USE SIGNAL ;
    PORT
      LAYER M5 ;
        RECT  3.792 77.544 3.816 77.736 ;
    END
  END a[66]
  PIN a[67]
    DIRECTION INPUT ;
    USE SIGNAL ;
    PORT
      LAYER M5 ;
        RECT  3.84 77.544 3.864 77.736 ;
    END
  END a[67]
  PIN a[68]
    DIRECTION INPUT ;
    USE SIGNAL ;
    PORT
      LAYER M5 ;
        RECT  3.888 77.544 3.912 77.736 ;
    END
  END a[68]
  PIN a[69]
    DIRECTION INPUT ;
    USE SIGNAL ;
    PORT
      LAYER M5 ;
        RECT  3.936 77.544 3.96 77.736 ;
    END
  END a[69]
  PIN a[6]
    DIRECTION INPUT ;
    USE SIGNAL ;
    PORT
      LAYER M5 ;
        RECT  0.912 77.544 0.936 77.736 ;
    END
  END a[6]
  PIN a[70]
    DIRECTION INPUT ;
    USE SIGNAL ;
    PORT
      LAYER M5 ;
        RECT  3.984 77.544 4.008 77.736 ;
    END
  END a[70]
  PIN a[71]
    DIRECTION INPUT ;
    USE SIGNAL ;
    PORT
      LAYER M5 ;
        RECT  4.032 77.544 4.056 77.736 ;
    END
  END a[71]
  PIN a[72]
    DIRECTION INPUT ;
    USE SIGNAL ;
    PORT
      LAYER M5 ;
        RECT  4.08 77.544 4.104 77.736 ;
    END
  END a[72]
  PIN a[73]
    DIRECTION INPUT ;
    USE SIGNAL ;
    PORT
      LAYER M5 ;
        RECT  4.128 77.544 4.152 77.736 ;
    END
  END a[73]
  PIN a[74]
    DIRECTION INPUT ;
    USE SIGNAL ;
    PORT
      LAYER M5 ;
        RECT  4.176 77.544 4.2 77.736 ;
    END
  END a[74]
  PIN a[75]
    DIRECTION INPUT ;
    USE SIGNAL ;
    PORT
      LAYER M5 ;
        RECT  4.224 77.544 4.248 77.736 ;
    END
  END a[75]
  PIN a[76]
    DIRECTION INPUT ;
    USE SIGNAL ;
    PORT
      LAYER M5 ;
        RECT  4.272 77.544 4.296 77.736 ;
    END
  END a[76]
  PIN a[77]
    DIRECTION INPUT ;
    USE SIGNAL ;
    PORT
      LAYER M5 ;
        RECT  4.32 77.544 4.344 77.736 ;
    END
  END a[77]
  PIN a[78]
    DIRECTION INPUT ;
    USE SIGNAL ;
    PORT
      LAYER M5 ;
        RECT  4.368 77.544 4.392 77.736 ;
    END
  END a[78]
  PIN a[79]
    DIRECTION INPUT ;
    USE SIGNAL ;
    PORT
      LAYER M5 ;
        RECT  4.416 77.544 4.44 77.736 ;
    END
  END a[79]
  PIN a[7]
    DIRECTION INPUT ;
    USE SIGNAL ;
    PORT
      LAYER M5 ;
        RECT  0.96 77.544 0.984 77.736 ;
    END
  END a[7]
  PIN a[80]
    DIRECTION INPUT ;
    USE SIGNAL ;
    PORT
      LAYER M5 ;
        RECT  4.464 77.544 4.488 77.736 ;
    END
  END a[80]
  PIN a[81]
    DIRECTION INPUT ;
    USE SIGNAL ;
    PORT
      LAYER M5 ;
        RECT  4.512 77.544 4.536 77.736 ;
    END
  END a[81]
  PIN a[82]
    DIRECTION INPUT ;
    USE SIGNAL ;
    PORT
      LAYER M5 ;
        RECT  4.56 77.544 4.584 77.736 ;
    END
  END a[82]
  PIN a[83]
    DIRECTION INPUT ;
    USE SIGNAL ;
    PORT
      LAYER M5 ;
        RECT  4.608 77.544 4.632 77.736 ;
    END
  END a[83]
  PIN a[84]
    DIRECTION INPUT ;
    USE SIGNAL ;
    PORT
      LAYER M5 ;
        RECT  4.656 77.544 4.68 77.736 ;
    END
  END a[84]
  PIN a[85]
    DIRECTION INPUT ;
    USE SIGNAL ;
    PORT
      LAYER M5 ;
        RECT  4.704 77.544 4.728 77.736 ;
    END
  END a[85]
  PIN a[86]
    DIRECTION INPUT ;
    USE SIGNAL ;
    PORT
      LAYER M5 ;
        RECT  4.752 77.544 4.776 77.736 ;
    END
  END a[86]
  PIN a[87]
    DIRECTION INPUT ;
    USE SIGNAL ;
    PORT
      LAYER M5 ;
        RECT  4.8 77.544 4.824 77.736 ;
    END
  END a[87]
  PIN a[88]
    DIRECTION INPUT ;
    USE SIGNAL ;
    PORT
      LAYER M5 ;
        RECT  4.848 77.544 4.872 77.736 ;
    END
  END a[88]
  PIN a[89]
    DIRECTION INPUT ;
    USE SIGNAL ;
    PORT
      LAYER M5 ;
        RECT  4.896 77.544 4.92 77.736 ;
    END
  END a[89]
  PIN a[8]
    DIRECTION INPUT ;
    USE SIGNAL ;
    PORT
      LAYER M5 ;
        RECT  1.008 77.544 1.032 77.736 ;
    END
  END a[8]
  PIN a[90]
    DIRECTION INPUT ;
    USE SIGNAL ;
    PORT
      LAYER M5 ;
        RECT  4.944 77.544 4.968 77.736 ;
    END
  END a[90]
  PIN a[91]
    DIRECTION INPUT ;
    USE SIGNAL ;
    PORT
      LAYER M5 ;
        RECT  4.992 77.544 5.016 77.736 ;
    END
  END a[91]
  PIN a[92]
    DIRECTION INPUT ;
    USE SIGNAL ;
    PORT
      LAYER M5 ;
        RECT  5.04 77.544 5.064 77.736 ;
    END
  END a[92]
  PIN a[93]
    DIRECTION INPUT ;
    USE SIGNAL ;
    PORT
      LAYER M5 ;
        RECT  5.088 77.544 5.112 77.736 ;
    END
  END a[93]
  PIN a[94]
    DIRECTION INPUT ;
    USE SIGNAL ;
    PORT
      LAYER M5 ;
        RECT  5.136 77.544 5.16 77.736 ;
    END
  END a[94]
  PIN a[95]
    DIRECTION INPUT ;
    USE SIGNAL ;
    PORT
      LAYER M5 ;
        RECT  5.184 77.544 5.208 77.736 ;
    END
  END a[95]
  PIN a[96]
    DIRECTION INPUT ;
    USE SIGNAL ;
    PORT
      LAYER M5 ;
        RECT  5.232 77.544 5.256 77.736 ;
    END
  END a[96]
  PIN a[97]
    DIRECTION INPUT ;
    USE SIGNAL ;
    PORT
      LAYER M5 ;
        RECT  5.28 77.544 5.304 77.736 ;
    END
  END a[97]
  PIN a[98]
    DIRECTION INPUT ;
    USE SIGNAL ;
    PORT
      LAYER M5 ;
        RECT  5.328 77.544 5.352 77.736 ;
    END
  END a[98]
  PIN a[99]
    DIRECTION INPUT ;
    USE SIGNAL ;
    PORT
      LAYER M5 ;
        RECT  5.376 77.544 5.4 77.736 ;
    END
  END a[99]
  PIN a[9]
    DIRECTION INPUT ;
    USE SIGNAL ;
    PORT
      LAYER M5 ;
        RECT  1.056 77.544 1.08 77.736 ;
    END
  END a[9]
  PIN b[0]
    DIRECTION OUTPUT ;
    USE SIGNAL ;
    PORT
      LAYER M5 ;
        RECT  14.064 0 14.088 0.192 ;
    END
  END b[0]
  PIN b[100]
    DIRECTION OUTPUT ;
    USE SIGNAL ;
    PORT
      LAYER M5 ;
        RECT  18.864 0 18.888 0.192 ;
    END
  END b[100]
  PIN b[101]
    DIRECTION OUTPUT ;
    USE SIGNAL ;
    PORT
      LAYER M5 ;
        RECT  18.912 0 18.936 0.192 ;
    END
  END b[101]
  PIN b[102]
    DIRECTION OUTPUT ;
    USE SIGNAL ;
    PORT
      LAYER M5 ;
        RECT  18.96 0 18.984 0.192 ;
    END
  END b[102]
  PIN b[103]
    DIRECTION OUTPUT ;
    USE SIGNAL ;
    PORT
      LAYER M5 ;
        RECT  19.008 0 19.032 0.192 ;
    END
  END b[103]
  PIN b[104]
    DIRECTION OUTPUT ;
    USE SIGNAL ;
    PORT
      LAYER M5 ;
        RECT  19.056 0 19.08 0.192 ;
    END
  END b[104]
  PIN b[105]
    DIRECTION OUTPUT ;
    USE SIGNAL ;
    PORT
      LAYER M5 ;
        RECT  19.104 0 19.128 0.192 ;
    END
  END b[105]
  PIN b[106]
    DIRECTION OUTPUT ;
    USE SIGNAL ;
    PORT
      LAYER M5 ;
        RECT  19.152 0 19.176 0.192 ;
    END
  END b[106]
  PIN b[107]
    DIRECTION OUTPUT ;
    USE SIGNAL ;
    PORT
      LAYER M5 ;
        RECT  19.2 0 19.224 0.192 ;
    END
  END b[107]
  PIN b[108]
    DIRECTION OUTPUT ;
    USE SIGNAL ;
    PORT
      LAYER M5 ;
        RECT  19.248 0 19.272 0.192 ;
    END
  END b[108]
  PIN b[109]
    DIRECTION OUTPUT ;
    USE SIGNAL ;
    PORT
      LAYER M5 ;
        RECT  19.296 0 19.32 0.192 ;
    END
  END b[109]
  PIN b[10]
    DIRECTION OUTPUT ;
    USE SIGNAL ;
    PORT
      LAYER M5 ;
        RECT  14.544 0 14.568 0.192 ;
    END
  END b[10]
  PIN b[110]
    DIRECTION OUTPUT ;
    USE SIGNAL ;
    PORT
      LAYER M5 ;
        RECT  19.344 0 19.368 0.192 ;
    END
  END b[110]
  PIN b[111]
    DIRECTION OUTPUT ;
    USE SIGNAL ;
    PORT
      LAYER M5 ;
        RECT  19.392 0 19.416 0.192 ;
    END
  END b[111]
  PIN b[112]
    DIRECTION OUTPUT ;
    USE SIGNAL ;
    PORT
      LAYER M5 ;
        RECT  19.44 0 19.464 0.192 ;
    END
  END b[112]
  PIN b[113]
    DIRECTION OUTPUT ;
    USE SIGNAL ;
    PORT
      LAYER M5 ;
        RECT  19.488 0 19.512 0.192 ;
    END
  END b[113]
  PIN b[114]
    DIRECTION OUTPUT ;
    USE SIGNAL ;
    PORT
      LAYER M5 ;
        RECT  19.536 0 19.56 0.192 ;
    END
  END b[114]
  PIN b[115]
    DIRECTION OUTPUT ;
    USE SIGNAL ;
    PORT
      LAYER M5 ;
        RECT  19.584 0 19.608 0.192 ;
    END
  END b[115]
  PIN b[116]
    DIRECTION OUTPUT ;
    USE SIGNAL ;
    PORT
      LAYER M5 ;
        RECT  19.632 0 19.656 0.192 ;
    END
  END b[116]
  PIN b[117]
    DIRECTION OUTPUT ;
    USE SIGNAL ;
    PORT
      LAYER M5 ;
        RECT  19.68 0 19.704 0.192 ;
    END
  END b[117]
  PIN b[118]
    DIRECTION OUTPUT ;
    USE SIGNAL ;
    PORT
      LAYER M5 ;
        RECT  19.728 0 19.752 0.192 ;
    END
  END b[118]
  PIN b[119]
    DIRECTION OUTPUT ;
    USE SIGNAL ;
    PORT
      LAYER M5 ;
        RECT  19.776 0 19.8 0.192 ;
    END
  END b[119]
  PIN b[11]
    DIRECTION OUTPUT ;
    USE SIGNAL ;
    PORT
      LAYER M5 ;
        RECT  14.592 0 14.616 0.192 ;
    END
  END b[11]
  PIN b[120]
    DIRECTION OUTPUT ;
    USE SIGNAL ;
    PORT
      LAYER M5 ;
        RECT  19.824 0 19.848 0.192 ;
    END
  END b[120]
  PIN b[121]
    DIRECTION OUTPUT ;
    USE SIGNAL ;
    PORT
      LAYER M5 ;
        RECT  19.872 0 19.896 0.192 ;
    END
  END b[121]
  PIN b[122]
    DIRECTION OUTPUT ;
    USE SIGNAL ;
    PORT
      LAYER M5 ;
        RECT  19.92 0 19.944 0.192 ;
    END
  END b[122]
  PIN b[123]
    DIRECTION OUTPUT ;
    USE SIGNAL ;
    PORT
      LAYER M5 ;
        RECT  19.968 0 19.992 0.192 ;
    END
  END b[123]
  PIN b[124]
    DIRECTION OUTPUT ;
    USE SIGNAL ;
    PORT
      LAYER M5 ;
        RECT  20.016 0 20.04 0.192 ;
    END
  END b[124]
  PIN b[125]
    DIRECTION OUTPUT ;
    USE SIGNAL ;
    PORT
      LAYER M5 ;
        RECT  20.064 0 20.088 0.192 ;
    END
  END b[125]
  PIN b[126]
    DIRECTION OUTPUT ;
    USE SIGNAL ;
    PORT
      LAYER M5 ;
        RECT  20.112 0 20.136 0.192 ;
    END
  END b[126]
  PIN b[127]
    DIRECTION OUTPUT ;
    USE SIGNAL ;
    PORT
      LAYER M5 ;
        RECT  20.16 0 20.184 0.192 ;
    END
  END b[127]
  PIN b[128]
    DIRECTION OUTPUT ;
    USE SIGNAL ;
    PORT
      LAYER M5 ;
        RECT  20.208 0 20.232 0.192 ;
    END
  END b[128]
  PIN b[129]
    DIRECTION OUTPUT ;
    USE SIGNAL ;
    PORT
      LAYER M5 ;
        RECT  20.256 0 20.28 0.192 ;
    END
  END b[129]
  PIN b[12]
    DIRECTION OUTPUT ;
    USE SIGNAL ;
    PORT
      LAYER M5 ;
        RECT  14.64 0 14.664 0.192 ;
    END
  END b[12]
  PIN b[130]
    DIRECTION OUTPUT ;
    USE SIGNAL ;
    PORT
      LAYER M5 ;
        RECT  20.304 0 20.328 0.192 ;
    END
  END b[130]
  PIN b[131]
    DIRECTION OUTPUT ;
    USE SIGNAL ;
    PORT
      LAYER M5 ;
        RECT  20.352 0 20.376 0.192 ;
    END
  END b[131]
  PIN b[132]
    DIRECTION OUTPUT ;
    USE SIGNAL ;
    PORT
      LAYER M5 ;
        RECT  20.4 0 20.424 0.192 ;
    END
  END b[132]
  PIN b[133]
    DIRECTION OUTPUT ;
    USE SIGNAL ;
    PORT
      LAYER M5 ;
        RECT  20.448 0 20.472 0.192 ;
    END
  END b[133]
  PIN b[134]
    DIRECTION OUTPUT ;
    USE SIGNAL ;
    PORT
      LAYER M5 ;
        RECT  20.496 0 20.52 0.192 ;
    END
  END b[134]
  PIN b[135]
    DIRECTION OUTPUT ;
    USE SIGNAL ;
    PORT
      LAYER M5 ;
        RECT  20.544 0 20.568 0.192 ;
    END
  END b[135]
  PIN b[136]
    DIRECTION OUTPUT ;
    USE SIGNAL ;
    PORT
      LAYER M5 ;
        RECT  20.592 0 20.616 0.192 ;
    END
  END b[136]
  PIN b[137]
    DIRECTION OUTPUT ;
    USE SIGNAL ;
    PORT
      LAYER M5 ;
        RECT  20.64 0 20.664 0.192 ;
    END
  END b[137]
  PIN b[138]
    DIRECTION OUTPUT ;
    USE SIGNAL ;
    PORT
      LAYER M5 ;
        RECT  20.688 0 20.712 0.192 ;
    END
  END b[138]
  PIN b[139]
    DIRECTION OUTPUT ;
    USE SIGNAL ;
    PORT
      LAYER M5 ;
        RECT  20.736 0 20.76 0.192 ;
    END
  END b[139]
  PIN b[13]
    DIRECTION OUTPUT ;
    USE SIGNAL ;
    PORT
      LAYER M5 ;
        RECT  14.688 0 14.712 0.192 ;
    END
  END b[13]
  PIN b[140]
    DIRECTION OUTPUT ;
    USE SIGNAL ;
    PORT
      LAYER M5 ;
        RECT  20.784 0 20.808 0.192 ;
    END
  END b[140]
  PIN b[141]
    DIRECTION OUTPUT ;
    USE SIGNAL ;
    PORT
      LAYER M5 ;
        RECT  20.832 0 20.856 0.192 ;
    END
  END b[141]
  PIN b[142]
    DIRECTION OUTPUT ;
    USE SIGNAL ;
    PORT
      LAYER M5 ;
        RECT  20.88 0 20.904 0.192 ;
    END
  END b[142]
  PIN b[143]
    DIRECTION OUTPUT ;
    USE SIGNAL ;
    PORT
      LAYER M5 ;
        RECT  20.928 0 20.952 0.192 ;
    END
  END b[143]
  PIN b[144]
    DIRECTION OUTPUT ;
    USE SIGNAL ;
    PORT
      LAYER M5 ;
        RECT  20.976 0 21 0.192 ;
    END
  END b[144]
  PIN b[145]
    DIRECTION OUTPUT ;
    USE SIGNAL ;
    PORT
      LAYER M5 ;
        RECT  21.024 0 21.048 0.192 ;
    END
  END b[145]
  PIN b[146]
    DIRECTION OUTPUT ;
    USE SIGNAL ;
    PORT
      LAYER M5 ;
        RECT  21.072 0 21.096 0.192 ;
    END
  END b[146]
  PIN b[147]
    DIRECTION OUTPUT ;
    USE SIGNAL ;
    PORT
      LAYER M5 ;
        RECT  21.12 0 21.144 0.192 ;
    END
  END b[147]
  PIN b[148]
    DIRECTION OUTPUT ;
    USE SIGNAL ;
    PORT
      LAYER M5 ;
        RECT  21.168 0 21.192 0.192 ;
    END
  END b[148]
  PIN b[149]
    DIRECTION OUTPUT ;
    USE SIGNAL ;
    PORT
      LAYER M5 ;
        RECT  21.216 0 21.24 0.192 ;
    END
  END b[149]
  PIN b[14]
    DIRECTION OUTPUT ;
    USE SIGNAL ;
    PORT
      LAYER M5 ;
        RECT  14.736 0 14.76 0.192 ;
    END
  END b[14]
  PIN b[150]
    DIRECTION OUTPUT ;
    USE SIGNAL ;
    PORT
      LAYER M5 ;
        RECT  21.264 0 21.288 0.192 ;
    END
  END b[150]
  PIN b[151]
    DIRECTION OUTPUT ;
    USE SIGNAL ;
    PORT
      LAYER M5 ;
        RECT  21.312 0 21.336 0.192 ;
    END
  END b[151]
  PIN b[152]
    DIRECTION OUTPUT ;
    USE SIGNAL ;
    PORT
      LAYER M5 ;
        RECT  21.36 0 21.384 0.192 ;
    END
  END b[152]
  PIN b[153]
    DIRECTION OUTPUT ;
    USE SIGNAL ;
    PORT
      LAYER M5 ;
        RECT  21.408 0 21.432 0.192 ;
    END
  END b[153]
  PIN b[154]
    DIRECTION OUTPUT ;
    USE SIGNAL ;
    PORT
      LAYER M5 ;
        RECT  21.456 0 21.48 0.192 ;
    END
  END b[154]
  PIN b[155]
    DIRECTION OUTPUT ;
    USE SIGNAL ;
    PORT
      LAYER M5 ;
        RECT  21.504 0 21.528 0.192 ;
    END
  END b[155]
  PIN b[156]
    DIRECTION OUTPUT ;
    USE SIGNAL ;
    PORT
      LAYER M5 ;
        RECT  21.552 0 21.576 0.192 ;
    END
  END b[156]
  PIN b[157]
    DIRECTION OUTPUT ;
    USE SIGNAL ;
    PORT
      LAYER M5 ;
        RECT  21.6 0 21.624 0.192 ;
    END
  END b[157]
  PIN b[158]
    DIRECTION OUTPUT ;
    USE SIGNAL ;
    PORT
      LAYER M5 ;
        RECT  21.648 0 21.672 0.192 ;
    END
  END b[158]
  PIN b[159]
    DIRECTION OUTPUT ;
    USE SIGNAL ;
    PORT
      LAYER M5 ;
        RECT  21.696 0 21.72 0.192 ;
    END
  END b[159]
  PIN b[15]
    DIRECTION OUTPUT ;
    USE SIGNAL ;
    PORT
      LAYER M5 ;
        RECT  14.784 0 14.808 0.192 ;
    END
  END b[15]
  PIN b[160]
    DIRECTION OUTPUT ;
    USE SIGNAL ;
    PORT
      LAYER M5 ;
        RECT  21.744 0 21.768 0.192 ;
    END
  END b[160]
  PIN b[161]
    DIRECTION OUTPUT ;
    USE SIGNAL ;
    PORT
      LAYER M5 ;
        RECT  21.792 0 21.816 0.192 ;
    END
  END b[161]
  PIN b[162]
    DIRECTION OUTPUT ;
    USE SIGNAL ;
    PORT
      LAYER M5 ;
        RECT  21.84 0 21.864 0.192 ;
    END
  END b[162]
  PIN b[163]
    DIRECTION OUTPUT ;
    USE SIGNAL ;
    PORT
      LAYER M5 ;
        RECT  21.888 0 21.912 0.192 ;
    END
  END b[163]
  PIN b[164]
    DIRECTION OUTPUT ;
    USE SIGNAL ;
    PORT
      LAYER M5 ;
        RECT  21.936 0 21.96 0.192 ;
    END
  END b[164]
  PIN b[165]
    DIRECTION OUTPUT ;
    USE SIGNAL ;
    PORT
      LAYER M5 ;
        RECT  21.984 0 22.008 0.192 ;
    END
  END b[165]
  PIN b[166]
    DIRECTION OUTPUT ;
    USE SIGNAL ;
    PORT
      LAYER M5 ;
        RECT  22.032 0 22.056 0.192 ;
    END
  END b[166]
  PIN b[167]
    DIRECTION OUTPUT ;
    USE SIGNAL ;
    PORT
      LAYER M5 ;
        RECT  22.08 0 22.104 0.192 ;
    END
  END b[167]
  PIN b[168]
    DIRECTION OUTPUT ;
    USE SIGNAL ;
    PORT
      LAYER M5 ;
        RECT  22.128 0 22.152 0.192 ;
    END
  END b[168]
  PIN b[169]
    DIRECTION OUTPUT ;
    USE SIGNAL ;
    PORT
      LAYER M5 ;
        RECT  22.176 0 22.2 0.192 ;
    END
  END b[169]
  PIN b[16]
    DIRECTION OUTPUT ;
    USE SIGNAL ;
    PORT
      LAYER M5 ;
        RECT  14.832 0 14.856 0.192 ;
    END
  END b[16]
  PIN b[170]
    DIRECTION OUTPUT ;
    USE SIGNAL ;
    PORT
      LAYER M5 ;
        RECT  22.224 0 22.248 0.192 ;
    END
  END b[170]
  PIN b[171]
    DIRECTION OUTPUT ;
    USE SIGNAL ;
    PORT
      LAYER M5 ;
        RECT  22.272 0 22.296 0.192 ;
    END
  END b[171]
  PIN b[172]
    DIRECTION OUTPUT ;
    USE SIGNAL ;
    PORT
      LAYER M5 ;
        RECT  22.32 0 22.344 0.192 ;
    END
  END b[172]
  PIN b[173]
    DIRECTION OUTPUT ;
    USE SIGNAL ;
    PORT
      LAYER M5 ;
        RECT  22.368 0 22.392 0.192 ;
    END
  END b[173]
  PIN b[174]
    DIRECTION OUTPUT ;
    USE SIGNAL ;
    PORT
      LAYER M5 ;
        RECT  22.416 0 22.44 0.192 ;
    END
  END b[174]
  PIN b[175]
    DIRECTION OUTPUT ;
    USE SIGNAL ;
    PORT
      LAYER M5 ;
        RECT  22.464 0 22.488 0.192 ;
    END
  END b[175]
  PIN b[176]
    DIRECTION OUTPUT ;
    USE SIGNAL ;
    PORT
      LAYER M5 ;
        RECT  22.512 0 22.536 0.192 ;
    END
  END b[176]
  PIN b[177]
    DIRECTION OUTPUT ;
    USE SIGNAL ;
    PORT
      LAYER M5 ;
        RECT  22.56 0 22.584 0.192 ;
    END
  END b[177]
  PIN b[178]
    DIRECTION OUTPUT ;
    USE SIGNAL ;
    PORT
      LAYER M5 ;
        RECT  22.608 0 22.632 0.192 ;
    END
  END b[178]
  PIN b[179]
    DIRECTION OUTPUT ;
    USE SIGNAL ;
    PORT
      LAYER M5 ;
        RECT  22.656 0 22.68 0.192 ;
    END
  END b[179]
  PIN b[17]
    DIRECTION OUTPUT ;
    USE SIGNAL ;
    PORT
      LAYER M5 ;
        RECT  14.88 0 14.904 0.192 ;
    END
  END b[17]
  PIN b[180]
    DIRECTION OUTPUT ;
    USE SIGNAL ;
    PORT
      LAYER M5 ;
        RECT  22.704 0 22.728 0.192 ;
    END
  END b[180]
  PIN b[181]
    DIRECTION OUTPUT ;
    USE SIGNAL ;
    PORT
      LAYER M5 ;
        RECT  22.752 0 22.776 0.192 ;
    END
  END b[181]
  PIN b[182]
    DIRECTION OUTPUT ;
    USE SIGNAL ;
    PORT
      LAYER M5 ;
        RECT  22.8 0 22.824 0.192 ;
    END
  END b[182]
  PIN b[183]
    DIRECTION OUTPUT ;
    USE SIGNAL ;
    PORT
      LAYER M5 ;
        RECT  22.848 0 22.872 0.192 ;
    END
  END b[183]
  PIN b[184]
    DIRECTION OUTPUT ;
    USE SIGNAL ;
    PORT
      LAYER M5 ;
        RECT  22.896 0 22.92 0.192 ;
    END
  END b[184]
  PIN b[185]
    DIRECTION OUTPUT ;
    USE SIGNAL ;
    PORT
      LAYER M5 ;
        RECT  22.944 0 22.968 0.192 ;
    END
  END b[185]
  PIN b[186]
    DIRECTION OUTPUT ;
    USE SIGNAL ;
    PORT
      LAYER M5 ;
        RECT  22.992 0 23.016 0.192 ;
    END
  END b[186]
  PIN b[187]
    DIRECTION OUTPUT ;
    USE SIGNAL ;
    PORT
      LAYER M5 ;
        RECT  23.04 0 23.064 0.192 ;
    END
  END b[187]
  PIN b[188]
    DIRECTION OUTPUT ;
    USE SIGNAL ;
    PORT
      LAYER M5 ;
        RECT  23.088 0 23.112 0.192 ;
    END
  END b[188]
  PIN b[189]
    DIRECTION OUTPUT ;
    USE SIGNAL ;
    PORT
      LAYER M5 ;
        RECT  23.136 0 23.16 0.192 ;
    END
  END b[189]
  PIN b[18]
    DIRECTION OUTPUT ;
    USE SIGNAL ;
    PORT
      LAYER M5 ;
        RECT  14.928 0 14.952 0.192 ;
    END
  END b[18]
  PIN b[190]
    DIRECTION OUTPUT ;
    USE SIGNAL ;
    PORT
      LAYER M5 ;
        RECT  23.184 0 23.208 0.192 ;
    END
  END b[190]
  PIN b[191]
    DIRECTION OUTPUT ;
    USE SIGNAL ;
    PORT
      LAYER M5 ;
        RECT  23.232 0 23.256 0.192 ;
    END
  END b[191]
  PIN b[192]
    DIRECTION OUTPUT ;
    USE SIGNAL ;
    PORT
      LAYER M5 ;
        RECT  23.28 0 23.304 0.192 ;
    END
  END b[192]
  PIN b[193]
    DIRECTION OUTPUT ;
    USE SIGNAL ;
    PORT
      LAYER M5 ;
        RECT  23.328 0 23.352 0.192 ;
    END
  END b[193]
  PIN b[194]
    DIRECTION OUTPUT ;
    USE SIGNAL ;
    PORT
      LAYER M5 ;
        RECT  23.376 0 23.4 0.192 ;
    END
  END b[194]
  PIN b[195]
    DIRECTION OUTPUT ;
    USE SIGNAL ;
    PORT
      LAYER M5 ;
        RECT  23.424 0 23.448 0.192 ;
    END
  END b[195]
  PIN b[196]
    DIRECTION OUTPUT ;
    USE SIGNAL ;
    PORT
      LAYER M5 ;
        RECT  23.472 0 23.496 0.192 ;
    END
  END b[196]
  PIN b[197]
    DIRECTION OUTPUT ;
    USE SIGNAL ;
    PORT
      LAYER M5 ;
        RECT  23.52 0 23.544 0.192 ;
    END
  END b[197]
  PIN b[198]
    DIRECTION OUTPUT ;
    USE SIGNAL ;
    PORT
      LAYER M5 ;
        RECT  23.568 0 23.592 0.192 ;
    END
  END b[198]
  PIN b[199]
    DIRECTION OUTPUT ;
    USE SIGNAL ;
    PORT
      LAYER M5 ;
        RECT  23.616 0 23.64 0.192 ;
    END
  END b[199]
  PIN b[19]
    DIRECTION OUTPUT ;
    USE SIGNAL ;
    PORT
      LAYER M5 ;
        RECT  14.976 0 15 0.192 ;
    END
  END b[19]
  PIN b[1]
    DIRECTION OUTPUT ;
    USE SIGNAL ;
    PORT
      LAYER M5 ;
        RECT  14.112 0 14.136 0.192 ;
    END
  END b[1]
  PIN b[200]
    DIRECTION OUTPUT ;
    USE SIGNAL ;
    PORT
      LAYER M5 ;
        RECT  23.664 0 23.688 0.192 ;
    END
  END b[200]
  PIN b[201]
    DIRECTION OUTPUT ;
    USE SIGNAL ;
    PORT
      LAYER M5 ;
        RECT  23.712 0 23.736 0.192 ;
    END
  END b[201]
  PIN b[202]
    DIRECTION OUTPUT ;
    USE SIGNAL ;
    PORT
      LAYER M5 ;
        RECT  23.76 0 23.784 0.192 ;
    END
  END b[202]
  PIN b[203]
    DIRECTION OUTPUT ;
    USE SIGNAL ;
    PORT
      LAYER M5 ;
        RECT  23.808 0 23.832 0.192 ;
    END
  END b[203]
  PIN b[204]
    DIRECTION OUTPUT ;
    USE SIGNAL ;
    PORT
      LAYER M5 ;
        RECT  23.856 0 23.88 0.192 ;
    END
  END b[204]
  PIN b[205]
    DIRECTION OUTPUT ;
    USE SIGNAL ;
    PORT
      LAYER M5 ;
        RECT  23.904 0 23.928 0.192 ;
    END
  END b[205]
  PIN b[206]
    DIRECTION OUTPUT ;
    USE SIGNAL ;
    PORT
      LAYER M5 ;
        RECT  23.952 0 23.976 0.192 ;
    END
  END b[206]
  PIN b[207]
    DIRECTION OUTPUT ;
    USE SIGNAL ;
    PORT
      LAYER M5 ;
        RECT  24 0 24.024 0.192 ;
    END
  END b[207]
  PIN b[208]
    DIRECTION OUTPUT ;
    USE SIGNAL ;
    PORT
      LAYER M5 ;
        RECT  24.048 0 24.072 0.192 ;
    END
  END b[208]
  PIN b[209]
    DIRECTION OUTPUT ;
    USE SIGNAL ;
    PORT
      LAYER M5 ;
        RECT  24.096 0 24.12 0.192 ;
    END
  END b[209]
  PIN b[20]
    DIRECTION OUTPUT ;
    USE SIGNAL ;
    PORT
      LAYER M5 ;
        RECT  15.024 0 15.048 0.192 ;
    END
  END b[20]
  PIN b[210]
    DIRECTION OUTPUT ;
    USE SIGNAL ;
    PORT
      LAYER M5 ;
        RECT  24.144 0 24.168 0.192 ;
    END
  END b[210]
  PIN b[211]
    DIRECTION OUTPUT ;
    USE SIGNAL ;
    PORT
      LAYER M5 ;
        RECT  24.192 0 24.216 0.192 ;
    END
  END b[211]
  PIN b[212]
    DIRECTION OUTPUT ;
    USE SIGNAL ;
    PORT
      LAYER M5 ;
        RECT  24.24 0 24.264 0.192 ;
    END
  END b[212]
  PIN b[213]
    DIRECTION OUTPUT ;
    USE SIGNAL ;
    PORT
      LAYER M5 ;
        RECT  24.288 0 24.312 0.192 ;
    END
  END b[213]
  PIN b[214]
    DIRECTION OUTPUT ;
    USE SIGNAL ;
    PORT
      LAYER M5 ;
        RECT  24.336 0 24.36 0.192 ;
    END
  END b[214]
  PIN b[215]
    DIRECTION OUTPUT ;
    USE SIGNAL ;
    PORT
      LAYER M5 ;
        RECT  24.384 0 24.408 0.192 ;
    END
  END b[215]
  PIN b[216]
    DIRECTION OUTPUT ;
    USE SIGNAL ;
    PORT
      LAYER M5 ;
        RECT  24.432 0 24.456 0.192 ;
    END
  END b[216]
  PIN b[217]
    DIRECTION OUTPUT ;
    USE SIGNAL ;
    PORT
      LAYER M5 ;
        RECT  24.48 0 24.504 0.192 ;
    END
  END b[217]
  PIN b[218]
    DIRECTION OUTPUT ;
    USE SIGNAL ;
    PORT
      LAYER M5 ;
        RECT  24.528 0 24.552 0.192 ;
    END
  END b[218]
  PIN b[219]
    DIRECTION OUTPUT ;
    USE SIGNAL ;
    PORT
      LAYER M5 ;
        RECT  24.576 0 24.6 0.192 ;
    END
  END b[219]
  PIN b[21]
    DIRECTION OUTPUT ;
    USE SIGNAL ;
    PORT
      LAYER M5 ;
        RECT  15.072 0 15.096 0.192 ;
    END
  END b[21]
  PIN b[220]
    DIRECTION OUTPUT ;
    USE SIGNAL ;
    PORT
      LAYER M5 ;
        RECT  24.624 0 24.648 0.192 ;
    END
  END b[220]
  PIN b[221]
    DIRECTION OUTPUT ;
    USE SIGNAL ;
    PORT
      LAYER M5 ;
        RECT  24.672 0 24.696 0.192 ;
    END
  END b[221]
  PIN b[222]
    DIRECTION OUTPUT ;
    USE SIGNAL ;
    PORT
      LAYER M5 ;
        RECT  24.72 0 24.744 0.192 ;
    END
  END b[222]
  PIN b[223]
    DIRECTION OUTPUT ;
    USE SIGNAL ;
    PORT
      LAYER M5 ;
        RECT  24.768 0 24.792 0.192 ;
    END
  END b[223]
  PIN b[224]
    DIRECTION OUTPUT ;
    USE SIGNAL ;
    PORT
      LAYER M5 ;
        RECT  24.816 0 24.84 0.192 ;
    END
  END b[224]
  PIN b[225]
    DIRECTION OUTPUT ;
    USE SIGNAL ;
    PORT
      LAYER M5 ;
        RECT  24.864 0 24.888 0.192 ;
    END
  END b[225]
  PIN b[226]
    DIRECTION OUTPUT ;
    USE SIGNAL ;
    PORT
      LAYER M5 ;
        RECT  24.912 0 24.936 0.192 ;
    END
  END b[226]
  PIN b[227]
    DIRECTION OUTPUT ;
    USE SIGNAL ;
    PORT
      LAYER M5 ;
        RECT  24.96 0 24.984 0.192 ;
    END
  END b[227]
  PIN b[228]
    DIRECTION OUTPUT ;
    USE SIGNAL ;
    PORT
      LAYER M5 ;
        RECT  25.008 0 25.032 0.192 ;
    END
  END b[228]
  PIN b[229]
    DIRECTION OUTPUT ;
    USE SIGNAL ;
    PORT
      LAYER M5 ;
        RECT  25.056 0 25.08 0.192 ;
    END
  END b[229]
  PIN b[22]
    DIRECTION OUTPUT ;
    USE SIGNAL ;
    PORT
      LAYER M5 ;
        RECT  15.12 0 15.144 0.192 ;
    END
  END b[22]
  PIN b[230]
    DIRECTION OUTPUT ;
    USE SIGNAL ;
    PORT
      LAYER M5 ;
        RECT  25.104 0 25.128 0.192 ;
    END
  END b[230]
  PIN b[231]
    DIRECTION OUTPUT ;
    USE SIGNAL ;
    PORT
      LAYER M5 ;
        RECT  25.152 0 25.176 0.192 ;
    END
  END b[231]
  PIN b[232]
    DIRECTION OUTPUT ;
    USE SIGNAL ;
    PORT
      LAYER M5 ;
        RECT  25.2 0 25.224 0.192 ;
    END
  END b[232]
  PIN b[233]
    DIRECTION OUTPUT ;
    USE SIGNAL ;
    PORT
      LAYER M5 ;
        RECT  25.248 0 25.272 0.192 ;
    END
  END b[233]
  PIN b[234]
    DIRECTION OUTPUT ;
    USE SIGNAL ;
    PORT
      LAYER M5 ;
        RECT  25.296 0 25.32 0.192 ;
    END
  END b[234]
  PIN b[235]
    DIRECTION OUTPUT ;
    USE SIGNAL ;
    PORT
      LAYER M5 ;
        RECT  25.344 0 25.368 0.192 ;
    END
  END b[235]
  PIN b[236]
    DIRECTION OUTPUT ;
    USE SIGNAL ;
    PORT
      LAYER M5 ;
        RECT  25.392 0 25.416 0.192 ;
    END
  END b[236]
  PIN b[237]
    DIRECTION OUTPUT ;
    USE SIGNAL ;
    PORT
      LAYER M5 ;
        RECT  25.44 0 25.464 0.192 ;
    END
  END b[237]
  PIN b[238]
    DIRECTION OUTPUT ;
    USE SIGNAL ;
    PORT
      LAYER M5 ;
        RECT  25.488 0 25.512 0.192 ;
    END
  END b[238]
  PIN b[239]
    DIRECTION OUTPUT ;
    USE SIGNAL ;
    PORT
      LAYER M5 ;
        RECT  25.536 0 25.56 0.192 ;
    END
  END b[239]
  PIN b[23]
    DIRECTION OUTPUT ;
    USE SIGNAL ;
    PORT
      LAYER M5 ;
        RECT  15.168 0 15.192 0.192 ;
    END
  END b[23]
  PIN b[240]
    DIRECTION OUTPUT ;
    USE SIGNAL ;
    PORT
      LAYER M5 ;
        RECT  25.584 0 25.608 0.192 ;
    END
  END b[240]
  PIN b[241]
    DIRECTION OUTPUT ;
    USE SIGNAL ;
    PORT
      LAYER M5 ;
        RECT  25.632 0 25.656 0.192 ;
    END
  END b[241]
  PIN b[242]
    DIRECTION OUTPUT ;
    USE SIGNAL ;
    PORT
      LAYER M5 ;
        RECT  25.68 0 25.704 0.192 ;
    END
  END b[242]
  PIN b[243]
    DIRECTION OUTPUT ;
    USE SIGNAL ;
    PORT
      LAYER M5 ;
        RECT  25.728 0 25.752 0.192 ;
    END
  END b[243]
  PIN b[244]
    DIRECTION OUTPUT ;
    USE SIGNAL ;
    PORT
      LAYER M5 ;
        RECT  25.776 0 25.8 0.192 ;
    END
  END b[244]
  PIN b[245]
    DIRECTION OUTPUT ;
    USE SIGNAL ;
    PORT
      LAYER M5 ;
        RECT  25.824 0 25.848 0.192 ;
    END
  END b[245]
  PIN b[246]
    DIRECTION OUTPUT ;
    USE SIGNAL ;
    PORT
      LAYER M5 ;
        RECT  25.872 0 25.896 0.192 ;
    END
  END b[246]
  PIN b[247]
    DIRECTION OUTPUT ;
    USE SIGNAL ;
    PORT
      LAYER M5 ;
        RECT  25.92 0 25.944 0.192 ;
    END
  END b[247]
  PIN b[248]
    DIRECTION OUTPUT ;
    USE SIGNAL ;
    PORT
      LAYER M5 ;
        RECT  25.968 0 25.992 0.192 ;
    END
  END b[248]
  PIN b[249]
    DIRECTION OUTPUT ;
    USE SIGNAL ;
    PORT
      LAYER M5 ;
        RECT  26.016 0 26.04 0.192 ;
    END
  END b[249]
  PIN b[24]
    DIRECTION OUTPUT ;
    USE SIGNAL ;
    PORT
      LAYER M5 ;
        RECT  15.216 0 15.24 0.192 ;
    END
  END b[24]
  PIN b[250]
    DIRECTION OUTPUT ;
    USE SIGNAL ;
    PORT
      LAYER M5 ;
        RECT  26.064 0 26.088 0.192 ;
    END
  END b[250]
  PIN b[251]
    DIRECTION OUTPUT ;
    USE SIGNAL ;
    PORT
      LAYER M5 ;
        RECT  26.112 0 26.136 0.192 ;
    END
  END b[251]
  PIN b[252]
    DIRECTION OUTPUT ;
    USE SIGNAL ;
    PORT
      LAYER M5 ;
        RECT  26.16 0 26.184 0.192 ;
    END
  END b[252]
  PIN b[253]
    DIRECTION OUTPUT ;
    USE SIGNAL ;
    PORT
      LAYER M5 ;
        RECT  26.208 0 26.232 0.192 ;
    END
  END b[253]
  PIN b[254]
    DIRECTION OUTPUT ;
    USE SIGNAL ;
    PORT
      LAYER M5 ;
        RECT  26.256 0 26.28 0.192 ;
    END
  END b[254]
  PIN b[255]
    DIRECTION OUTPUT ;
    USE SIGNAL ;
    PORT
      LAYER M5 ;
        RECT  26.304 0 26.328 0.192 ;
    END
  END b[255]
  PIN b[256]
    DIRECTION OUTPUT ;
    USE SIGNAL ;
    PORT
      LAYER M5 ;
        RECT  26.352 0 26.376 0.192 ;
    END
  END b[256]
  PIN b[257]
    DIRECTION OUTPUT ;
    USE SIGNAL ;
    PORT
      LAYER M5 ;
        RECT  26.4 0 26.424 0.192 ;
    END
  END b[257]
  PIN b[258]
    DIRECTION OUTPUT ;
    USE SIGNAL ;
    PORT
      LAYER M5 ;
        RECT  26.448 0 26.472 0.192 ;
    END
  END b[258]
  PIN b[259]
    DIRECTION OUTPUT ;
    USE SIGNAL ;
    PORT
      LAYER M5 ;
        RECT  26.496 0 26.52 0.192 ;
    END
  END b[259]
  PIN b[25]
    DIRECTION OUTPUT ;
    USE SIGNAL ;
    PORT
      LAYER M5 ;
        RECT  15.264 0 15.288 0.192 ;
    END
  END b[25]
  PIN b[260]
    DIRECTION OUTPUT ;
    USE SIGNAL ;
    PORT
      LAYER M5 ;
        RECT  26.544 0 26.568 0.192 ;
    END
  END b[260]
  PIN b[261]
    DIRECTION OUTPUT ;
    USE SIGNAL ;
    PORT
      LAYER M5 ;
        RECT  26.592 0 26.616 0.192 ;
    END
  END b[261]
  PIN b[262]
    DIRECTION OUTPUT ;
    USE SIGNAL ;
    PORT
      LAYER M5 ;
        RECT  26.64 0 26.664 0.192 ;
    END
  END b[262]
  PIN b[263]
    DIRECTION OUTPUT ;
    USE SIGNAL ;
    PORT
      LAYER M5 ;
        RECT  26.688 0 26.712 0.192 ;
    END
  END b[263]
  PIN b[264]
    DIRECTION OUTPUT ;
    USE SIGNAL ;
    PORT
      LAYER M5 ;
        RECT  26.736 0 26.76 0.192 ;
    END
  END b[264]
  PIN b[265]
    DIRECTION OUTPUT ;
    USE SIGNAL ;
    PORT
      LAYER M5 ;
        RECT  26.784 0 26.808 0.192 ;
    END
  END b[265]
  PIN b[266]
    DIRECTION OUTPUT ;
    USE SIGNAL ;
    PORT
      LAYER M5 ;
        RECT  26.832 0 26.856 0.192 ;
    END
  END b[266]
  PIN b[267]
    DIRECTION OUTPUT ;
    USE SIGNAL ;
    PORT
      LAYER M5 ;
        RECT  26.88 0 26.904 0.192 ;
    END
  END b[267]
  PIN b[268]
    DIRECTION OUTPUT ;
    USE SIGNAL ;
    PORT
      LAYER M5 ;
        RECT  26.928 0 26.952 0.192 ;
    END
  END b[268]
  PIN b[269]
    DIRECTION OUTPUT ;
    USE SIGNAL ;
    PORT
      LAYER M5 ;
        RECT  26.976 0 27 0.192 ;
    END
  END b[269]
  PIN b[26]
    DIRECTION OUTPUT ;
    USE SIGNAL ;
    PORT
      LAYER M5 ;
        RECT  15.312 0 15.336 0.192 ;
    END
  END b[26]
  PIN b[270]
    DIRECTION OUTPUT ;
    USE SIGNAL ;
    PORT
      LAYER M5 ;
        RECT  27.024 0 27.048 0.192 ;
    END
  END b[270]
  PIN b[271]
    DIRECTION OUTPUT ;
    USE SIGNAL ;
    PORT
      LAYER M5 ;
        RECT  27.072 0 27.096 0.192 ;
    END
  END b[271]
  PIN b[272]
    DIRECTION OUTPUT ;
    USE SIGNAL ;
    PORT
      LAYER M5 ;
        RECT  27.12 0 27.144 0.192 ;
    END
  END b[272]
  PIN b[273]
    DIRECTION OUTPUT ;
    USE SIGNAL ;
    PORT
      LAYER M5 ;
        RECT  27.168 0 27.192 0.192 ;
    END
  END b[273]
  PIN b[274]
    DIRECTION OUTPUT ;
    USE SIGNAL ;
    PORT
      LAYER M5 ;
        RECT  27.216 0 27.24 0.192 ;
    END
  END b[274]
  PIN b[275]
    DIRECTION OUTPUT ;
    USE SIGNAL ;
    PORT
      LAYER M5 ;
        RECT  27.264 0 27.288 0.192 ;
    END
  END b[275]
  PIN b[276]
    DIRECTION OUTPUT ;
    USE SIGNAL ;
    PORT
      LAYER M5 ;
        RECT  27.312 0 27.336 0.192 ;
    END
  END b[276]
  PIN b[277]
    DIRECTION OUTPUT ;
    USE SIGNAL ;
    PORT
      LAYER M5 ;
        RECT  27.36 0 27.384 0.192 ;
    END
  END b[277]
  PIN b[278]
    DIRECTION OUTPUT ;
    USE SIGNAL ;
    PORT
      LAYER M5 ;
        RECT  27.408 0 27.432 0.192 ;
    END
  END b[278]
  PIN b[279]
    DIRECTION OUTPUT ;
    USE SIGNAL ;
    PORT
      LAYER M5 ;
        RECT  27.456 0 27.48 0.192 ;
    END
  END b[279]
  PIN b[27]
    DIRECTION OUTPUT ;
    USE SIGNAL ;
    PORT
      LAYER M5 ;
        RECT  15.36 0 15.384 0.192 ;
    END
  END b[27]
  PIN b[280]
    DIRECTION OUTPUT ;
    USE SIGNAL ;
    PORT
      LAYER M5 ;
        RECT  27.504 0 27.528 0.192 ;
    END
  END b[280]
  PIN b[281]
    DIRECTION OUTPUT ;
    USE SIGNAL ;
    PORT
      LAYER M5 ;
        RECT  27.552 0 27.576 0.192 ;
    END
  END b[281]
  PIN b[282]
    DIRECTION OUTPUT ;
    USE SIGNAL ;
    PORT
      LAYER M5 ;
        RECT  27.6 0 27.624 0.192 ;
    END
  END b[282]
  PIN b[283]
    DIRECTION OUTPUT ;
    USE SIGNAL ;
    PORT
      LAYER M5 ;
        RECT  27.648 0 27.672 0.192 ;
    END
  END b[283]
  PIN b[284]
    DIRECTION OUTPUT ;
    USE SIGNAL ;
    PORT
      LAYER M5 ;
        RECT  27.696 0 27.72 0.192 ;
    END
  END b[284]
  PIN b[285]
    DIRECTION OUTPUT ;
    USE SIGNAL ;
    PORT
      LAYER M5 ;
        RECT  27.744 0 27.768 0.192 ;
    END
  END b[285]
  PIN b[286]
    DIRECTION OUTPUT ;
    USE SIGNAL ;
    PORT
      LAYER M5 ;
        RECT  27.792 0 27.816 0.192 ;
    END
  END b[286]
  PIN b[287]
    DIRECTION OUTPUT ;
    USE SIGNAL ;
    PORT
      LAYER M5 ;
        RECT  27.84 0 27.864 0.192 ;
    END
  END b[287]
  PIN b[288]
    DIRECTION OUTPUT ;
    USE SIGNAL ;
    PORT
      LAYER M5 ;
        RECT  27.888 0 27.912 0.192 ;
    END
  END b[288]
  PIN b[289]
    DIRECTION OUTPUT ;
    USE SIGNAL ;
    PORT
      LAYER M5 ;
        RECT  27.936 0 27.96 0.192 ;
    END
  END b[289]
  PIN b[28]
    DIRECTION OUTPUT ;
    USE SIGNAL ;
    PORT
      LAYER M5 ;
        RECT  15.408 0 15.432 0.192 ;
    END
  END b[28]
  PIN b[290]
    DIRECTION OUTPUT ;
    USE SIGNAL ;
    PORT
      LAYER M5 ;
        RECT  27.984 0 28.008 0.192 ;
    END
  END b[290]
  PIN b[291]
    DIRECTION OUTPUT ;
    USE SIGNAL ;
    PORT
      LAYER M5 ;
        RECT  28.032 0 28.056 0.192 ;
    END
  END b[291]
  PIN b[292]
    DIRECTION OUTPUT ;
    USE SIGNAL ;
    PORT
      LAYER M5 ;
        RECT  28.08 0 28.104 0.192 ;
    END
  END b[292]
  PIN b[293]
    DIRECTION OUTPUT ;
    USE SIGNAL ;
    PORT
      LAYER M5 ;
        RECT  28.128 0 28.152 0.192 ;
    END
  END b[293]
  PIN b[294]
    DIRECTION OUTPUT ;
    USE SIGNAL ;
    PORT
      LAYER M5 ;
        RECT  28.176 0 28.2 0.192 ;
    END
  END b[294]
  PIN b[295]
    DIRECTION OUTPUT ;
    USE SIGNAL ;
    PORT
      LAYER M5 ;
        RECT  28.224 0 28.248 0.192 ;
    END
  END b[295]
  PIN b[296]
    DIRECTION OUTPUT ;
    USE SIGNAL ;
    PORT
      LAYER M5 ;
        RECT  28.272 0 28.296 0.192 ;
    END
  END b[296]
  PIN b[297]
    DIRECTION OUTPUT ;
    USE SIGNAL ;
    PORT
      LAYER M5 ;
        RECT  28.32 0 28.344 0.192 ;
    END
  END b[297]
  PIN b[298]
    DIRECTION OUTPUT ;
    USE SIGNAL ;
    PORT
      LAYER M5 ;
        RECT  28.368 0 28.392 0.192 ;
    END
  END b[298]
  PIN b[299]
    DIRECTION OUTPUT ;
    USE SIGNAL ;
    PORT
      LAYER M5 ;
        RECT  28.416 0 28.44 0.192 ;
    END
  END b[299]
  PIN b[29]
    DIRECTION OUTPUT ;
    USE SIGNAL ;
    PORT
      LAYER M5 ;
        RECT  15.456 0 15.48 0.192 ;
    END
  END b[29]
  PIN b[2]
    DIRECTION OUTPUT ;
    USE SIGNAL ;
    PORT
      LAYER M5 ;
        RECT  14.16 0 14.184 0.192 ;
    END
  END b[2]
  PIN b[300]
    DIRECTION OUTPUT ;
    USE SIGNAL ;
    PORT
      LAYER M5 ;
        RECT  28.464 0 28.488 0.192 ;
    END
  END b[300]
  PIN b[301]
    DIRECTION OUTPUT ;
    USE SIGNAL ;
    PORT
      LAYER M5 ;
        RECT  28.512 0 28.536 0.192 ;
    END
  END b[301]
  PIN b[302]
    DIRECTION OUTPUT ;
    USE SIGNAL ;
    PORT
      LAYER M5 ;
        RECT  28.56 0 28.584 0.192 ;
    END
  END b[302]
  PIN b[303]
    DIRECTION OUTPUT ;
    USE SIGNAL ;
    PORT
      LAYER M5 ;
        RECT  28.608 0 28.632 0.192 ;
    END
  END b[303]
  PIN b[304]
    DIRECTION OUTPUT ;
    USE SIGNAL ;
    PORT
      LAYER M5 ;
        RECT  28.656 0 28.68 0.192 ;
    END
  END b[304]
  PIN b[305]
    DIRECTION OUTPUT ;
    USE SIGNAL ;
    PORT
      LAYER M5 ;
        RECT  28.704 0 28.728 0.192 ;
    END
  END b[305]
  PIN b[306]
    DIRECTION OUTPUT ;
    USE SIGNAL ;
    PORT
      LAYER M5 ;
        RECT  28.752 0 28.776 0.192 ;
    END
  END b[306]
  PIN b[307]
    DIRECTION OUTPUT ;
    USE SIGNAL ;
    PORT
      LAYER M5 ;
        RECT  28.8 0 28.824 0.192 ;
    END
  END b[307]
  PIN b[308]
    DIRECTION OUTPUT ;
    USE SIGNAL ;
    PORT
      LAYER M5 ;
        RECT  28.848 0 28.872 0.192 ;
    END
  END b[308]
  PIN b[309]
    DIRECTION OUTPUT ;
    USE SIGNAL ;
    PORT
      LAYER M5 ;
        RECT  28.896 0 28.92 0.192 ;
    END
  END b[309]
  PIN b[30]
    DIRECTION OUTPUT ;
    USE SIGNAL ;
    PORT
      LAYER M5 ;
        RECT  15.504 0 15.528 0.192 ;
    END
  END b[30]
  PIN b[310]
    DIRECTION OUTPUT ;
    USE SIGNAL ;
    PORT
      LAYER M5 ;
        RECT  28.944 0 28.968 0.192 ;
    END
  END b[310]
  PIN b[311]
    DIRECTION OUTPUT ;
    USE SIGNAL ;
    PORT
      LAYER M5 ;
        RECT  28.992 0 29.016 0.192 ;
    END
  END b[311]
  PIN b[312]
    DIRECTION OUTPUT ;
    USE SIGNAL ;
    PORT
      LAYER M5 ;
        RECT  29.04 0 29.064 0.192 ;
    END
  END b[312]
  PIN b[313]
    DIRECTION OUTPUT ;
    USE SIGNAL ;
    PORT
      LAYER M5 ;
        RECT  29.088 0 29.112 0.192 ;
    END
  END b[313]
  PIN b[314]
    DIRECTION OUTPUT ;
    USE SIGNAL ;
    PORT
      LAYER M5 ;
        RECT  29.136 0 29.16 0.192 ;
    END
  END b[314]
  PIN b[315]
    DIRECTION OUTPUT ;
    USE SIGNAL ;
    PORT
      LAYER M5 ;
        RECT  29.184 0 29.208 0.192 ;
    END
  END b[315]
  PIN b[316]
    DIRECTION OUTPUT ;
    USE SIGNAL ;
    PORT
      LAYER M5 ;
        RECT  29.232 0 29.256 0.192 ;
    END
  END b[316]
  PIN b[317]
    DIRECTION OUTPUT ;
    USE SIGNAL ;
    PORT
      LAYER M5 ;
        RECT  29.28 0 29.304 0.192 ;
    END
  END b[317]
  PIN b[318]
    DIRECTION OUTPUT ;
    USE SIGNAL ;
    PORT
      LAYER M5 ;
        RECT  29.328 0 29.352 0.192 ;
    END
  END b[318]
  PIN b[319]
    DIRECTION OUTPUT ;
    USE SIGNAL ;
    PORT
      LAYER M5 ;
        RECT  29.376 0 29.4 0.192 ;
    END
  END b[319]
  PIN b[31]
    DIRECTION OUTPUT ;
    USE SIGNAL ;
    PORT
      LAYER M5 ;
        RECT  15.552 0 15.576 0.192 ;
    END
  END b[31]
  PIN b[320]
    DIRECTION OUTPUT ;
    USE SIGNAL ;
    PORT
      LAYER M5 ;
        RECT  29.424 0 29.448 0.192 ;
    END
  END b[320]
  PIN b[321]
    DIRECTION OUTPUT ;
    USE SIGNAL ;
    PORT
      LAYER M5 ;
        RECT  29.472 0 29.496 0.192 ;
    END
  END b[321]
  PIN b[322]
    DIRECTION OUTPUT ;
    USE SIGNAL ;
    PORT
      LAYER M5 ;
        RECT  29.52 0 29.544 0.192 ;
    END
  END b[322]
  PIN b[323]
    DIRECTION OUTPUT ;
    USE SIGNAL ;
    PORT
      LAYER M5 ;
        RECT  29.568 0 29.592 0.192 ;
    END
  END b[323]
  PIN b[324]
    DIRECTION OUTPUT ;
    USE SIGNAL ;
    PORT
      LAYER M5 ;
        RECT  29.616 0 29.64 0.192 ;
    END
  END b[324]
  PIN b[325]
    DIRECTION OUTPUT ;
    USE SIGNAL ;
    PORT
      LAYER M5 ;
        RECT  29.664 0 29.688 0.192 ;
    END
  END b[325]
  PIN b[326]
    DIRECTION OUTPUT ;
    USE SIGNAL ;
    PORT
      LAYER M5 ;
        RECT  29.712 0 29.736 0.192 ;
    END
  END b[326]
  PIN b[327]
    DIRECTION OUTPUT ;
    USE SIGNAL ;
    PORT
      LAYER M5 ;
        RECT  29.76 0 29.784 0.192 ;
    END
  END b[327]
  PIN b[328]
    DIRECTION OUTPUT ;
    USE SIGNAL ;
    PORT
      LAYER M5 ;
        RECT  29.808 0 29.832 0.192 ;
    END
  END b[328]
  PIN b[329]
    DIRECTION OUTPUT ;
    USE SIGNAL ;
    PORT
      LAYER M5 ;
        RECT  29.856 0 29.88 0.192 ;
    END
  END b[329]
  PIN b[32]
    DIRECTION OUTPUT ;
    USE SIGNAL ;
    PORT
      LAYER M5 ;
        RECT  15.6 0 15.624 0.192 ;
    END
  END b[32]
  PIN b[330]
    DIRECTION OUTPUT ;
    USE SIGNAL ;
    PORT
      LAYER M5 ;
        RECT  29.904 0 29.928 0.192 ;
    END
  END b[330]
  PIN b[331]
    DIRECTION OUTPUT ;
    USE SIGNAL ;
    PORT
      LAYER M5 ;
        RECT  29.952 0 29.976 0.192 ;
    END
  END b[331]
  PIN b[332]
    DIRECTION OUTPUT ;
    USE SIGNAL ;
    PORT
      LAYER M5 ;
        RECT  30 0 30.024 0.192 ;
    END
  END b[332]
  PIN b[333]
    DIRECTION OUTPUT ;
    USE SIGNAL ;
    PORT
      LAYER M5 ;
        RECT  30.048 0 30.072 0.192 ;
    END
  END b[333]
  PIN b[334]
    DIRECTION OUTPUT ;
    USE SIGNAL ;
    PORT
      LAYER M5 ;
        RECT  30.096 0 30.12 0.192 ;
    END
  END b[334]
  PIN b[335]
    DIRECTION OUTPUT ;
    USE SIGNAL ;
    PORT
      LAYER M5 ;
        RECT  30.144 0 30.168 0.192 ;
    END
  END b[335]
  PIN b[336]
    DIRECTION OUTPUT ;
    USE SIGNAL ;
    PORT
      LAYER M5 ;
        RECT  30.192 0 30.216 0.192 ;
    END
  END b[336]
  PIN b[337]
    DIRECTION OUTPUT ;
    USE SIGNAL ;
    PORT
      LAYER M5 ;
        RECT  30.24 0 30.264 0.192 ;
    END
  END b[337]
  PIN b[338]
    DIRECTION OUTPUT ;
    USE SIGNAL ;
    PORT
      LAYER M5 ;
        RECT  30.288 0 30.312 0.192 ;
    END
  END b[338]
  PIN b[339]
    DIRECTION OUTPUT ;
    USE SIGNAL ;
    PORT
      LAYER M5 ;
        RECT  30.336 0 30.36 0.192 ;
    END
  END b[339]
  PIN b[33]
    DIRECTION OUTPUT ;
    USE SIGNAL ;
    PORT
      LAYER M5 ;
        RECT  15.648 0 15.672 0.192 ;
    END
  END b[33]
  PIN b[340]
    DIRECTION OUTPUT ;
    USE SIGNAL ;
    PORT
      LAYER M5 ;
        RECT  30.384 0 30.408 0.192 ;
    END
  END b[340]
  PIN b[341]
    DIRECTION OUTPUT ;
    USE SIGNAL ;
    PORT
      LAYER M5 ;
        RECT  30.432 0 30.456 0.192 ;
    END
  END b[341]
  PIN b[342]
    DIRECTION OUTPUT ;
    USE SIGNAL ;
    PORT
      LAYER M5 ;
        RECT  30.48 0 30.504 0.192 ;
    END
  END b[342]
  PIN b[343]
    DIRECTION OUTPUT ;
    USE SIGNAL ;
    PORT
      LAYER M5 ;
        RECT  30.528 0 30.552 0.192 ;
    END
  END b[343]
  PIN b[344]
    DIRECTION OUTPUT ;
    USE SIGNAL ;
    PORT
      LAYER M5 ;
        RECT  30.576 0 30.6 0.192 ;
    END
  END b[344]
  PIN b[345]
    DIRECTION OUTPUT ;
    USE SIGNAL ;
    PORT
      LAYER M5 ;
        RECT  30.624 0 30.648 0.192 ;
    END
  END b[345]
  PIN b[346]
    DIRECTION OUTPUT ;
    USE SIGNAL ;
    PORT
      LAYER M5 ;
        RECT  30.672 0 30.696 0.192 ;
    END
  END b[346]
  PIN b[347]
    DIRECTION OUTPUT ;
    USE SIGNAL ;
    PORT
      LAYER M5 ;
        RECT  30.72 0 30.744 0.192 ;
    END
  END b[347]
  PIN b[348]
    DIRECTION OUTPUT ;
    USE SIGNAL ;
    PORT
      LAYER M5 ;
        RECT  30.768 0 30.792 0.192 ;
    END
  END b[348]
  PIN b[349]
    DIRECTION OUTPUT ;
    USE SIGNAL ;
    PORT
      LAYER M5 ;
        RECT  30.816 0 30.84 0.192 ;
    END
  END b[349]
  PIN b[34]
    DIRECTION OUTPUT ;
    USE SIGNAL ;
    PORT
      LAYER M5 ;
        RECT  15.696 0 15.72 0.192 ;
    END
  END b[34]
  PIN b[350]
    DIRECTION OUTPUT ;
    USE SIGNAL ;
    PORT
      LAYER M5 ;
        RECT  30.864 0 30.888 0.192 ;
    END
  END b[350]
  PIN b[351]
    DIRECTION OUTPUT ;
    USE SIGNAL ;
    PORT
      LAYER M5 ;
        RECT  30.912 0 30.936 0.192 ;
    END
  END b[351]
  PIN b[352]
    DIRECTION OUTPUT ;
    USE SIGNAL ;
    PORT
      LAYER M5 ;
        RECT  30.96 0 30.984 0.192 ;
    END
  END b[352]
  PIN b[353]
    DIRECTION OUTPUT ;
    USE SIGNAL ;
    PORT
      LAYER M5 ;
        RECT  31.008 0 31.032 0.192 ;
    END
  END b[353]
  PIN b[354]
    DIRECTION OUTPUT ;
    USE SIGNAL ;
    PORT
      LAYER M5 ;
        RECT  31.056 0 31.08 0.192 ;
    END
  END b[354]
  PIN b[355]
    DIRECTION OUTPUT ;
    USE SIGNAL ;
    PORT
      LAYER M5 ;
        RECT  31.104 0 31.128 0.192 ;
    END
  END b[355]
  PIN b[356]
    DIRECTION OUTPUT ;
    USE SIGNAL ;
    PORT
      LAYER M5 ;
        RECT  31.152 0 31.176 0.192 ;
    END
  END b[356]
  PIN b[357]
    DIRECTION OUTPUT ;
    USE SIGNAL ;
    PORT
      LAYER M5 ;
        RECT  31.2 0 31.224 0.192 ;
    END
  END b[357]
  PIN b[358]
    DIRECTION OUTPUT ;
    USE SIGNAL ;
    PORT
      LAYER M5 ;
        RECT  31.248 0 31.272 0.192 ;
    END
  END b[358]
  PIN b[359]
    DIRECTION OUTPUT ;
    USE SIGNAL ;
    PORT
      LAYER M5 ;
        RECT  31.296 0 31.32 0.192 ;
    END
  END b[359]
  PIN b[35]
    DIRECTION OUTPUT ;
    USE SIGNAL ;
    PORT
      LAYER M5 ;
        RECT  15.744 0 15.768 0.192 ;
    END
  END b[35]
  PIN b[360]
    DIRECTION OUTPUT ;
    USE SIGNAL ;
    PORT
      LAYER M5 ;
        RECT  31.344 0 31.368 0.192 ;
    END
  END b[360]
  PIN b[361]
    DIRECTION OUTPUT ;
    USE SIGNAL ;
    PORT
      LAYER M5 ;
        RECT  31.392 0 31.416 0.192 ;
    END
  END b[361]
  PIN b[362]
    DIRECTION OUTPUT ;
    USE SIGNAL ;
    PORT
      LAYER M5 ;
        RECT  31.44 0 31.464 0.192 ;
    END
  END b[362]
  PIN b[363]
    DIRECTION OUTPUT ;
    USE SIGNAL ;
    PORT
      LAYER M5 ;
        RECT  31.488 0 31.512 0.192 ;
    END
  END b[363]
  PIN b[364]
    DIRECTION OUTPUT ;
    USE SIGNAL ;
    PORT
      LAYER M5 ;
        RECT  31.536 0 31.56 0.192 ;
    END
  END b[364]
  PIN b[365]
    DIRECTION OUTPUT ;
    USE SIGNAL ;
    PORT
      LAYER M5 ;
        RECT  31.584 0 31.608 0.192 ;
    END
  END b[365]
  PIN b[366]
    DIRECTION OUTPUT ;
    USE SIGNAL ;
    PORT
      LAYER M5 ;
        RECT  31.632 0 31.656 0.192 ;
    END
  END b[366]
  PIN b[367]
    DIRECTION OUTPUT ;
    USE SIGNAL ;
    PORT
      LAYER M5 ;
        RECT  31.68 0 31.704 0.192 ;
    END
  END b[367]
  PIN b[368]
    DIRECTION OUTPUT ;
    USE SIGNAL ;
    PORT
      LAYER M5 ;
        RECT  31.728 0 31.752 0.192 ;
    END
  END b[368]
  PIN b[369]
    DIRECTION OUTPUT ;
    USE SIGNAL ;
    PORT
      LAYER M5 ;
        RECT  31.776 0 31.8 0.192 ;
    END
  END b[369]
  PIN b[36]
    DIRECTION OUTPUT ;
    USE SIGNAL ;
    PORT
      LAYER M5 ;
        RECT  15.792 0 15.816 0.192 ;
    END
  END b[36]
  PIN b[370]
    DIRECTION OUTPUT ;
    USE SIGNAL ;
    PORT
      LAYER M5 ;
        RECT  31.824 0 31.848 0.192 ;
    END
  END b[370]
  PIN b[371]
    DIRECTION OUTPUT ;
    USE SIGNAL ;
    PORT
      LAYER M5 ;
        RECT  31.872 0 31.896 0.192 ;
    END
  END b[371]
  PIN b[372]
    DIRECTION OUTPUT ;
    USE SIGNAL ;
    PORT
      LAYER M5 ;
        RECT  31.92 0 31.944 0.192 ;
    END
  END b[372]
  PIN b[373]
    DIRECTION OUTPUT ;
    USE SIGNAL ;
    PORT
      LAYER M5 ;
        RECT  31.968 0 31.992 0.192 ;
    END
  END b[373]
  PIN b[374]
    DIRECTION OUTPUT ;
    USE SIGNAL ;
    PORT
      LAYER M5 ;
        RECT  32.016 0 32.04 0.192 ;
    END
  END b[374]
  PIN b[375]
    DIRECTION OUTPUT ;
    USE SIGNAL ;
    PORT
      LAYER M5 ;
        RECT  32.064 0 32.088 0.192 ;
    END
  END b[375]
  PIN b[376]
    DIRECTION OUTPUT ;
    USE SIGNAL ;
    PORT
      LAYER M5 ;
        RECT  32.112 0 32.136 0.192 ;
    END
  END b[376]
  PIN b[377]
    DIRECTION OUTPUT ;
    USE SIGNAL ;
    PORT
      LAYER M5 ;
        RECT  32.16 0 32.184 0.192 ;
    END
  END b[377]
  PIN b[378]
    DIRECTION OUTPUT ;
    USE SIGNAL ;
    PORT
      LAYER M5 ;
        RECT  32.208 0 32.232 0.192 ;
    END
  END b[378]
  PIN b[379]
    DIRECTION OUTPUT ;
    USE SIGNAL ;
    PORT
      LAYER M5 ;
        RECT  32.256 0 32.28 0.192 ;
    END
  END b[379]
  PIN b[37]
    DIRECTION OUTPUT ;
    USE SIGNAL ;
    PORT
      LAYER M5 ;
        RECT  15.84 0 15.864 0.192 ;
    END
  END b[37]
  PIN b[380]
    DIRECTION OUTPUT ;
    USE SIGNAL ;
    PORT
      LAYER M5 ;
        RECT  32.304 0 32.328 0.192 ;
    END
  END b[380]
  PIN b[381]
    DIRECTION OUTPUT ;
    USE SIGNAL ;
    PORT
      LAYER M5 ;
        RECT  32.352 0 32.376 0.192 ;
    END
  END b[381]
  PIN b[382]
    DIRECTION OUTPUT ;
    USE SIGNAL ;
    PORT
      LAYER M5 ;
        RECT  32.4 0 32.424 0.192 ;
    END
  END b[382]
  PIN b[383]
    DIRECTION OUTPUT ;
    USE SIGNAL ;
    PORT
      LAYER M5 ;
        RECT  32.448 0 32.472 0.192 ;
    END
  END b[383]
  PIN b[384]
    DIRECTION OUTPUT ;
    USE SIGNAL ;
    PORT
      LAYER M5 ;
        RECT  32.496 0 32.52 0.192 ;
    END
  END b[384]
  PIN b[385]
    DIRECTION OUTPUT ;
    USE SIGNAL ;
    PORT
      LAYER M5 ;
        RECT  32.544 0 32.568 0.192 ;
    END
  END b[385]
  PIN b[386]
    DIRECTION OUTPUT ;
    USE SIGNAL ;
    PORT
      LAYER M5 ;
        RECT  32.592 0 32.616 0.192 ;
    END
  END b[386]
  PIN b[387]
    DIRECTION OUTPUT ;
    USE SIGNAL ;
    PORT
      LAYER M5 ;
        RECT  32.64 0 32.664 0.192 ;
    END
  END b[387]
  PIN b[388]
    DIRECTION OUTPUT ;
    USE SIGNAL ;
    PORT
      LAYER M5 ;
        RECT  32.688 0 32.712 0.192 ;
    END
  END b[388]
  PIN b[389]
    DIRECTION OUTPUT ;
    USE SIGNAL ;
    PORT
      LAYER M5 ;
        RECT  32.736 0 32.76 0.192 ;
    END
  END b[389]
  PIN b[38]
    DIRECTION OUTPUT ;
    USE SIGNAL ;
    PORT
      LAYER M5 ;
        RECT  15.888 0 15.912 0.192 ;
    END
  END b[38]
  PIN b[390]
    DIRECTION OUTPUT ;
    USE SIGNAL ;
    PORT
      LAYER M5 ;
        RECT  32.784 0 32.808 0.192 ;
    END
  END b[390]
  PIN b[391]
    DIRECTION OUTPUT ;
    USE SIGNAL ;
    PORT
      LAYER M5 ;
        RECT  32.832 0 32.856 0.192 ;
    END
  END b[391]
  PIN b[392]
    DIRECTION OUTPUT ;
    USE SIGNAL ;
    PORT
      LAYER M5 ;
        RECT  32.88 0 32.904 0.192 ;
    END
  END b[392]
  PIN b[393]
    DIRECTION OUTPUT ;
    USE SIGNAL ;
    PORT
      LAYER M5 ;
        RECT  32.928 0 32.952 0.192 ;
    END
  END b[393]
  PIN b[394]
    DIRECTION OUTPUT ;
    USE SIGNAL ;
    PORT
      LAYER M5 ;
        RECT  32.976 0 33 0.192 ;
    END
  END b[394]
  PIN b[395]
    DIRECTION OUTPUT ;
    USE SIGNAL ;
    PORT
      LAYER M5 ;
        RECT  33.024 0 33.048 0.192 ;
    END
  END b[395]
  PIN b[396]
    DIRECTION OUTPUT ;
    USE SIGNAL ;
    PORT
      LAYER M5 ;
        RECT  33.072 0 33.096 0.192 ;
    END
  END b[396]
  PIN b[397]
    DIRECTION OUTPUT ;
    USE SIGNAL ;
    PORT
      LAYER M5 ;
        RECT  33.12 0 33.144 0.192 ;
    END
  END b[397]
  PIN b[398]
    DIRECTION OUTPUT ;
    USE SIGNAL ;
    PORT
      LAYER M5 ;
        RECT  33.168 0 33.192 0.192 ;
    END
  END b[398]
  PIN b[399]
    DIRECTION OUTPUT ;
    USE SIGNAL ;
    PORT
      LAYER M5 ;
        RECT  33.216 0 33.24 0.192 ;
    END
  END b[399]
  PIN b[39]
    DIRECTION OUTPUT ;
    USE SIGNAL ;
    PORT
      LAYER M5 ;
        RECT  15.936 0 15.96 0.192 ;
    END
  END b[39]
  PIN b[3]
    DIRECTION OUTPUT ;
    USE SIGNAL ;
    PORT
      LAYER M5 ;
        RECT  14.208 0 14.232 0.192 ;
    END
  END b[3]
  PIN b[400]
    DIRECTION OUTPUT ;
    USE SIGNAL ;
    PORT
      LAYER M5 ;
        RECT  33.264 0 33.288 0.192 ;
    END
  END b[400]
  PIN b[401]
    DIRECTION OUTPUT ;
    USE SIGNAL ;
    PORT
      LAYER M5 ;
        RECT  33.312 0 33.336 0.192 ;
    END
  END b[401]
  PIN b[402]
    DIRECTION OUTPUT ;
    USE SIGNAL ;
    PORT
      LAYER M5 ;
        RECT  33.36 0 33.384 0.192 ;
    END
  END b[402]
  PIN b[403]
    DIRECTION OUTPUT ;
    USE SIGNAL ;
    PORT
      LAYER M5 ;
        RECT  33.408 0 33.432 0.192 ;
    END
  END b[403]
  PIN b[404]
    DIRECTION OUTPUT ;
    USE SIGNAL ;
    PORT
      LAYER M5 ;
        RECT  33.456 0 33.48 0.192 ;
    END
  END b[404]
  PIN b[405]
    DIRECTION OUTPUT ;
    USE SIGNAL ;
    PORT
      LAYER M5 ;
        RECT  33.504 0 33.528 0.192 ;
    END
  END b[405]
  PIN b[406]
    DIRECTION OUTPUT ;
    USE SIGNAL ;
    PORT
      LAYER M5 ;
        RECT  33.552 0 33.576 0.192 ;
    END
  END b[406]
  PIN b[407]
    DIRECTION OUTPUT ;
    USE SIGNAL ;
    PORT
      LAYER M5 ;
        RECT  33.6 0 33.624 0.192 ;
    END
  END b[407]
  PIN b[408]
    DIRECTION OUTPUT ;
    USE SIGNAL ;
    PORT
      LAYER M5 ;
        RECT  33.648 0 33.672 0.192 ;
    END
  END b[408]
  PIN b[409]
    DIRECTION OUTPUT ;
    USE SIGNAL ;
    PORT
      LAYER M5 ;
        RECT  33.696 0 33.72 0.192 ;
    END
  END b[409]
  PIN b[40]
    DIRECTION OUTPUT ;
    USE SIGNAL ;
    PORT
      LAYER M5 ;
        RECT  15.984 0 16.008 0.192 ;
    END
  END b[40]
  PIN b[410]
    DIRECTION OUTPUT ;
    USE SIGNAL ;
    PORT
      LAYER M5 ;
        RECT  33.744 0 33.768 0.192 ;
    END
  END b[410]
  PIN b[411]
    DIRECTION OUTPUT ;
    USE SIGNAL ;
    PORT
      LAYER M5 ;
        RECT  33.792 0 33.816 0.192 ;
    END
  END b[411]
  PIN b[412]
    DIRECTION OUTPUT ;
    USE SIGNAL ;
    PORT
      LAYER M5 ;
        RECT  33.84 0 33.864 0.192 ;
    END
  END b[412]
  PIN b[413]
    DIRECTION OUTPUT ;
    USE SIGNAL ;
    PORT
      LAYER M5 ;
        RECT  33.888 0 33.912 0.192 ;
    END
  END b[413]
  PIN b[414]
    DIRECTION OUTPUT ;
    USE SIGNAL ;
    PORT
      LAYER M5 ;
        RECT  33.936 0 33.96 0.192 ;
    END
  END b[414]
  PIN b[415]
    DIRECTION OUTPUT ;
    USE SIGNAL ;
    PORT
      LAYER M5 ;
        RECT  33.984 0 34.008 0.192 ;
    END
  END b[415]
  PIN b[416]
    DIRECTION OUTPUT ;
    USE SIGNAL ;
    PORT
      LAYER M5 ;
        RECT  34.032 0 34.056 0.192 ;
    END
  END b[416]
  PIN b[417]
    DIRECTION OUTPUT ;
    USE SIGNAL ;
    PORT
      LAYER M5 ;
        RECT  34.08 0 34.104 0.192 ;
    END
  END b[417]
  PIN b[418]
    DIRECTION OUTPUT ;
    USE SIGNAL ;
    PORT
      LAYER M5 ;
        RECT  34.128 0 34.152 0.192 ;
    END
  END b[418]
  PIN b[419]
    DIRECTION OUTPUT ;
    USE SIGNAL ;
    PORT
      LAYER M5 ;
        RECT  34.176 0 34.2 0.192 ;
    END
  END b[419]
  PIN b[41]
    DIRECTION OUTPUT ;
    USE SIGNAL ;
    PORT
      LAYER M5 ;
        RECT  16.032 0 16.056 0.192 ;
    END
  END b[41]
  PIN b[420]
    DIRECTION OUTPUT ;
    USE SIGNAL ;
    PORT
      LAYER M5 ;
        RECT  34.224 0 34.248 0.192 ;
    END
  END b[420]
  PIN b[421]
    DIRECTION OUTPUT ;
    USE SIGNAL ;
    PORT
      LAYER M5 ;
        RECT  34.272 0 34.296 0.192 ;
    END
  END b[421]
  PIN b[422]
    DIRECTION OUTPUT ;
    USE SIGNAL ;
    PORT
      LAYER M5 ;
        RECT  34.32 0 34.344 0.192 ;
    END
  END b[422]
  PIN b[423]
    DIRECTION OUTPUT ;
    USE SIGNAL ;
    PORT
      LAYER M5 ;
        RECT  34.368 0 34.392 0.192 ;
    END
  END b[423]
  PIN b[424]
    DIRECTION OUTPUT ;
    USE SIGNAL ;
    PORT
      LAYER M5 ;
        RECT  34.416 0 34.44 0.192 ;
    END
  END b[424]
  PIN b[425]
    DIRECTION OUTPUT ;
    USE SIGNAL ;
    PORT
      LAYER M5 ;
        RECT  34.464 0 34.488 0.192 ;
    END
  END b[425]
  PIN b[426]
    DIRECTION OUTPUT ;
    USE SIGNAL ;
    PORT
      LAYER M5 ;
        RECT  34.512 0 34.536 0.192 ;
    END
  END b[426]
  PIN b[427]
    DIRECTION OUTPUT ;
    USE SIGNAL ;
    PORT
      LAYER M5 ;
        RECT  34.56 0 34.584 0.192 ;
    END
  END b[427]
  PIN b[428]
    DIRECTION OUTPUT ;
    USE SIGNAL ;
    PORT
      LAYER M5 ;
        RECT  34.608 0 34.632 0.192 ;
    END
  END b[428]
  PIN b[429]
    DIRECTION OUTPUT ;
    USE SIGNAL ;
    PORT
      LAYER M5 ;
        RECT  34.656 0 34.68 0.192 ;
    END
  END b[429]
  PIN b[42]
    DIRECTION OUTPUT ;
    USE SIGNAL ;
    PORT
      LAYER M5 ;
        RECT  16.08 0 16.104 0.192 ;
    END
  END b[42]
  PIN b[430]
    DIRECTION OUTPUT ;
    USE SIGNAL ;
    PORT
      LAYER M5 ;
        RECT  34.704 0 34.728 0.192 ;
    END
  END b[430]
  PIN b[431]
    DIRECTION OUTPUT ;
    USE SIGNAL ;
    PORT
      LAYER M5 ;
        RECT  34.752 0 34.776 0.192 ;
    END
  END b[431]
  PIN b[432]
    DIRECTION OUTPUT ;
    USE SIGNAL ;
    PORT
      LAYER M5 ;
        RECT  34.8 0 34.824 0.192 ;
    END
  END b[432]
  PIN b[433]
    DIRECTION OUTPUT ;
    USE SIGNAL ;
    PORT
      LAYER M5 ;
        RECT  34.848 0 34.872 0.192 ;
    END
  END b[433]
  PIN b[434]
    DIRECTION OUTPUT ;
    USE SIGNAL ;
    PORT
      LAYER M5 ;
        RECT  34.896 0 34.92 0.192 ;
    END
  END b[434]
  PIN b[435]
    DIRECTION OUTPUT ;
    USE SIGNAL ;
    PORT
      LAYER M5 ;
        RECT  34.944 0 34.968 0.192 ;
    END
  END b[435]
  PIN b[436]
    DIRECTION OUTPUT ;
    USE SIGNAL ;
    PORT
      LAYER M5 ;
        RECT  34.992 0 35.016 0.192 ;
    END
  END b[436]
  PIN b[437]
    DIRECTION OUTPUT ;
    USE SIGNAL ;
    PORT
      LAYER M5 ;
        RECT  35.04 0 35.064 0.192 ;
    END
  END b[437]
  PIN b[438]
    DIRECTION OUTPUT ;
    USE SIGNAL ;
    PORT
      LAYER M5 ;
        RECT  35.088 0 35.112 0.192 ;
    END
  END b[438]
  PIN b[439]
    DIRECTION OUTPUT ;
    USE SIGNAL ;
    PORT
      LAYER M5 ;
        RECT  35.136 0 35.16 0.192 ;
    END
  END b[439]
  PIN b[43]
    DIRECTION OUTPUT ;
    USE SIGNAL ;
    PORT
      LAYER M5 ;
        RECT  16.128 0 16.152 0.192 ;
    END
  END b[43]
  PIN b[440]
    DIRECTION OUTPUT ;
    USE SIGNAL ;
    PORT
      LAYER M5 ;
        RECT  35.184 0 35.208 0.192 ;
    END
  END b[440]
  PIN b[441]
    DIRECTION OUTPUT ;
    USE SIGNAL ;
    PORT
      LAYER M5 ;
        RECT  35.232 0 35.256 0.192 ;
    END
  END b[441]
  PIN b[442]
    DIRECTION OUTPUT ;
    USE SIGNAL ;
    PORT
      LAYER M5 ;
        RECT  35.28 0 35.304 0.192 ;
    END
  END b[442]
  PIN b[443]
    DIRECTION OUTPUT ;
    USE SIGNAL ;
    PORT
      LAYER M5 ;
        RECT  35.328 0 35.352 0.192 ;
    END
  END b[443]
  PIN b[444]
    DIRECTION OUTPUT ;
    USE SIGNAL ;
    PORT
      LAYER M5 ;
        RECT  35.376 0 35.4 0.192 ;
    END
  END b[444]
  PIN b[445]
    DIRECTION OUTPUT ;
    USE SIGNAL ;
    PORT
      LAYER M5 ;
        RECT  35.424 0 35.448 0.192 ;
    END
  END b[445]
  PIN b[446]
    DIRECTION OUTPUT ;
    USE SIGNAL ;
    PORT
      LAYER M5 ;
        RECT  35.472 0 35.496 0.192 ;
    END
  END b[446]
  PIN b[447]
    DIRECTION OUTPUT ;
    USE SIGNAL ;
    PORT
      LAYER M5 ;
        RECT  35.52 0 35.544 0.192 ;
    END
  END b[447]
  PIN b[448]
    DIRECTION OUTPUT ;
    USE SIGNAL ;
    PORT
      LAYER M5 ;
        RECT  35.568 0 35.592 0.192 ;
    END
  END b[448]
  PIN b[449]
    DIRECTION OUTPUT ;
    USE SIGNAL ;
    PORT
      LAYER M5 ;
        RECT  35.616 0 35.64 0.192 ;
    END
  END b[449]
  PIN b[44]
    DIRECTION OUTPUT ;
    USE SIGNAL ;
    PORT
      LAYER M5 ;
        RECT  16.176 0 16.2 0.192 ;
    END
  END b[44]
  PIN b[450]
    DIRECTION OUTPUT ;
    USE SIGNAL ;
    PORT
      LAYER M5 ;
        RECT  35.664 0 35.688 0.192 ;
    END
  END b[450]
  PIN b[451]
    DIRECTION OUTPUT ;
    USE SIGNAL ;
    PORT
      LAYER M5 ;
        RECT  35.712 0 35.736 0.192 ;
    END
  END b[451]
  PIN b[452]
    DIRECTION OUTPUT ;
    USE SIGNAL ;
    PORT
      LAYER M5 ;
        RECT  35.76 0 35.784 0.192 ;
    END
  END b[452]
  PIN b[453]
    DIRECTION OUTPUT ;
    USE SIGNAL ;
    PORT
      LAYER M5 ;
        RECT  35.808 0 35.832 0.192 ;
    END
  END b[453]
  PIN b[454]
    DIRECTION OUTPUT ;
    USE SIGNAL ;
    PORT
      LAYER M5 ;
        RECT  35.856 0 35.88 0.192 ;
    END
  END b[454]
  PIN b[455]
    DIRECTION OUTPUT ;
    USE SIGNAL ;
    PORT
      LAYER M5 ;
        RECT  35.904 0 35.928 0.192 ;
    END
  END b[455]
  PIN b[456]
    DIRECTION OUTPUT ;
    USE SIGNAL ;
    PORT
      LAYER M5 ;
        RECT  35.952 0 35.976 0.192 ;
    END
  END b[456]
  PIN b[457]
    DIRECTION OUTPUT ;
    USE SIGNAL ;
    PORT
      LAYER M5 ;
        RECT  36 0 36.024 0.192 ;
    END
  END b[457]
  PIN b[458]
    DIRECTION OUTPUT ;
    USE SIGNAL ;
    PORT
      LAYER M5 ;
        RECT  36.048 0 36.072 0.192 ;
    END
  END b[458]
  PIN b[459]
    DIRECTION OUTPUT ;
    USE SIGNAL ;
    PORT
      LAYER M5 ;
        RECT  36.096 0 36.12 0.192 ;
    END
  END b[459]
  PIN b[45]
    DIRECTION OUTPUT ;
    USE SIGNAL ;
    PORT
      LAYER M5 ;
        RECT  16.224 0 16.248 0.192 ;
    END
  END b[45]
  PIN b[460]
    DIRECTION OUTPUT ;
    USE SIGNAL ;
    PORT
      LAYER M5 ;
        RECT  36.144 0 36.168 0.192 ;
    END
  END b[460]
  PIN b[461]
    DIRECTION OUTPUT ;
    USE SIGNAL ;
    PORT
      LAYER M5 ;
        RECT  36.192 0 36.216 0.192 ;
    END
  END b[461]
  PIN b[462]
    DIRECTION OUTPUT ;
    USE SIGNAL ;
    PORT
      LAYER M5 ;
        RECT  36.24 0 36.264 0.192 ;
    END
  END b[462]
  PIN b[463]
    DIRECTION OUTPUT ;
    USE SIGNAL ;
    PORT
      LAYER M5 ;
        RECT  36.288 0 36.312 0.192 ;
    END
  END b[463]
  PIN b[464]
    DIRECTION OUTPUT ;
    USE SIGNAL ;
    PORT
      LAYER M5 ;
        RECT  36.336 0 36.36 0.192 ;
    END
  END b[464]
  PIN b[465]
    DIRECTION OUTPUT ;
    USE SIGNAL ;
    PORT
      LAYER M5 ;
        RECT  36.384 0 36.408 0.192 ;
    END
  END b[465]
  PIN b[466]
    DIRECTION OUTPUT ;
    USE SIGNAL ;
    PORT
      LAYER M5 ;
        RECT  36.432 0 36.456 0.192 ;
    END
  END b[466]
  PIN b[467]
    DIRECTION OUTPUT ;
    USE SIGNAL ;
    PORT
      LAYER M5 ;
        RECT  36.48 0 36.504 0.192 ;
    END
  END b[467]
  PIN b[468]
    DIRECTION OUTPUT ;
    USE SIGNAL ;
    PORT
      LAYER M5 ;
        RECT  36.528 0 36.552 0.192 ;
    END
  END b[468]
  PIN b[469]
    DIRECTION OUTPUT ;
    USE SIGNAL ;
    PORT
      LAYER M5 ;
        RECT  36.576 0 36.6 0.192 ;
    END
  END b[469]
  PIN b[46]
    DIRECTION OUTPUT ;
    USE SIGNAL ;
    PORT
      LAYER M5 ;
        RECT  16.272 0 16.296 0.192 ;
    END
  END b[46]
  PIN b[470]
    DIRECTION OUTPUT ;
    USE SIGNAL ;
    PORT
      LAYER M5 ;
        RECT  36.624 0 36.648 0.192 ;
    END
  END b[470]
  PIN b[471]
    DIRECTION OUTPUT ;
    USE SIGNAL ;
    PORT
      LAYER M5 ;
        RECT  36.672 0 36.696 0.192 ;
    END
  END b[471]
  PIN b[472]
    DIRECTION OUTPUT ;
    USE SIGNAL ;
    PORT
      LAYER M5 ;
        RECT  36.72 0 36.744 0.192 ;
    END
  END b[472]
  PIN b[473]
    DIRECTION OUTPUT ;
    USE SIGNAL ;
    PORT
      LAYER M5 ;
        RECT  36.768 0 36.792 0.192 ;
    END
  END b[473]
  PIN b[474]
    DIRECTION OUTPUT ;
    USE SIGNAL ;
    PORT
      LAYER M5 ;
        RECT  36.816 0 36.84 0.192 ;
    END
  END b[474]
  PIN b[475]
    DIRECTION OUTPUT ;
    USE SIGNAL ;
    PORT
      LAYER M5 ;
        RECT  36.864 0 36.888 0.192 ;
    END
  END b[475]
  PIN b[476]
    DIRECTION OUTPUT ;
    USE SIGNAL ;
    PORT
      LAYER M5 ;
        RECT  36.912 0 36.936 0.192 ;
    END
  END b[476]
  PIN b[477]
    DIRECTION OUTPUT ;
    USE SIGNAL ;
    PORT
      LAYER M5 ;
        RECT  36.96 0 36.984 0.192 ;
    END
  END b[477]
  PIN b[478]
    DIRECTION OUTPUT ;
    USE SIGNAL ;
    PORT
      LAYER M5 ;
        RECT  37.008 0 37.032 0.192 ;
    END
  END b[478]
  PIN b[479]
    DIRECTION OUTPUT ;
    USE SIGNAL ;
    PORT
      LAYER M5 ;
        RECT  37.056 0 37.08 0.192 ;
    END
  END b[479]
  PIN b[47]
    DIRECTION OUTPUT ;
    USE SIGNAL ;
    PORT
      LAYER M5 ;
        RECT  16.32 0 16.344 0.192 ;
    END
  END b[47]
  PIN b[480]
    DIRECTION OUTPUT ;
    USE SIGNAL ;
    PORT
      LAYER M5 ;
        RECT  37.104 0 37.128 0.192 ;
    END
  END b[480]
  PIN b[481]
    DIRECTION OUTPUT ;
    USE SIGNAL ;
    PORT
      LAYER M5 ;
        RECT  37.152 0 37.176 0.192 ;
    END
  END b[481]
  PIN b[482]
    DIRECTION OUTPUT ;
    USE SIGNAL ;
    PORT
      LAYER M5 ;
        RECT  37.2 0 37.224 0.192 ;
    END
  END b[482]
  PIN b[483]
    DIRECTION OUTPUT ;
    USE SIGNAL ;
    PORT
      LAYER M5 ;
        RECT  37.248 0 37.272 0.192 ;
    END
  END b[483]
  PIN b[484]
    DIRECTION OUTPUT ;
    USE SIGNAL ;
    PORT
      LAYER M5 ;
        RECT  37.296 0 37.32 0.192 ;
    END
  END b[484]
  PIN b[485]
    DIRECTION OUTPUT ;
    USE SIGNAL ;
    PORT
      LAYER M5 ;
        RECT  37.344 0 37.368 0.192 ;
    END
  END b[485]
  PIN b[486]
    DIRECTION OUTPUT ;
    USE SIGNAL ;
    PORT
      LAYER M5 ;
        RECT  37.392 0 37.416 0.192 ;
    END
  END b[486]
  PIN b[487]
    DIRECTION OUTPUT ;
    USE SIGNAL ;
    PORT
      LAYER M5 ;
        RECT  37.44 0 37.464 0.192 ;
    END
  END b[487]
  PIN b[488]
    DIRECTION OUTPUT ;
    USE SIGNAL ;
    PORT
      LAYER M5 ;
        RECT  37.488 0 37.512 0.192 ;
    END
  END b[488]
  PIN b[489]
    DIRECTION OUTPUT ;
    USE SIGNAL ;
    PORT
      LAYER M5 ;
        RECT  37.536 0 37.56 0.192 ;
    END
  END b[489]
  PIN b[48]
    DIRECTION OUTPUT ;
    USE SIGNAL ;
    PORT
      LAYER M5 ;
        RECT  16.368 0 16.392 0.192 ;
    END
  END b[48]
  PIN b[490]
    DIRECTION OUTPUT ;
    USE SIGNAL ;
    PORT
      LAYER M5 ;
        RECT  37.584 0 37.608 0.192 ;
    END
  END b[490]
  PIN b[491]
    DIRECTION OUTPUT ;
    USE SIGNAL ;
    PORT
      LAYER M5 ;
        RECT  37.632 0 37.656 0.192 ;
    END
  END b[491]
  PIN b[492]
    DIRECTION OUTPUT ;
    USE SIGNAL ;
    PORT
      LAYER M5 ;
        RECT  37.68 0 37.704 0.192 ;
    END
  END b[492]
  PIN b[493]
    DIRECTION OUTPUT ;
    USE SIGNAL ;
    PORT
      LAYER M5 ;
        RECT  37.728 0 37.752 0.192 ;
    END
  END b[493]
  PIN b[494]
    DIRECTION OUTPUT ;
    USE SIGNAL ;
    PORT
      LAYER M5 ;
        RECT  37.776 0 37.8 0.192 ;
    END
  END b[494]
  PIN b[495]
    DIRECTION OUTPUT ;
    USE SIGNAL ;
    PORT
      LAYER M5 ;
        RECT  37.824 0 37.848 0.192 ;
    END
  END b[495]
  PIN b[496]
    DIRECTION OUTPUT ;
    USE SIGNAL ;
    PORT
      LAYER M5 ;
        RECT  37.872 0 37.896 0.192 ;
    END
  END b[496]
  PIN b[497]
    DIRECTION OUTPUT ;
    USE SIGNAL ;
    PORT
      LAYER M5 ;
        RECT  37.92 0 37.944 0.192 ;
    END
  END b[497]
  PIN b[498]
    DIRECTION OUTPUT ;
    USE SIGNAL ;
    PORT
      LAYER M5 ;
        RECT  37.968 0 37.992 0.192 ;
    END
  END b[498]
  PIN b[499]
    DIRECTION OUTPUT ;
    USE SIGNAL ;
    PORT
      LAYER M5 ;
        RECT  38.016 0 38.04 0.192 ;
    END
  END b[499]
  PIN b[49]
    DIRECTION OUTPUT ;
    USE SIGNAL ;
    PORT
      LAYER M5 ;
        RECT  16.416 0 16.44 0.192 ;
    END
  END b[49]
  PIN b[4]
    DIRECTION OUTPUT ;
    USE SIGNAL ;
    PORT
      LAYER M5 ;
        RECT  14.256 0 14.28 0.192 ;
    END
  END b[4]
  PIN b[500]
    DIRECTION OUTPUT ;
    USE SIGNAL ;
    PORT
      LAYER M5 ;
        RECT  38.064 0 38.088 0.192 ;
    END
  END b[500]
  PIN b[501]
    DIRECTION OUTPUT ;
    USE SIGNAL ;
    PORT
      LAYER M5 ;
        RECT  38.112 0 38.136 0.192 ;
    END
  END b[501]
  PIN b[502]
    DIRECTION OUTPUT ;
    USE SIGNAL ;
    PORT
      LAYER M5 ;
        RECT  38.16 0 38.184 0.192 ;
    END
  END b[502]
  PIN b[503]
    DIRECTION OUTPUT ;
    USE SIGNAL ;
    PORT
      LAYER M5 ;
        RECT  38.208 0 38.232 0.192 ;
    END
  END b[503]
  PIN b[504]
    DIRECTION OUTPUT ;
    USE SIGNAL ;
    PORT
      LAYER M5 ;
        RECT  38.256 0 38.28 0.192 ;
    END
  END b[504]
  PIN b[505]
    DIRECTION OUTPUT ;
    USE SIGNAL ;
    PORT
      LAYER M5 ;
        RECT  38.304 0 38.328 0.192 ;
    END
  END b[505]
  PIN b[506]
    DIRECTION OUTPUT ;
    USE SIGNAL ;
    PORT
      LAYER M5 ;
        RECT  38.352 0 38.376 0.192 ;
    END
  END b[506]
  PIN b[507]
    DIRECTION OUTPUT ;
    USE SIGNAL ;
    PORT
      LAYER M5 ;
        RECT  38.4 0 38.424 0.192 ;
    END
  END b[507]
  PIN b[508]
    DIRECTION OUTPUT ;
    USE SIGNAL ;
    PORT
      LAYER M5 ;
        RECT  38.448 0 38.472 0.192 ;
    END
  END b[508]
  PIN b[509]
    DIRECTION OUTPUT ;
    USE SIGNAL ;
    PORT
      LAYER M5 ;
        RECT  38.496 0 38.52 0.192 ;
    END
  END b[509]
  PIN b[50]
    DIRECTION OUTPUT ;
    USE SIGNAL ;
    PORT
      LAYER M5 ;
        RECT  16.464 0 16.488 0.192 ;
    END
  END b[50]
  PIN b[510]
    DIRECTION OUTPUT ;
    USE SIGNAL ;
    PORT
      LAYER M5 ;
        RECT  38.544 0 38.568 0.192 ;
    END
  END b[510]
  PIN b[511]
    DIRECTION OUTPUT ;
    USE SIGNAL ;
    PORT
      LAYER M5 ;
        RECT  38.592 0 38.616 0.192 ;
    END
  END b[511]
  PIN b[512]
    DIRECTION OUTPUT ;
    USE SIGNAL ;
    PORT
      LAYER M5 ;
        RECT  38.64 0 38.664 0.192 ;
    END
  END b[512]
  PIN b[51]
    DIRECTION OUTPUT ;
    USE SIGNAL ;
    PORT
      LAYER M5 ;
        RECT  16.512 0 16.536 0.192 ;
    END
  END b[51]
  PIN b[52]
    DIRECTION OUTPUT ;
    USE SIGNAL ;
    PORT
      LAYER M5 ;
        RECT  16.56 0 16.584 0.192 ;
    END
  END b[52]
  PIN b[53]
    DIRECTION OUTPUT ;
    USE SIGNAL ;
    PORT
      LAYER M5 ;
        RECT  16.608 0 16.632 0.192 ;
    END
  END b[53]
  PIN b[54]
    DIRECTION OUTPUT ;
    USE SIGNAL ;
    PORT
      LAYER M5 ;
        RECT  16.656 0 16.68 0.192 ;
    END
  END b[54]
  PIN b[55]
    DIRECTION OUTPUT ;
    USE SIGNAL ;
    PORT
      LAYER M5 ;
        RECT  16.704 0 16.728 0.192 ;
    END
  END b[55]
  PIN b[56]
    DIRECTION OUTPUT ;
    USE SIGNAL ;
    PORT
      LAYER M5 ;
        RECT  16.752 0 16.776 0.192 ;
    END
  END b[56]
  PIN b[57]
    DIRECTION OUTPUT ;
    USE SIGNAL ;
    PORT
      LAYER M5 ;
        RECT  16.8 0 16.824 0.192 ;
    END
  END b[57]
  PIN b[58]
    DIRECTION OUTPUT ;
    USE SIGNAL ;
    PORT
      LAYER M5 ;
        RECT  16.848 0 16.872 0.192 ;
    END
  END b[58]
  PIN b[59]
    DIRECTION OUTPUT ;
    USE SIGNAL ;
    PORT
      LAYER M5 ;
        RECT  16.896 0 16.92 0.192 ;
    END
  END b[59]
  PIN b[5]
    DIRECTION OUTPUT ;
    USE SIGNAL ;
    PORT
      LAYER M5 ;
        RECT  14.304 0 14.328 0.192 ;
    END
  END b[5]
  PIN b[60]
    DIRECTION OUTPUT ;
    USE SIGNAL ;
    PORT
      LAYER M5 ;
        RECT  16.944 0 16.968 0.192 ;
    END
  END b[60]
  PIN b[61]
    DIRECTION OUTPUT ;
    USE SIGNAL ;
    PORT
      LAYER M5 ;
        RECT  16.992 0 17.016 0.192 ;
    END
  END b[61]
  PIN b[62]
    DIRECTION OUTPUT ;
    USE SIGNAL ;
    PORT
      LAYER M5 ;
        RECT  17.04 0 17.064 0.192 ;
    END
  END b[62]
  PIN b[63]
    DIRECTION OUTPUT ;
    USE SIGNAL ;
    PORT
      LAYER M5 ;
        RECT  17.088 0 17.112 0.192 ;
    END
  END b[63]
  PIN b[64]
    DIRECTION OUTPUT ;
    USE SIGNAL ;
    PORT
      LAYER M5 ;
        RECT  17.136 0 17.16 0.192 ;
    END
  END b[64]
  PIN b[65]
    DIRECTION OUTPUT ;
    USE SIGNAL ;
    PORT
      LAYER M5 ;
        RECT  17.184 0 17.208 0.192 ;
    END
  END b[65]
  PIN b[66]
    DIRECTION OUTPUT ;
    USE SIGNAL ;
    PORT
      LAYER M5 ;
        RECT  17.232 0 17.256 0.192 ;
    END
  END b[66]
  PIN b[67]
    DIRECTION OUTPUT ;
    USE SIGNAL ;
    PORT
      LAYER M5 ;
        RECT  17.28 0 17.304 0.192 ;
    END
  END b[67]
  PIN b[68]
    DIRECTION OUTPUT ;
    USE SIGNAL ;
    PORT
      LAYER M5 ;
        RECT  17.328 0 17.352 0.192 ;
    END
  END b[68]
  PIN b[69]
    DIRECTION OUTPUT ;
    USE SIGNAL ;
    PORT
      LAYER M5 ;
        RECT  17.376 0 17.4 0.192 ;
    END
  END b[69]
  PIN b[6]
    DIRECTION OUTPUT ;
    USE SIGNAL ;
    PORT
      LAYER M5 ;
        RECT  14.352 0 14.376 0.192 ;
    END
  END b[6]
  PIN b[70]
    DIRECTION OUTPUT ;
    USE SIGNAL ;
    PORT
      LAYER M5 ;
        RECT  17.424 0 17.448 0.192 ;
    END
  END b[70]
  PIN b[71]
    DIRECTION OUTPUT ;
    USE SIGNAL ;
    PORT
      LAYER M5 ;
        RECT  17.472 0 17.496 0.192 ;
    END
  END b[71]
  PIN b[72]
    DIRECTION OUTPUT ;
    USE SIGNAL ;
    PORT
      LAYER M5 ;
        RECT  17.52 0 17.544 0.192 ;
    END
  END b[72]
  PIN b[73]
    DIRECTION OUTPUT ;
    USE SIGNAL ;
    PORT
      LAYER M5 ;
        RECT  17.568 0 17.592 0.192 ;
    END
  END b[73]
  PIN b[74]
    DIRECTION OUTPUT ;
    USE SIGNAL ;
    PORT
      LAYER M5 ;
        RECT  17.616 0 17.64 0.192 ;
    END
  END b[74]
  PIN b[75]
    DIRECTION OUTPUT ;
    USE SIGNAL ;
    PORT
      LAYER M5 ;
        RECT  17.664 0 17.688 0.192 ;
    END
  END b[75]
  PIN b[76]
    DIRECTION OUTPUT ;
    USE SIGNAL ;
    PORT
      LAYER M5 ;
        RECT  17.712 0 17.736 0.192 ;
    END
  END b[76]
  PIN b[77]
    DIRECTION OUTPUT ;
    USE SIGNAL ;
    PORT
      LAYER M5 ;
        RECT  17.76 0 17.784 0.192 ;
    END
  END b[77]
  PIN b[78]
    DIRECTION OUTPUT ;
    USE SIGNAL ;
    PORT
      LAYER M5 ;
        RECT  17.808 0 17.832 0.192 ;
    END
  END b[78]
  PIN b[79]
    DIRECTION OUTPUT ;
    USE SIGNAL ;
    PORT
      LAYER M5 ;
        RECT  17.856 0 17.88 0.192 ;
    END
  END b[79]
  PIN b[7]
    DIRECTION OUTPUT ;
    USE SIGNAL ;
    PORT
      LAYER M5 ;
        RECT  14.4 0 14.424 0.192 ;
    END
  END b[7]
  PIN b[80]
    DIRECTION OUTPUT ;
    USE SIGNAL ;
    PORT
      LAYER M5 ;
        RECT  17.904 0 17.928 0.192 ;
    END
  END b[80]
  PIN b[81]
    DIRECTION OUTPUT ;
    USE SIGNAL ;
    PORT
      LAYER M5 ;
        RECT  17.952 0 17.976 0.192 ;
    END
  END b[81]
  PIN b[82]
    DIRECTION OUTPUT ;
    USE SIGNAL ;
    PORT
      LAYER M5 ;
        RECT  18 0 18.024 0.192 ;
    END
  END b[82]
  PIN b[83]
    DIRECTION OUTPUT ;
    USE SIGNAL ;
    PORT
      LAYER M5 ;
        RECT  18.048 0 18.072 0.192 ;
    END
  END b[83]
  PIN b[84]
    DIRECTION OUTPUT ;
    USE SIGNAL ;
    PORT
      LAYER M5 ;
        RECT  18.096 0 18.12 0.192 ;
    END
  END b[84]
  PIN b[85]
    DIRECTION OUTPUT ;
    USE SIGNAL ;
    PORT
      LAYER M5 ;
        RECT  18.144 0 18.168 0.192 ;
    END
  END b[85]
  PIN b[86]
    DIRECTION OUTPUT ;
    USE SIGNAL ;
    PORT
      LAYER M5 ;
        RECT  18.192 0 18.216 0.192 ;
    END
  END b[86]
  PIN b[87]
    DIRECTION OUTPUT ;
    USE SIGNAL ;
    PORT
      LAYER M5 ;
        RECT  18.24 0 18.264 0.192 ;
    END
  END b[87]
  PIN b[88]
    DIRECTION OUTPUT ;
    USE SIGNAL ;
    PORT
      LAYER M5 ;
        RECT  18.288 0 18.312 0.192 ;
    END
  END b[88]
  PIN b[89]
    DIRECTION OUTPUT ;
    USE SIGNAL ;
    PORT
      LAYER M5 ;
        RECT  18.336 0 18.36 0.192 ;
    END
  END b[89]
  PIN b[8]
    DIRECTION OUTPUT ;
    USE SIGNAL ;
    PORT
      LAYER M5 ;
        RECT  14.448 0 14.472 0.192 ;
    END
  END b[8]
  PIN b[90]
    DIRECTION OUTPUT ;
    USE SIGNAL ;
    PORT
      LAYER M5 ;
        RECT  18.384 0 18.408 0.192 ;
    END
  END b[90]
  PIN b[91]
    DIRECTION OUTPUT ;
    USE SIGNAL ;
    PORT
      LAYER M5 ;
        RECT  18.432 0 18.456 0.192 ;
    END
  END b[91]
  PIN b[92]
    DIRECTION OUTPUT ;
    USE SIGNAL ;
    PORT
      LAYER M5 ;
        RECT  18.48 0 18.504 0.192 ;
    END
  END b[92]
  PIN b[93]
    DIRECTION OUTPUT ;
    USE SIGNAL ;
    PORT
      LAYER M5 ;
        RECT  18.528 0 18.552 0.192 ;
    END
  END b[93]
  PIN b[94]
    DIRECTION OUTPUT ;
    USE SIGNAL ;
    PORT
      LAYER M5 ;
        RECT  18.576 0 18.6 0.192 ;
    END
  END b[94]
  PIN b[95]
    DIRECTION OUTPUT ;
    USE SIGNAL ;
    PORT
      LAYER M5 ;
        RECT  18.624 0 18.648 0.192 ;
    END
  END b[95]
  PIN b[96]
    DIRECTION OUTPUT ;
    USE SIGNAL ;
    PORT
      LAYER M5 ;
        RECT  18.672 0 18.696 0.192 ;
    END
  END b[96]
  PIN b[97]
    DIRECTION OUTPUT ;
    USE SIGNAL ;
    PORT
      LAYER M5 ;
        RECT  18.72 0 18.744 0.192 ;
    END
  END b[97]
  PIN b[98]
    DIRECTION OUTPUT ;
    USE SIGNAL ;
    PORT
      LAYER M5 ;
        RECT  18.768 0 18.792 0.192 ;
    END
  END b[98]
  PIN b[99]
    DIRECTION OUTPUT ;
    USE SIGNAL ;
    PORT
      LAYER M5 ;
        RECT  18.816 0 18.84 0.192 ;
    END
  END b[99]
  PIN b[9]
    DIRECTION OUTPUT ;
    USE SIGNAL ;
    PORT
      LAYER M5 ;
        RECT  14.496 0 14.52 0.192 ;
    END
  END b[9]
  PIN ck[0]
    DIRECTION INPUT ;
    USE SIGNAL ;
    PORT
      LAYER M4 ;
        RECT  39.096 0.912 39.288 0.936 ;
    END
  END ck[0]
  PIN rst[0]
    DIRECTION INPUT ;
    USE SIGNAL ;
    PORT
      LAYER M4 ;
        RECT  39.096 0.624 39.288 0.648 ;
    END
  END rst[0]
  PIN VDD
    DIRECTION INOUT ;
    USE POWER ;
    PORT
      LAYER M7 ;
        RECT  38.656 0.531 38.944 76.959 ;
        RECT  27.856 0.531 28.144 76.959 ;
        RECT  17.056 0.531 17.344 76.959 ;
        RECT  6.256 0.531 6.544 76.959 ;
      LAYER M6 ;
        RECT  0 71.772 0.032 72.06 ;
        RECT  0 66.372 0.032 66.66 ;
        RECT  0 60.972 0.032 61.26 ;
        RECT  0 55.572 0.032 55.86 ;
        RECT  0 50.172 0.032 50.46 ;
        RECT  0 44.772 0.032 45.06 ;
        RECT  0 39.372 0.032 39.66 ;
        RECT  0 33.972 0.032 34.26 ;
        RECT  0 28.572 0.032 28.86 ;
        RECT  0 23.172 0.032 23.46 ;
        RECT  0 17.772 0.032 18.06 ;
        RECT  0 12.372 0.032 12.66 ;
        RECT  0 6.972 0.032 7.26 ;
        RECT  0 1.572 0.032 1.86 ;
      LAYER M2 ;
        RECT  0 76.941 0.018 76.959 ;
        RECT  0 76.401 0.018 76.419 ;
        RECT  0 75.861 0.018 75.879 ;
        RECT  0 75.321 0.018 75.339 ;
        RECT  0 74.781 0.018 74.799 ;
        RECT  0 74.241 0.018 74.259 ;
        RECT  0 73.701 0.018 73.719 ;
        RECT  0 73.161 0.018 73.179 ;
        RECT  0 72.621 0.018 72.639 ;
        RECT  0 72.081 0.018 72.099 ;
        RECT  0 71.541 0.018 71.559 ;
        RECT  0 71.001 0.018 71.019 ;
        RECT  0 70.461 0.018 70.479 ;
        RECT  0 69.921 0.018 69.939 ;
        RECT  0 69.381 0.018 69.399 ;
        RECT  0 68.841 0.018 68.859 ;
        RECT  0 68.301 0.018 68.319 ;
        RECT  0 67.761 0.018 67.779 ;
        RECT  0 67.221 0.018 67.239 ;
        RECT  0 66.681 0.018 66.699 ;
        RECT  0 66.141 0.018 66.159 ;
        RECT  0 65.601 0.018 65.619 ;
        RECT  0 65.061 0.018 65.079 ;
        RECT  0 64.521 0.018 64.539 ;
        RECT  0 63.981 0.018 63.999 ;
        RECT  0 63.441 0.018 63.459 ;
        RECT  0 62.901 0.018 62.919 ;
        RECT  0 62.361 0.018 62.379 ;
        RECT  0 61.821 0.018 61.839 ;
        RECT  0 61.281 0.018 61.299 ;
        RECT  0 60.741 0.018 60.759 ;
        RECT  0 60.201 0.018 60.219 ;
        RECT  0 59.661 0.018 59.679 ;
        RECT  0 59.121 0.018 59.139 ;
        RECT  0 58.581 0.018 58.599 ;
        RECT  0 58.041 0.018 58.059 ;
        RECT  0 57.501 0.018 57.519 ;
        RECT  0 56.961 0.018 56.979 ;
        RECT  0 56.421 0.018 56.439 ;
        RECT  0 55.881 0.018 55.899 ;
        RECT  0 55.341 0.018 55.359 ;
        RECT  0 54.801 0.018 54.819 ;
        RECT  0 54.261 0.018 54.279 ;
        RECT  0 53.721 0.018 53.739 ;
        RECT  0 53.181 0.018 53.199 ;
        RECT  0 52.641 0.018 52.659 ;
        RECT  0 52.101 0.018 52.119 ;
        RECT  0 51.561 0.018 51.579 ;
        RECT  0 51.021 0.018 51.039 ;
        RECT  0 50.481 0.018 50.499 ;
        RECT  0 49.941 0.018 49.959 ;
        RECT  0 49.401 0.018 49.419 ;
        RECT  0 48.861 0.018 48.879 ;
        RECT  0 48.321 0.018 48.339 ;
        RECT  0 47.781 0.018 47.799 ;
        RECT  0 47.241 0.018 47.259 ;
        RECT  0 46.701 0.018 46.719 ;
        RECT  0 46.161 0.018 46.179 ;
        RECT  0 45.621 0.018 45.639 ;
        RECT  0 45.081 0.018 45.099 ;
        RECT  0 44.541 0.018 44.559 ;
        RECT  0 44.001 0.018 44.019 ;
        RECT  0 43.461 0.018 43.479 ;
        RECT  0 42.921 0.018 42.939 ;
        RECT  0 42.381 0.018 42.399 ;
        RECT  0 41.841 0.018 41.859 ;
        RECT  0 41.301 0.018 41.319 ;
        RECT  0 40.761 0.018 40.779 ;
        RECT  0 40.221 0.018 40.239 ;
        RECT  0 39.681 0.018 39.699 ;
        RECT  0 39.141 0.018 39.159 ;
        RECT  0 38.601 0.018 38.619 ;
        RECT  0 38.061 0.018 38.079 ;
        RECT  0 37.521 0.018 37.539 ;
        RECT  0 36.981 0.018 36.999 ;
        RECT  0 36.441 0.018 36.459 ;
        RECT  0 35.901 0.018 35.919 ;
        RECT  0 35.361 0.018 35.379 ;
        RECT  0 34.821 0.018 34.839 ;
        RECT  0 34.281 0.018 34.299 ;
        RECT  0 33.741 0.018 33.759 ;
        RECT  0 33.201 0.018 33.219 ;
        RECT  0 32.661 0.018 32.679 ;
        RECT  0 32.121 0.018 32.139 ;
        RECT  0 31.581 0.018 31.599 ;
        RECT  0 31.041 0.018 31.059 ;
        RECT  0 30.501 0.018 30.519 ;
        RECT  0 29.961 0.018 29.979 ;
        RECT  0 29.421 0.018 29.439 ;
        RECT  0 28.881 0.018 28.899 ;
        RECT  0 28.341 0.018 28.359 ;
        RECT  0 27.801 0.018 27.819 ;
        RECT  0 27.261 0.018 27.279 ;
        RECT  0 26.721 0.018 26.739 ;
        RECT  0 26.181 0.018 26.199 ;
        RECT  0 25.641 0.018 25.659 ;
        RECT  0 25.101 0.018 25.119 ;
        RECT  0 24.561 0.018 24.579 ;
        RECT  0 24.021 0.018 24.039 ;
        RECT  0 23.481 0.018 23.499 ;
        RECT  0 22.941 0.018 22.959 ;
        RECT  0 22.401 0.018 22.419 ;
        RECT  0 21.861 0.018 21.879 ;
        RECT  0 21.321 0.018 21.339 ;
        RECT  0 20.781 0.018 20.799 ;
        RECT  0 20.241 0.018 20.259 ;
        RECT  0 19.701 0.018 19.719 ;
        RECT  0 19.161 0.018 19.179 ;
        RECT  0 18.621 0.018 18.639 ;
        RECT  0 18.081 0.018 18.099 ;
        RECT  0 17.541 0.018 17.559 ;
        RECT  0 17.001 0.018 17.019 ;
        RECT  0 16.461 0.018 16.479 ;
        RECT  0 15.921 0.018 15.939 ;
        RECT  0 15.381 0.018 15.399 ;
        RECT  0 14.841 0.018 14.859 ;
        RECT  0 14.301 0.018 14.319 ;
        RECT  0 13.761 0.018 13.779 ;
        RECT  0 13.221 0.018 13.239 ;
        RECT  0 12.681 0.018 12.699 ;
        RECT  0 12.141 0.018 12.159 ;
        RECT  0 11.601 0.018 11.619 ;
        RECT  0 11.061 0.018 11.079 ;
        RECT  0 10.521 0.018 10.539 ;
        RECT  0 9.981 0.018 9.999 ;
        RECT  0 9.441 0.018 9.459 ;
        RECT  0 8.901 0.018 8.919 ;
        RECT  0 8.361 0.018 8.379 ;
        RECT  0 7.821 0.018 7.839 ;
        RECT  0 7.281 0.018 7.299 ;
        RECT  0 6.741 0.018 6.759 ;
        RECT  0 6.201 0.018 6.219 ;
        RECT  0 5.661 0.018 5.679 ;
        RECT  0 5.121 0.018 5.139 ;
        RECT  0 4.581 0.018 4.599 ;
        RECT  0 4.041 0.018 4.059 ;
        RECT  0 3.501 0.018 3.519 ;
        RECT  0 2.961 0.018 2.979 ;
        RECT  0 2.421 0.018 2.439 ;
        RECT  0 1.881 0.018 1.899 ;
        RECT  0 1.341 0.018 1.359 ;
        RECT  0 0.801 0.018 0.819 ;
      LAYER M1 ;
        RECT  0 76.941 0.018 76.959 ;
        RECT  0 76.401 0.018 76.419 ;
        RECT  0 75.861 0.018 75.879 ;
        RECT  0 75.321 0.018 75.339 ;
        RECT  0 74.781 0.018 74.799 ;
        RECT  0 74.241 0.018 74.259 ;
        RECT  0 73.701 0.018 73.719 ;
        RECT  0 73.161 0.018 73.179 ;
        RECT  0 72.621 0.018 72.639 ;
        RECT  0 72.081 0.018 72.099 ;
        RECT  0 71.541 0.018 71.559 ;
        RECT  0 71.001 0.018 71.019 ;
        RECT  0 70.461 0.018 70.479 ;
        RECT  0 69.921 0.018 69.939 ;
        RECT  0 69.381 0.018 69.399 ;
        RECT  0 68.841 0.018 68.859 ;
        RECT  0 68.301 0.018 68.319 ;
        RECT  0 67.761 0.018 67.779 ;
        RECT  0 67.221 0.018 67.239 ;
        RECT  0 66.681 0.018 66.699 ;
        RECT  0 66.141 0.018 66.159 ;
        RECT  0 65.601 0.018 65.619 ;
        RECT  0 65.061 0.018 65.079 ;
        RECT  0 64.521 0.018 64.539 ;
        RECT  0 63.981 0.018 63.999 ;
        RECT  0 63.441 0.018 63.459 ;
        RECT  0 62.901 0.018 62.919 ;
        RECT  0 62.361 0.018 62.379 ;
        RECT  0 61.821 0.018 61.839 ;
        RECT  0 61.281 0.018 61.299 ;
        RECT  0 60.741 0.018 60.759 ;
        RECT  0 60.201 0.018 60.219 ;
        RECT  0 59.661 0.018 59.679 ;
        RECT  0 59.121 0.018 59.139 ;
        RECT  0 58.581 0.018 58.599 ;
        RECT  0 58.041 0.018 58.059 ;
        RECT  0 57.501 0.018 57.519 ;
        RECT  0 56.961 0.018 56.979 ;
        RECT  0 56.421 0.018 56.439 ;
        RECT  0 55.881 0.018 55.899 ;
        RECT  0 55.341 0.018 55.359 ;
        RECT  0 54.801 0.018 54.819 ;
        RECT  0 54.261 0.018 54.279 ;
        RECT  0 53.721 0.018 53.739 ;
        RECT  0 53.181 0.018 53.199 ;
        RECT  0 52.641 0.018 52.659 ;
        RECT  0 52.101 0.018 52.119 ;
        RECT  0 51.561 0.018 51.579 ;
        RECT  0 51.021 0.018 51.039 ;
        RECT  0 50.481 0.018 50.499 ;
        RECT  0 49.941 0.018 49.959 ;
        RECT  0 49.401 0.018 49.419 ;
        RECT  0 48.861 0.018 48.879 ;
        RECT  0 48.321 0.018 48.339 ;
        RECT  0 47.781 0.018 47.799 ;
        RECT  0 47.241 0.018 47.259 ;
        RECT  0 46.701 0.018 46.719 ;
        RECT  0 46.161 0.018 46.179 ;
        RECT  0 45.621 0.018 45.639 ;
        RECT  0 45.081 0.018 45.099 ;
        RECT  0 44.541 0.018 44.559 ;
        RECT  0 44.001 0.018 44.019 ;
        RECT  0 43.461 0.018 43.479 ;
        RECT  0 42.921 0.018 42.939 ;
        RECT  0 42.381 0.018 42.399 ;
        RECT  0 41.841 0.018 41.859 ;
        RECT  0 41.301 0.018 41.319 ;
        RECT  0 40.761 0.018 40.779 ;
        RECT  0 40.221 0.018 40.239 ;
        RECT  0 39.681 0.018 39.699 ;
        RECT  0 39.141 0.018 39.159 ;
        RECT  0 38.601 0.018 38.619 ;
        RECT  0 38.061 0.018 38.079 ;
        RECT  0 37.521 0.018 37.539 ;
        RECT  0 36.981 0.018 36.999 ;
        RECT  0 36.441 0.018 36.459 ;
        RECT  0 35.901 0.018 35.919 ;
        RECT  0 35.361 0.018 35.379 ;
        RECT  0 34.821 0.018 34.839 ;
        RECT  0 34.281 0.018 34.299 ;
        RECT  0 33.741 0.018 33.759 ;
        RECT  0 33.201 0.018 33.219 ;
        RECT  0 32.661 0.018 32.679 ;
        RECT  0 32.121 0.018 32.139 ;
        RECT  0 31.581 0.018 31.599 ;
        RECT  0 31.041 0.018 31.059 ;
        RECT  0 30.501 0.018 30.519 ;
        RECT  0 29.961 0.018 29.979 ;
        RECT  0 29.421 0.018 29.439 ;
        RECT  0 28.881 0.018 28.899 ;
        RECT  0 28.341 0.018 28.359 ;
        RECT  0 27.801 0.018 27.819 ;
        RECT  0 27.261 0.018 27.279 ;
        RECT  0 26.721 0.018 26.739 ;
        RECT  0 26.181 0.018 26.199 ;
        RECT  0 25.641 0.018 25.659 ;
        RECT  0 25.101 0.018 25.119 ;
        RECT  0 24.561 0.018 24.579 ;
        RECT  0 24.021 0.018 24.039 ;
        RECT  0 23.481 0.018 23.499 ;
        RECT  0 22.941 0.018 22.959 ;
        RECT  0 22.401 0.018 22.419 ;
        RECT  0 21.861 0.018 21.879 ;
        RECT  0 21.321 0.018 21.339 ;
        RECT  0 20.781 0.018 20.799 ;
        RECT  0 20.241 0.018 20.259 ;
        RECT  0 19.701 0.018 19.719 ;
        RECT  0 19.161 0.018 19.179 ;
        RECT  0 18.621 0.018 18.639 ;
        RECT  0 18.081 0.018 18.099 ;
        RECT  0 17.541 0.018 17.559 ;
        RECT  0 17.001 0.018 17.019 ;
        RECT  0 16.461 0.018 16.479 ;
        RECT  0 15.921 0.018 15.939 ;
        RECT  0 15.381 0.018 15.399 ;
        RECT  0 14.841 0.018 14.859 ;
        RECT  0 14.301 0.018 14.319 ;
        RECT  0 13.761 0.018 13.779 ;
        RECT  0 13.221 0.018 13.239 ;
        RECT  0 12.681 0.018 12.699 ;
        RECT  0 12.141 0.018 12.159 ;
        RECT  0 11.601 0.018 11.619 ;
        RECT  0 11.061 0.018 11.079 ;
        RECT  0 10.521 0.018 10.539 ;
        RECT  0 9.981 0.018 9.999 ;
        RECT  0 9.441 0.018 9.459 ;
        RECT  0 8.901 0.018 8.919 ;
        RECT  0 8.361 0.018 8.379 ;
        RECT  0 7.821 0.018 7.839 ;
        RECT  0 7.281 0.018 7.299 ;
        RECT  0 6.741 0.018 6.759 ;
        RECT  0 6.201 0.018 6.219 ;
        RECT  0 5.661 0.018 5.679 ;
        RECT  0 5.121 0.018 5.139 ;
        RECT  0 4.581 0.018 4.599 ;
        RECT  0 4.041 0.018 4.059 ;
        RECT  0 3.501 0.018 3.519 ;
        RECT  0 2.961 0.018 2.979 ;
        RECT  0 2.421 0.018 2.439 ;
        RECT  0 1.881 0.018 1.899 ;
        RECT  0 1.341 0.018 1.359 ;
        RECT  0 0.801 0.018 0.819 ;
    END
  END VDD
  PIN VSS
    DIRECTION INOUT ;
    USE GROUND ;
    PORT
      LAYER M7 ;
        RECT  33.256 0.531 33.544 76.959 ;
        RECT  22.456 0.531 22.744 76.959 ;
        RECT  11.656 0.531 11.944 76.959 ;
        RECT  0.856 0.531 1.144 76.959 ;
      LAYER M6 ;
        RECT  0 76.596 0.032 76.884 ;
        RECT  0 71.196 0.032 71.484 ;
        RECT  0 65.796 0.032 66.084 ;
        RECT  0 60.396 0.032 60.684 ;
        RECT  0 54.996 0.032 55.284 ;
        RECT  0 49.596 0.032 49.884 ;
        RECT  0 44.196 0.032 44.484 ;
        RECT  0 38.796 0.032 39.084 ;
        RECT  0 33.396 0.032 33.684 ;
        RECT  0 27.996 0.032 28.284 ;
        RECT  0 22.596 0.032 22.884 ;
        RECT  0 17.196 0.032 17.484 ;
        RECT  0 11.796 0.032 12.084 ;
        RECT  0 6.396 0.032 6.684 ;
        RECT  0 0.996 0.032 1.284 ;
      LAYER M2 ;
        RECT  0 76.671 0.018 76.689 ;
        RECT  0 76.131 0.018 76.149 ;
        RECT  0 75.591 0.018 75.609 ;
        RECT  0 75.051 0.018 75.069 ;
        RECT  0 74.511 0.018 74.529 ;
        RECT  0 73.971 0.018 73.989 ;
        RECT  0 73.431 0.018 73.449 ;
        RECT  0 72.891 0.018 72.909 ;
        RECT  0 72.351 0.018 72.369 ;
        RECT  0 71.811 0.018 71.829 ;
        RECT  0 71.271 0.018 71.289 ;
        RECT  0 70.731 0.018 70.749 ;
        RECT  0 70.191 0.018 70.209 ;
        RECT  0 69.651 0.018 69.669 ;
        RECT  0 69.111 0.018 69.129 ;
        RECT  0 68.571 0.018 68.589 ;
        RECT  0 68.031 0.018 68.049 ;
        RECT  0 67.491 0.018 67.509 ;
        RECT  0 66.951 0.018 66.969 ;
        RECT  0 66.411 0.018 66.429 ;
        RECT  0 65.871 0.018 65.889 ;
        RECT  0 65.331 0.018 65.349 ;
        RECT  0 64.791 0.018 64.809 ;
        RECT  0 64.251 0.018 64.269 ;
        RECT  0 63.711 0.018 63.729 ;
        RECT  0 63.171 0.018 63.189 ;
        RECT  0 62.631 0.018 62.649 ;
        RECT  0 62.091 0.018 62.109 ;
        RECT  0 61.551 0.018 61.569 ;
        RECT  0 61.011 0.018 61.029 ;
        RECT  0 60.471 0.018 60.489 ;
        RECT  0 59.931 0.018 59.949 ;
        RECT  0 59.391 0.018 59.409 ;
        RECT  0 58.851 0.018 58.869 ;
        RECT  0 58.311 0.018 58.329 ;
        RECT  0 57.771 0.018 57.789 ;
        RECT  0 57.231 0.018 57.249 ;
        RECT  0 56.691 0.018 56.709 ;
        RECT  0 56.151 0.018 56.169 ;
        RECT  0 55.611 0.018 55.629 ;
        RECT  0 55.071 0.018 55.089 ;
        RECT  0 54.531 0.018 54.549 ;
        RECT  0 53.991 0.018 54.009 ;
        RECT  0 53.451 0.018 53.469 ;
        RECT  0 52.911 0.018 52.929 ;
        RECT  0 52.371 0.018 52.389 ;
        RECT  0 51.831 0.018 51.849 ;
        RECT  0 51.291 0.018 51.309 ;
        RECT  0 50.751 0.018 50.769 ;
        RECT  0 50.211 0.018 50.229 ;
        RECT  0 49.671 0.018 49.689 ;
        RECT  0 49.131 0.018 49.149 ;
        RECT  0 48.591 0.018 48.609 ;
        RECT  0 48.051 0.018 48.069 ;
        RECT  0 47.511 0.018 47.529 ;
        RECT  0 46.971 0.018 46.989 ;
        RECT  0 46.431 0.018 46.449 ;
        RECT  0 45.891 0.018 45.909 ;
        RECT  0 45.351 0.018 45.369 ;
        RECT  0 44.811 0.018 44.829 ;
        RECT  0 44.271 0.018 44.289 ;
        RECT  0 43.731 0.018 43.749 ;
        RECT  0 43.191 0.018 43.209 ;
        RECT  0 42.651 0.018 42.669 ;
        RECT  0 42.111 0.018 42.129 ;
        RECT  0 41.571 0.018 41.589 ;
        RECT  0 41.031 0.018 41.049 ;
        RECT  0 40.491 0.018 40.509 ;
        RECT  0 39.951 0.018 39.969 ;
        RECT  0 39.411 0.018 39.429 ;
        RECT  0 38.871 0.018 38.889 ;
        RECT  0 38.331 0.018 38.349 ;
        RECT  0 37.791 0.018 37.809 ;
        RECT  0 37.251 0.018 37.269 ;
        RECT  0 36.711 0.018 36.729 ;
        RECT  0 36.171 0.018 36.189 ;
        RECT  0 35.631 0.018 35.649 ;
        RECT  0 35.091 0.018 35.109 ;
        RECT  0 34.551 0.018 34.569 ;
        RECT  0 34.011 0.018 34.029 ;
        RECT  0 33.471 0.018 33.489 ;
        RECT  0 32.931 0.018 32.949 ;
        RECT  0 32.391 0.018 32.409 ;
        RECT  0 31.851 0.018 31.869 ;
        RECT  0 31.311 0.018 31.329 ;
        RECT  0 30.771 0.018 30.789 ;
        RECT  0 30.231 0.018 30.249 ;
        RECT  0 29.691 0.018 29.709 ;
        RECT  0 29.151 0.018 29.169 ;
        RECT  0 28.611 0.018 28.629 ;
        RECT  0 28.071 0.018 28.089 ;
        RECT  0 27.531 0.018 27.549 ;
        RECT  0 26.991 0.018 27.009 ;
        RECT  0 26.451 0.018 26.469 ;
        RECT  0 25.911 0.018 25.929 ;
        RECT  0 25.371 0.018 25.389 ;
        RECT  0 24.831 0.018 24.849 ;
        RECT  0 24.291 0.018 24.309 ;
        RECT  0 23.751 0.018 23.769 ;
        RECT  0 23.211 0.018 23.229 ;
        RECT  0 22.671 0.018 22.689 ;
        RECT  0 22.131 0.018 22.149 ;
        RECT  0 21.591 0.018 21.609 ;
        RECT  0 21.051 0.018 21.069 ;
        RECT  0 20.511 0.018 20.529 ;
        RECT  0 19.971 0.018 19.989 ;
        RECT  0 19.431 0.018 19.449 ;
        RECT  0 18.891 0.018 18.909 ;
        RECT  0 18.351 0.018 18.369 ;
        RECT  0 17.811 0.018 17.829 ;
        RECT  0 17.271 0.018 17.289 ;
        RECT  0 16.731 0.018 16.749 ;
        RECT  0 16.191 0.018 16.209 ;
        RECT  0 15.651 0.018 15.669 ;
        RECT  0 15.111 0.018 15.129 ;
        RECT  0 14.571 0.018 14.589 ;
        RECT  0 14.031 0.018 14.049 ;
        RECT  0 13.491 0.018 13.509 ;
        RECT  0 12.951 0.018 12.969 ;
        RECT  0 12.411 0.018 12.429 ;
        RECT  0 11.871 0.018 11.889 ;
        RECT  0 11.331 0.018 11.349 ;
        RECT  0 10.791 0.018 10.809 ;
        RECT  0 10.251 0.018 10.269 ;
        RECT  0 9.711 0.018 9.729 ;
        RECT  0 9.171 0.018 9.189 ;
        RECT  0 8.631 0.018 8.649 ;
        RECT  0 8.091 0.018 8.109 ;
        RECT  0 7.551 0.018 7.569 ;
        RECT  0 7.011 0.018 7.029 ;
        RECT  0 6.471 0.018 6.489 ;
        RECT  0 5.931 0.018 5.949 ;
        RECT  0 5.391 0.018 5.409 ;
        RECT  0 4.851 0.018 4.869 ;
        RECT  0 4.311 0.018 4.329 ;
        RECT  0 3.771 0.018 3.789 ;
        RECT  0 3.231 0.018 3.249 ;
        RECT  0 2.691 0.018 2.709 ;
        RECT  0 2.151 0.018 2.169 ;
        RECT  0 1.611 0.018 1.629 ;
        RECT  0 1.071 0.018 1.089 ;
        RECT  0 0.531 0.018 0.549 ;
      LAYER M1 ;
        RECT  0 76.671 0.018 76.689 ;
        RECT  0 76.131 0.018 76.149 ;
        RECT  0 75.591 0.018 75.609 ;
        RECT  0 75.051 0.018 75.069 ;
        RECT  0 74.511 0.018 74.529 ;
        RECT  0 73.971 0.018 73.989 ;
        RECT  0 73.431 0.018 73.449 ;
        RECT  0 72.891 0.018 72.909 ;
        RECT  0 72.351 0.018 72.369 ;
        RECT  0 71.811 0.018 71.829 ;
        RECT  0 71.271 0.018 71.289 ;
        RECT  0 70.731 0.018 70.749 ;
        RECT  0 70.191 0.018 70.209 ;
        RECT  0 69.651 0.018 69.669 ;
        RECT  0 69.111 0.018 69.129 ;
        RECT  0 68.571 0.018 68.589 ;
        RECT  0 68.031 0.018 68.049 ;
        RECT  0 67.491 0.018 67.509 ;
        RECT  0 66.951 0.018 66.969 ;
        RECT  0 66.411 0.018 66.429 ;
        RECT  0 65.871 0.018 65.889 ;
        RECT  0 65.331 0.018 65.349 ;
        RECT  0 64.791 0.018 64.809 ;
        RECT  0 64.251 0.018 64.269 ;
        RECT  0 63.711 0.018 63.729 ;
        RECT  0 63.171 0.018 63.189 ;
        RECT  0 62.631 0.018 62.649 ;
        RECT  0 62.091 0.018 62.109 ;
        RECT  0 61.551 0.018 61.569 ;
        RECT  0 61.011 0.018 61.029 ;
        RECT  0 60.471 0.018 60.489 ;
        RECT  0 59.931 0.018 59.949 ;
        RECT  0 59.391 0.018 59.409 ;
        RECT  0 58.851 0.018 58.869 ;
        RECT  0 58.311 0.018 58.329 ;
        RECT  0 57.771 0.018 57.789 ;
        RECT  0 57.231 0.018 57.249 ;
        RECT  0 56.691 0.018 56.709 ;
        RECT  0 56.151 0.018 56.169 ;
        RECT  0 55.611 0.018 55.629 ;
        RECT  0 55.071 0.018 55.089 ;
        RECT  0 54.531 0.018 54.549 ;
        RECT  0 53.991 0.018 54.009 ;
        RECT  0 53.451 0.018 53.469 ;
        RECT  0 52.911 0.018 52.929 ;
        RECT  0 52.371 0.018 52.389 ;
        RECT  0 51.831 0.018 51.849 ;
        RECT  0 51.291 0.018 51.309 ;
        RECT  0 50.751 0.018 50.769 ;
        RECT  0 50.211 0.018 50.229 ;
        RECT  0 49.671 0.018 49.689 ;
        RECT  0 49.131 0.018 49.149 ;
        RECT  0 48.591 0.018 48.609 ;
        RECT  0 48.051 0.018 48.069 ;
        RECT  0 47.511 0.018 47.529 ;
        RECT  0 46.971 0.018 46.989 ;
        RECT  0 46.431 0.018 46.449 ;
        RECT  0 45.891 0.018 45.909 ;
        RECT  0 45.351 0.018 45.369 ;
        RECT  0 44.811 0.018 44.829 ;
        RECT  0 44.271 0.018 44.289 ;
        RECT  0 43.731 0.018 43.749 ;
        RECT  0 43.191 0.018 43.209 ;
        RECT  0 42.651 0.018 42.669 ;
        RECT  0 42.111 0.018 42.129 ;
        RECT  0 41.571 0.018 41.589 ;
        RECT  0 41.031 0.018 41.049 ;
        RECT  0 40.491 0.018 40.509 ;
        RECT  0 39.951 0.018 39.969 ;
        RECT  0 39.411 0.018 39.429 ;
        RECT  0 38.871 0.018 38.889 ;
        RECT  0 38.331 0.018 38.349 ;
        RECT  0 37.791 0.018 37.809 ;
        RECT  0 37.251 0.018 37.269 ;
        RECT  0 36.711 0.018 36.729 ;
        RECT  0 36.171 0.018 36.189 ;
        RECT  0 35.631 0.018 35.649 ;
        RECT  0 35.091 0.018 35.109 ;
        RECT  0 34.551 0.018 34.569 ;
        RECT  0 34.011 0.018 34.029 ;
        RECT  0 33.471 0.018 33.489 ;
        RECT  0 32.931 0.018 32.949 ;
        RECT  0 32.391 0.018 32.409 ;
        RECT  0 31.851 0.018 31.869 ;
        RECT  0 31.311 0.018 31.329 ;
        RECT  0 30.771 0.018 30.789 ;
        RECT  0 30.231 0.018 30.249 ;
        RECT  0 29.691 0.018 29.709 ;
        RECT  0 29.151 0.018 29.169 ;
        RECT  0 28.611 0.018 28.629 ;
        RECT  0 28.071 0.018 28.089 ;
        RECT  0 27.531 0.018 27.549 ;
        RECT  0 26.991 0.018 27.009 ;
        RECT  0 26.451 0.018 26.469 ;
        RECT  0 25.911 0.018 25.929 ;
        RECT  0 25.371 0.018 25.389 ;
        RECT  0 24.831 0.018 24.849 ;
        RECT  0 24.291 0.018 24.309 ;
        RECT  0 23.751 0.018 23.769 ;
        RECT  0 23.211 0.018 23.229 ;
        RECT  0 22.671 0.018 22.689 ;
        RECT  0 22.131 0.018 22.149 ;
        RECT  0 21.591 0.018 21.609 ;
        RECT  0 21.051 0.018 21.069 ;
        RECT  0 20.511 0.018 20.529 ;
        RECT  0 19.971 0.018 19.989 ;
        RECT  0 19.431 0.018 19.449 ;
        RECT  0 18.891 0.018 18.909 ;
        RECT  0 18.351 0.018 18.369 ;
        RECT  0 17.811 0.018 17.829 ;
        RECT  0 17.271 0.018 17.289 ;
        RECT  0 16.731 0.018 16.749 ;
        RECT  0 16.191 0.018 16.209 ;
        RECT  0 15.651 0.018 15.669 ;
        RECT  0 15.111 0.018 15.129 ;
        RECT  0 14.571 0.018 14.589 ;
        RECT  0 14.031 0.018 14.049 ;
        RECT  0 13.491 0.018 13.509 ;
        RECT  0 12.951 0.018 12.969 ;
        RECT  0 12.411 0.018 12.429 ;
        RECT  0 11.871 0.018 11.889 ;
        RECT  0 11.331 0.018 11.349 ;
        RECT  0 10.791 0.018 10.809 ;
        RECT  0 10.251 0.018 10.269 ;
        RECT  0 9.711 0.018 9.729 ;
        RECT  0 9.171 0.018 9.189 ;
        RECT  0 8.631 0.018 8.649 ;
        RECT  0 8.091 0.018 8.109 ;
        RECT  0 7.551 0.018 7.569 ;
        RECT  0 7.011 0.018 7.029 ;
        RECT  0 6.471 0.018 6.489 ;
        RECT  0 5.931 0.018 5.949 ;
        RECT  0 5.391 0.018 5.409 ;
        RECT  0 4.851 0.018 4.869 ;
        RECT  0 4.311 0.018 4.329 ;
        RECT  0 3.771 0.018 3.789 ;
        RECT  0 3.231 0.018 3.249 ;
        RECT  0 2.691 0.018 2.709 ;
        RECT  0 2.151 0.018 2.169 ;
        RECT  0 1.611 0.018 1.629 ;
        RECT  0 1.071 0.018 1.089 ;
        RECT  0 0.531 0.018 0.549 ;
    END
  END VSS
  OBS
    LAYER RVTN ;
     RECT  0 0.54 39.258 0.675 ;
     RECT  0 0.945 39.258 1.215 ;
     RECT  0 1.485 39.258 1.755 ;
     RECT  0 2.025 39.258 2.295 ;
     RECT  0 2.565 39.258 2.835 ;
     RECT  0 3.105 39.258 3.375 ;
     RECT  0 3.645 39.258 3.915 ;
     RECT  0 4.185 39.258 4.455 ;
     RECT  0 4.725 39.258 4.995 ;
     RECT  0 5.265 39.258 5.535 ;
     RECT  0 5.805 39.258 6.075 ;
     RECT  0 6.345 39.258 6.615 ;
     RECT  0 6.885 39.258 7.155 ;
     RECT  0 7.425 39.258 7.695 ;
     RECT  0 7.965 39.258 8.235 ;
     RECT  0 8.505 39.258 8.775 ;
     RECT  0 9.045 39.258 9.315 ;
     RECT  0 9.585 39.258 9.855 ;
     RECT  0 10.125 39.258 10.395 ;
     RECT  0 10.665 39.258 10.935 ;
     RECT  0 11.205 39.258 11.475 ;
     RECT  0 11.745 39.258 12.015 ;
     RECT  0 12.285 39.258 12.555 ;
     RECT  0 12.825 39.258 13.095 ;
     RECT  0 13.365 39.258 13.635 ;
     RECT  0 13.905 39.258 14.175 ;
     RECT  0 14.445 39.258 14.715 ;
     RECT  0 14.985 39.258 15.255 ;
     RECT  0 15.525 39.258 15.795 ;
     RECT  0 16.065 39.258 16.335 ;
     RECT  0 16.605 39.258 16.875 ;
     RECT  0 17.145 39.258 17.415 ;
     RECT  0 17.685 39.258 17.955 ;
     RECT  0 18.225 39.258 18.495 ;
     RECT  0 18.765 39.258 19.035 ;
     RECT  0 19.305 39.258 19.575 ;
     RECT  0 19.845 39.258 20.115 ;
     RECT  0 20.385 39.258 20.655 ;
     RECT  0 20.925 39.258 21.195 ;
     RECT  0 21.465 39.258 21.735 ;
     RECT  0 22.005 39.258 22.275 ;
     RECT  0 22.545 39.258 22.815 ;
     RECT  0 23.085 39.258 23.355 ;
     RECT  0 23.625 39.258 23.895 ;
     RECT  0 24.165 39.258 24.435 ;
     RECT  0 24.705 39.258 24.975 ;
     RECT  0 25.245 39.258 25.515 ;
     RECT  0 25.785 39.258 26.055 ;
     RECT  0 26.325 39.258 26.595 ;
     RECT  0 26.865 39.258 27.135 ;
     RECT  0 27.405 39.258 27.675 ;
     RECT  0 27.945 39.258 28.215 ;
     RECT  0 28.485 39.258 28.755 ;
     RECT  0 29.025 39.258 29.295 ;
     RECT  0 29.565 39.258 29.835 ;
     RECT  0 30.105 39.258 30.375 ;
     RECT  0 30.645 39.258 30.915 ;
     RECT  0 31.185 39.258 31.455 ;
     RECT  0 31.725 39.258 31.995 ;
     RECT  0 32.265 39.258 32.535 ;
     RECT  0 32.805 39.258 33.075 ;
     RECT  0 33.345 39.258 33.615 ;
     RECT  0 33.885 39.258 34.155 ;
     RECT  0 34.425 39.258 34.695 ;
     RECT  0 34.965 39.258 35.235 ;
     RECT  0 35.505 39.258 35.775 ;
     RECT  0 36.045 39.258 36.315 ;
     RECT  0 36.585 39.258 36.855 ;
     RECT  0 37.125 39.258 37.395 ;
     RECT  0 37.665 39.258 37.935 ;
     RECT  0 38.205 39.258 38.475 ;
     RECT  0 38.745 39.258 39.015 ;
     RECT  0 39.285 39.258 39.555 ;
     RECT  0 39.825 39.258 40.095 ;
     RECT  0 40.365 39.258 40.635 ;
     RECT  0 40.905 39.258 41.175 ;
     RECT  0 41.445 39.258 41.715 ;
     RECT  0 41.985 39.258 42.255 ;
     RECT  0 42.525 39.258 42.795 ;
     RECT  0 43.065 39.258 43.335 ;
     RECT  0 43.605 39.258 43.875 ;
     RECT  0 44.145 39.258 44.415 ;
     RECT  0 44.685 39.258 44.955 ;
     RECT  0 45.225 39.258 45.495 ;
     RECT  0 45.765 39.258 46.035 ;
     RECT  0 46.305 39.258 46.575 ;
     RECT  0 46.845 39.258 47.115 ;
     RECT  0 47.385 39.258 47.655 ;
     RECT  0 47.925 39.258 48.195 ;
     RECT  0 48.465 39.258 48.735 ;
     RECT  0 49.005 39.258 49.275 ;
     RECT  0 49.545 39.258 49.815 ;
     RECT  0 50.085 39.258 50.355 ;
     RECT  0 50.625 39.258 50.895 ;
     RECT  0 51.165 39.258 51.435 ;
     RECT  0 51.705 39.258 51.975 ;
     RECT  0 52.245 39.258 52.515 ;
     RECT  0 52.785 39.258 53.055 ;
     RECT  0 53.325 39.258 53.595 ;
     RECT  0 53.865 39.258 54.135 ;
     RECT  0 54.405 39.258 54.675 ;
     RECT  0 54.945 39.258 55.215 ;
     RECT  0 55.485 39.258 55.755 ;
     RECT  0 56.025 39.258 56.295 ;
     RECT  0 56.565 39.258 56.835 ;
     RECT  0 57.105 39.258 57.375 ;
     RECT  0 57.645 39.258 57.915 ;
     RECT  0 58.185 39.258 58.455 ;
     RECT  0 58.725 39.258 58.995 ;
     RECT  0 59.265 39.258 59.535 ;
     RECT  0 59.805 39.258 60.075 ;
     RECT  0 60.345 39.258 60.615 ;
     RECT  0 60.885 39.258 61.155 ;
     RECT  0 61.425 39.258 61.695 ;
     RECT  0 61.965 39.258 62.235 ;
     RECT  0 62.505 39.258 62.775 ;
     RECT  0 63.045 39.258 63.315 ;
     RECT  0 63.585 39.258 63.855 ;
     RECT  0 64.125 39.258 64.395 ;
     RECT  0 64.665 39.258 64.935 ;
     RECT  0 65.205 39.258 65.475 ;
     RECT  0 65.745 39.258 66.015 ;
     RECT  0 66.285 39.258 66.555 ;
     RECT  0 66.825 39.258 67.095 ;
     RECT  0 67.365 39.258 67.635 ;
     RECT  0 67.905 39.258 68.175 ;
     RECT  0 68.445 39.258 68.715 ;
     RECT  0 68.985 39.258 69.255 ;
     RECT  0 69.525 39.258 69.795 ;
     RECT  0 70.065 39.258 70.335 ;
     RECT  0 70.605 39.258 70.875 ;
     RECT  0 71.145 39.258 71.415 ;
     RECT  0 71.685 39.258 71.955 ;
     RECT  0 72.225 39.258 72.495 ;
     RECT  0 72.765 39.258 73.035 ;
     RECT  0 73.305 39.258 73.575 ;
     RECT  0 73.845 39.258 74.115 ;
     RECT  0 74.385 39.258 74.655 ;
     RECT  0 74.925 39.258 75.195 ;
     RECT  0 75.465 39.258 75.735 ;
     RECT  0 76.005 39.258 76.275 ;
     RECT  0 76.545 39.258 76.815 ;
    LAYER RVTP ;
     RECT  0 0.675 39.258 0.945 ;
     RECT  0 1.215 39.258 1.485 ;
     RECT  0 1.755 39.258 2.025 ;
     RECT  0 2.295 39.258 2.565 ;
     RECT  0 2.835 39.258 3.105 ;
     RECT  0 3.375 39.258 3.645 ;
     RECT  0 3.915 39.258 4.185 ;
     RECT  0 4.455 39.258 4.725 ;
     RECT  0 4.995 39.258 5.265 ;
     RECT  0 5.535 39.258 5.805 ;
     RECT  0 6.075 39.258 6.345 ;
     RECT  0 6.615 39.258 6.885 ;
     RECT  0 7.155 39.258 7.425 ;
     RECT  0 7.695 39.258 7.965 ;
     RECT  0 8.235 39.258 8.505 ;
     RECT  0 8.775 39.258 9.045 ;
     RECT  0 9.315 39.258 9.585 ;
     RECT  0 9.855 39.258 10.125 ;
     RECT  0 10.395 39.258 10.665 ;
     RECT  0 10.935 39.258 11.205 ;
     RECT  0 11.475 39.258 11.745 ;
     RECT  0 12.015 39.258 12.285 ;
     RECT  0 12.555 39.258 12.825 ;
     RECT  0 13.095 39.258 13.365 ;
     RECT  0 13.635 39.258 13.905 ;
     RECT  0 14.175 39.258 14.445 ;
     RECT  0 14.715 39.258 14.985 ;
     RECT  0 15.255 39.258 15.525 ;
     RECT  0 15.795 39.258 16.065 ;
     RECT  0 16.335 39.258 16.605 ;
     RECT  0 16.875 39.258 17.145 ;
     RECT  0 17.415 39.258 17.685 ;
     RECT  0 17.955 39.258 18.225 ;
     RECT  0 18.495 39.258 18.765 ;
     RECT  0 19.035 39.258 19.305 ;
     RECT  0 19.575 39.258 19.845 ;
     RECT  0 20.115 39.258 20.385 ;
     RECT  0 20.655 39.258 20.925 ;
     RECT  0 21.195 39.258 21.465 ;
     RECT  0 21.735 39.258 22.005 ;
     RECT  0 22.275 39.258 22.545 ;
     RECT  0 22.815 39.258 23.085 ;
     RECT  0 23.355 39.258 23.625 ;
     RECT  0 23.895 39.258 24.165 ;
     RECT  0 24.435 39.258 24.705 ;
     RECT  0 24.975 39.258 25.245 ;
     RECT  0 25.515 39.258 25.785 ;
     RECT  0 26.055 39.258 26.325 ;
     RECT  0 26.595 39.258 26.865 ;
     RECT  0 27.135 39.258 27.405 ;
     RECT  0 27.675 39.258 27.945 ;
     RECT  0 28.215 39.258 28.485 ;
     RECT  0 28.755 39.258 29.025 ;
     RECT  0 29.295 39.258 29.565 ;
     RECT  0 29.835 39.258 30.105 ;
     RECT  0 30.375 39.258 30.645 ;
     RECT  0 30.915 39.258 31.185 ;
     RECT  0 31.455 39.258 31.725 ;
     RECT  0 31.995 39.258 32.265 ;
     RECT  0 32.535 39.258 32.805 ;
     RECT  0 33.075 39.258 33.345 ;
     RECT  0 33.615 39.258 33.885 ;
     RECT  0 34.155 39.258 34.425 ;
     RECT  0 34.695 39.258 34.965 ;
     RECT  0 35.235 39.258 35.505 ;
     RECT  0 35.775 39.258 36.045 ;
     RECT  0 36.315 39.258 36.585 ;
     RECT  0 36.855 39.258 37.125 ;
     RECT  0 37.395 39.258 37.665 ;
     RECT  0 37.935 39.258 38.205 ;
     RECT  0 38.475 39.258 38.745 ;
     RECT  0 39.015 39.258 39.285 ;
     RECT  0 39.555 39.258 39.825 ;
     RECT  0 40.095 39.258 40.365 ;
     RECT  0 40.635 39.258 40.905 ;
     RECT  0 41.175 39.258 41.445 ;
     RECT  0 41.715 39.258 41.985 ;
     RECT  0 42.255 39.258 42.525 ;
     RECT  0 42.795 39.258 43.065 ;
     RECT  0 43.335 39.258 43.605 ;
     RECT  0 43.875 39.258 44.145 ;
     RECT  0 44.415 39.258 44.685 ;
     RECT  0 44.955 39.258 45.225 ;
     RECT  0 45.495 39.258 45.765 ;
     RECT  0 46.035 39.258 46.305 ;
     RECT  0 46.575 39.258 46.845 ;
     RECT  0 47.115 39.258 47.385 ;
     RECT  0 47.655 39.258 47.925 ;
     RECT  0 48.195 39.258 48.465 ;
     RECT  0 48.735 39.258 49.005 ;
     RECT  0 49.275 39.258 49.545 ;
     RECT  0 49.815 39.258 50.085 ;
     RECT  0 50.355 39.258 50.625 ;
     RECT  0 50.895 39.258 51.165 ;
     RECT  0 51.435 39.258 51.705 ;
     RECT  0 51.975 39.258 52.245 ;
     RECT  0 52.515 39.258 52.785 ;
     RECT  0 53.055 39.258 53.325 ;
     RECT  0 53.595 39.258 53.865 ;
     RECT  0 54.135 39.258 54.405 ;
     RECT  0 54.675 39.258 54.945 ;
     RECT  0 55.215 39.258 55.485 ;
     RECT  0 55.755 39.258 56.025 ;
     RECT  0 56.295 39.258 56.565 ;
     RECT  0 56.835 39.258 57.105 ;
     RECT  0 57.375 39.258 57.645 ;
     RECT  0 57.915 39.258 58.185 ;
     RECT  0 58.455 39.258 58.725 ;
     RECT  0 58.995 39.258 59.265 ;
     RECT  0 59.535 39.258 59.805 ;
     RECT  0 60.075 39.258 60.345 ;
     RECT  0 60.615 39.258 60.885 ;
     RECT  0 61.155 39.258 61.425 ;
     RECT  0 61.695 39.258 61.965 ;
     RECT  0 62.235 39.258 62.505 ;
     RECT  0 62.775 39.258 63.045 ;
     RECT  0 63.315 39.258 63.585 ;
     RECT  0 63.855 39.258 64.125 ;
     RECT  0 64.395 39.258 64.665 ;
     RECT  0 64.935 39.258 65.205 ;
     RECT  0 65.475 39.258 65.745 ;
     RECT  0 66.015 39.258 66.285 ;
     RECT  0 66.555 39.258 66.825 ;
     RECT  0 67.095 39.258 67.365 ;
     RECT  0 67.635 39.258 67.905 ;
     RECT  0 68.175 39.258 68.445 ;
     RECT  0 68.715 39.258 68.985 ;
     RECT  0 69.255 39.258 69.525 ;
     RECT  0 69.795 39.258 70.065 ;
     RECT  0 70.335 39.258 70.605 ;
     RECT  0 70.875 39.258 71.145 ;
     RECT  0 71.415 39.258 71.685 ;
     RECT  0 71.955 39.258 72.225 ;
     RECT  0 72.495 39.258 72.765 ;
     RECT  0 73.035 39.258 73.305 ;
     RECT  0 73.575 39.258 73.845 ;
     RECT  0 74.115 39.258 74.385 ;
     RECT  0 74.655 39.258 74.925 ;
     RECT  0 75.195 39.258 75.465 ;
     RECT  0 75.735 39.258 76.005 ;
     RECT  0 76.275 39.258 76.545 ;
     RECT  0 76.815 39.258 76.95 ;
    LAYER M1 ;
     RECT  0 0.531 39.258 76.959 ;
    LAYER M2 ;
     RECT  0 0.531 14.827 76.959 ;
     RECT  14.827 0.108 14.999 76.959 ;
     RECT  14.999 0.531 16.303 76.959 ;
     RECT  16.303 0.486 16.987 76.959 ;
     RECT  16.987 0.414 17.375 76.959 ;
     RECT  17.375 0.486 17.411 76.959 ;
     RECT  17.411 0.531 21.631 76.959 ;
     RECT  21.631 0.45 21.947 76.959 ;
     RECT  21.947 0.531 24.943 76.959 ;
     RECT  24.943 0.45 25.195 76.959 ;
     RECT  25.195 0.414 26.743 76.959 ;
     RECT  26.743 0.216 27.779 76.959 ;
     RECT  27.779 0.414 27.887 76.959 ;
     RECT  27.887 0.531 28.759 76.959 ;
     RECT  28.759 0.45 29.147 76.959 ;
     RECT  29.147 0.531 32.143 76.959 ;
     RECT  32.143 0.45 32.575 76.959 ;
     RECT  32.575 0.414 32.791 76.959 ;
     RECT  32.791 0.306 32.963 76.959 ;
     RECT  32.963 0.531 33.799 76.959 ;
     RECT  33.799 0.036 37.823 76.959 ;
     RECT  37.823 0.306 38.147 76.959 ;
     RECT  38.147 0.45 38.183 76.959 ;
     RECT  38.183 0.531 39.258 76.959 ;
    LAYER M3 ;
     RECT  33.804 0.031 33.822 0.043 ;
     RECT  16.776 0.043 16.794 0.091 ;
     RECT  26.676 0.043 27.018 0.091 ;
     RECT  33.804 0.043 33.966 0.091 ;
     RECT  14.868 0.091 14.994 0.103 ;
     RECT  9.648 0.043 9.666 0.139 ;
     RECT  16.776 0.091 16.902 0.139 ;
     RECT  20.376 0.091 20.394 0.139 ;
     RECT  23.652 0.043 23.67 0.139 ;
     RECT  33.552 0.091 34.506 0.139 ;
     RECT  36.288 0.091 36.306 0.139 ;
     RECT  37.8 0.031 37.818 0.139 ;
     RECT  19.296 0.043 19.314 0.187 ;
     RECT  20.232 0.139 20.898 0.187 ;
     RECT  23.472 0.139 23.67 0.187 ;
     RECT  25.704 0.091 25.722 0.187 ;
     RECT  26.676 0.091 27.702 0.187 ;
     RECT  29.736 0.091 29.862 0.187 ;
     RECT  30.96 0.043 32.094 0.187 ;
     RECT  33.408 0.139 34.506 0.187 ;
     RECT  37.8 0.139 37.89 0.187 ;
     RECT  10.764 0.091 10.782 0.235 ;
     RECT  18.432 0.091 18.45 0.235 ;
     RECT  19.296 0.187 21.366 0.235 ;
     RECT  22.608 0.043 22.626 0.235 ;
     RECT  23.4 0.187 23.67 0.235 ;
     RECT  24.444 0.139 24.462 0.235 ;
     RECT  25.416 0.187 25.722 0.235 ;
     RECT  26.676 0.187 28.026 0.235 ;
     RECT  29.736 0.187 32.094 0.235 ;
     RECT  36.144 0.139 36.306 0.235 ;
     RECT  37.8 0.187 38.034 0.235 ;
     RECT  13.644 0.187 13.662 0.283 ;
     RECT  14.832 0.103 14.994 0.283 ;
     RECT  16.596 0.139 17.19 0.283 ;
     RECT  18.432 0.235 21.366 0.283 ;
     RECT  22.536 0.235 25.722 0.283 ;
     RECT  26.532 0.235 28.026 0.283 ;
     RECT  29.196 0.235 32.094 0.283 ;
     RECT  33.408 0.187 34.722 0.283 ;
     RECT  35.712 0.235 36.306 0.283 ;
     RECT  37.548 0.235 38.034 0.283 ;
     RECT  13.644 0.283 28.314 0.331 ;
     RECT  29.196 0.283 36.306 0.331 ;
     RECT  13.644 0.331 36.306 0.379 ;
     RECT  37.224 0.283 38.466 0.379 ;
     RECT  13.644 0.379 38.466 0.427 ;
     RECT  12.96 0.427 38.466 0.571 ;
     RECT  12.6 0.571 38.466 0.619 ;
     RECT  0.255 0.523 0.345 0.793 ;
     RECT  5.655 0.523 5.745 0.793 ;
     RECT  10.764 0.235 11.394 1.147 ;
     RECT  12.528 0.619 38.466 1.183 ;
     RECT  10.764 1.147 11.574 1.453 ;
     RECT  12.42 1.183 38.466 1.453 ;
     RECT  9.468 0.139 9.666 1.525 ;
     RECT  10.764 1.453 38.466 1.831 ;
     RECT  9.468 1.525 9.738 2.011 ;
     RECT  8.748 2.011 9.738 2.065 ;
     RECT  10.656 1.831 38.466 2.065 ;
     RECT  8.748 2.065 38.466 2.101 ;
     RECT  7.956 2.263 7.974 2.371 ;
     RECT  8.712 2.101 38.466 2.371 ;
     RECT  7.956 2.371 38.466 2.489 ;
     RECT  6.84 2.461 6.858 2.533 ;
     RECT  5.655 0.793 5.937 2.731 ;
     RECT  6.696 2.533 6.858 2.779 ;
     RECT  7.956 2.489 38.337 2.779 ;
     RECT  4.968 2.731 5.937 3.181 ;
     RECT  6.696 2.779 38.337 3.181 ;
     RECT  4.968 3.181 38.337 3.451 ;
     RECT  4.896 3.451 38.337 3.713 ;
     RECT  4.896 3.713 6.714 6.691 ;
     RECT  7.56 3.713 38.337 6.691 ;
     RECT  4.896 6.691 38.337 7.393 ;
     RECT  4.824 7.393 38.337 7.435 ;
     RECT  3.276 3.685 3.294 7.771 ;
     RECT  4.32 7.435 38.337 7.889 ;
     RECT  3.276 7.771 3.402 12.901 ;
     RECT  4.824 7.889 38.337 12.901 ;
     RECT  3.276 12.901 38.337 12.941 ;
     RECT  4.284 12.941 38.337 13.559 ;
     RECT  4.284 13.559 36.738 21.541 ;
     RECT  4.212 21.541 36.738 21.629 ;
     RECT  4.284 21.629 36.738 22.739 ;
     RECT  36.18 22.739 36.738 24.809 ;
     RECT  3.276 12.941 3.402 26.671 ;
     RECT  4.284 22.739 35.442 26.671 ;
     RECT  3.276 26.671 35.442 27.059 ;
     RECT  3.276 27.059 3.402 27.175 ;
     RECT  2.988 27.175 3.402 27.329 ;
     RECT  3.276 27.329 3.402 29.029 ;
     RECT  4.284 27.059 35.442 29.029 ;
     RECT  36.72 24.809 36.738 29.083 ;
     RECT  3.276 29.029 35.442 29.335 ;
     RECT  36.36 29.083 36.738 29.335 ;
     RECT  37.584 13.559 38.337 29.759 ;
     RECT  3.276 29.335 36.738 30.235 ;
     RECT  3.276 30.235 36.81 30.299 ;
     RECT  37.8 29.759 38.337 32.845 ;
     RECT  3.276 30.299 36.738 32.999 ;
     RECT  3.276 32.999 36.198 35.323 ;
     RECT  3.276 35.323 36.882 35.699 ;
     RECT  3.276 35.699 36.198 38.137 ;
     RECT  1.872 27.337 1.89 40.135 ;
     RECT  1.692 40.135 1.89 40.405 ;
     RECT  2.664 38.137 36.198 40.405 ;
     RECT  37.62 32.845 38.337 42.719 ;
     RECT  1.692 40.405 36.198 50.855 ;
     RECT  1.692 50.855 34.722 51.899 ;
     RECT  1.692 51.899 34.182 52.825 ;
     RECT  1.332 52.825 34.182 54.869 ;
     RECT  35.856 50.855 36.198 56.101 ;
     RECT  1.332 54.869 34.002 56.491 ;
     RECT  35.532 56.101 36.198 56.759 ;
     RECT  1.332 56.491 34.614 56.795 ;
     RECT  1.332 56.795 34.002 59.729 ;
     RECT  1.332 59.729 33.786 60.269 ;
     RECT  1.332 60.269 32.994 61.079 ;
     RECT  0.255 0.793 0.537 65.245 ;
     RECT  1.332 61.079 32.937 65.245 ;
     RECT  0.255 65.245 32.937 65.309 ;
     RECT  1.44 65.309 32.937 68.099 ;
     RECT  0.255 65.309 0.537 68.215 ;
     RECT  0.255 68.215 1.242 68.953 ;
     RECT  1.98 68.099 32.937 68.953 ;
     RECT  36.18 56.759 36.198 69.449 ;
     RECT  36.108 69.601 36.126 69.719 ;
     RECT  34.776 69.691 34.794 69.728 ;
     RECT  34.92 69.871 34.938 72.959 ;
     RECT  33.768 60.269 33.786 73.075 ;
     RECT  33.768 73.075 34.218 74.309 ;
     RECT  33.768 74.309 33.786 74.425 ;
     RECT  0.255 68.953 32.937 74.909 ;
     RECT  1.548 74.909 32.937 75.389 ;
     RECT  33.696 74.425 33.786 75.389 ;
     RECT  33.696 75.389 33.714 75.659 ;
     RECT  1.548 75.389 31.734 75.775 ;
     RECT  32.472 75.389 32.937 75.775 ;
     RECT  1.476 75.775 31.734 76.001 ;
     RECT  1.476 76.001 31.302 76.199 ;
     RECT  32.472 75.775 33.066 76.199 ;
     RECT  1.476 76.199 29.214 76.307 ;
     RECT  1.476 76.307 29.178 76.315 ;
     RECT  30.168 76.199 31.302 76.469 ;
     RECT  32.655 76.199 33.066 76.469 ;
     RECT  0.255 74.909 0.537 76.697 ;
     RECT  32.655 76.469 32.937 76.697 ;
     RECT  38.055 42.719 38.337 76.697 ;
     RECT  1.26 76.315 29.178 76.739 ;
     RECT  30.78 76.469 31.302 76.739 ;
     RECT  1.26 76.739 27.666 76.781 ;
     RECT  15.588 76.781 27.666 76.847 ;
     RECT  1.26 76.781 14.814 76.883 ;
     RECT  15.588 76.847 27.537 76.883 ;
     RECT  15.588 76.883 26.478 76.919 ;
     RECT  29.088 76.739 29.178 76.919 ;
     RECT  31.284 76.739 31.302 76.919 ;
     RECT  15.588 76.919 26.226 76.925 ;
     RECT  10.152 76.883 14.814 76.942 ;
     RECT  0.447 76.697 0.537 76.967 ;
     RECT  27.447 76.883 27.537 76.967 ;
     RECT  32.847 76.697 32.937 76.967 ;
     RECT  38.247 76.697 38.337 76.967 ;
     RECT  10.152 76.942 10.206 76.973 ;
     RECT  10.944 76.942 14.814 76.973 ;
     RECT  15.588 76.925 25.722 76.973 ;
     RECT  1.26 76.883 9.234 77.021 ;
     RECT  10.944 76.973 12.294 77.021 ;
     RECT  15.588 76.973 20.142 77.021 ;
     RECT  21.528 76.973 25.722 77.021 ;
     RECT  1.332 77.021 9.234 77.069 ;
     RECT  10.188 76.973 10.206 77.069 ;
     RECT  13.032 76.973 14.814 77.069 ;
     RECT  15.912 77.021 20.142 77.069 ;
     RECT  21.528 77.021 24.822 77.069 ;
     RECT  25.704 77.021 25.722 77.069 ;
     RECT  1.548 77.069 1.674 77.117 ;
     RECT  2.772 77.069 4.014 77.117 ;
     RECT  4.896 77.069 9.234 77.117 ;
     RECT  11.196 77.021 11.754 77.117 ;
     RECT  13.608 77.069 14.814 77.117 ;
     RECT  16.344 77.069 20.07 77.117 ;
     RECT  1.548 77.117 1.602 77.165 ;
     RECT  5.004 77.117 9.234 77.165 ;
     RECT  14.796 77.117 14.814 77.165 ;
     RECT  16.344 77.117 18.162 77.165 ;
     RECT  2.772 77.117 2.898 77.213 ;
     RECT  5.58 77.165 9.234 77.213 ;
     RECT  1.548 77.165 1.566 77.261 ;
     RECT  2.88 77.213 2.898 77.261 ;
     RECT  5.58 77.213 7.938 77.261 ;
     RECT  5.58 77.261 6.786 77.309 ;
     RECT  7.92 77.261 7.938 77.309 ;
     RECT  11.412 77.117 11.754 77.309 ;
     RECT  16.38 77.165 17.586 77.309 ;
     RECT  21.636 77.069 24.822 77.309 ;
     RECT  11.736 77.309 11.754 77.357 ;
     RECT  16.38 77.309 17.262 77.357 ;
     RECT  22.68 77.309 23.31 77.357 ;
     RECT  9.216 77.213 9.234 77.405 ;
     RECT  22.68 77.357 23.058 77.405 ;
     RECT  6.048 77.309 6.786 77.453 ;
     RECT  16.884 77.357 17.262 77.453 ;
     RECT  20.052 77.117 20.07 77.453 ;
     RECT  24.264 77.309 24.282 77.453 ;
     RECT  6.192 77.453 6.21 77.549 ;
     RECT  16.884 77.453 16.902 77.549 ;
     RECT  21.636 77.309 21.654 77.549 ;
    LAYER M4 ;
     RECT  0.248 0.528 0.352 76.692 ;
     RECT  0.352 0.798 0.44 76.692 ;
     RECT  0.44 0.798 0.544 76.962 ;
     RECT  0.544 75.984 0.661 76.962 ;
     RECT  0.661 75.984 0.853 77.016 ;
     RECT  0.544 65.28 1.073 65.304 ;
     RECT  0.544 74.592 1.573 75 ;
     RECT  0.853 75.984 1.573 77.256 ;
     RECT  1.573 74.592 1.577 77.256 ;
     RECT  1.621 72.96 1.669 72.984 ;
     RECT  0.544 70.944 1.685 70.968 ;
     RECT  1.669 72.96 1.925 73.416 ;
     RECT  1.577 74.592 1.925 77.208 ;
     RECT  0.544 68.4 2.657 68.424 ;
     RECT  1.925 72.96 2.836 77.208 ;
     RECT  2.365 63.792 2.867 63.816 ;
     RECT  2.836 72.96 2.965 77.256 ;
     RECT  2.965 72.816 3.539 77.256 ;
     RECT  3.539 72.816 3.661 77.16 ;
     RECT  3.553 70.656 3.701 70.68 ;
     RECT  3.74 26.688 3.827 26.712 ;
     RECT  3.697 58.08 3.875 58.104 ;
     RECT  3.877 61.584 3.961 61.608 ;
     RECT  3.941 33.264 4.025 33.288 ;
     RECT  4.021 70.704 4.117 71.208 ;
     RECT  4.076 12.912 4.163 12.936 ;
     RECT  3.661 72.672 4.213 77.16 ;
     RECT  4.117 70.704 4.241 71.304 ;
     RECT  4.241 70.944 4.261 71.304 ;
     RECT  4.213 72.576 4.261 77.16 ;
     RECT  4.261 65.616 4.349 65.64 ;
     RECT  4.261 70.944 4.444 77.16 ;
     RECT  4.412 68.688 4.499 68.712 ;
     RECT  4.444 71.28 4.529 77.16 ;
     RECT  4.309 7.44 4.547 7.464 ;
     RECT  4.201 21.6 4.547 21.624 ;
     RECT  4.417 28.896 4.547 28.92 ;
     RECT  3.925 59.808 4.637 59.832 ;
     RECT  4.669 49.392 5.173 49.416 ;
     RECT  4.741 59.232 5.269 59.784 ;
     RECT  4.117 58.128 5.413 58.152 ;
     RECT  4.529 71.376 5.509 77.16 ;
     RECT  5.509 70.944 5.569 77.16 ;
     RECT  5.065 9.792 5.648 9.816 ;
     RECT  4.748 26.928 5.648 26.952 ;
     RECT  5.509 28.272 5.648 28.296 ;
     RECT  5.036 37.488 5.648 37.512 ;
     RECT  5.057 42.144 5.648 42.168 ;
     RECT  5.057 43.344 5.648 43.368 ;
     RECT  5.173 49.344 5.648 49.416 ;
     RECT  5.461 53.904 5.648 53.928 ;
     RECT  5.413 57.6 5.648 58.152 ;
     RECT  5.269 59.136 5.648 59.784 ;
     RECT  5.132 69.648 5.648 69.672 ;
     RECT  5.569 70.944 5.648 77.304 ;
     RECT  5.648 0.528 5.752 77.304 ;
     RECT  5.752 0.798 5.944 77.304 ;
     RECT  5.944 69.552 6.037 77.304 ;
     RECT  5.944 67.824 6.083 68.232 ;
     RECT  6.037 69.552 6.14 77.448 ;
     RECT  6.14 69.552 6.227 77.544 ;
     RECT  5.944 58.704 6.265 59.16 ;
     RECT  5.944 51.888 6.275 51.912 ;
     RECT  5.944 21.648 6.323 22.2 ;
     RECT  5.944 33.504 6.323 33.624 ;
     RECT  5.944 46.416 6.419 46.776 ;
     RECT  5.944 53.568 6.563 54.12 ;
     RECT  5.944 56.688 6.611 56.904 ;
     RECT  6.563 53.904 6.653 54.12 ;
     RECT  6.227 69.552 6.689 77.448 ;
     RECT  6.323 21.648 6.717 21.672 ;
     RECT  6.689 71.376 6.797 77.448 ;
     RECT  6.797 71.376 6.803 77.4 ;
     RECT  5.944 50.736 6.833 50.76 ;
     RECT  6.265 59.136 6.833 59.16 ;
     RECT  5.944 14.784 6.913 14.904 ;
     RECT  5.944 37.584 6.913 37.608 ;
     RECT  6.611 56.88 6.913 56.904 ;
     RECT  5.944 49.344 6.941 49.368 ;
     RECT  6.083 67.824 6.995 67.848 ;
     RECT  6.653 54.096 7.013 54.12 ;
     RECT  6.997 29.088 7.085 29.112 ;
     RECT  6.997 65.184 7.157 65.208 ;
     RECT  7.141 9.36 7.229 9.384 ;
     RECT  6.689 70.08 7.229 70.104 ;
     RECT  7.189 42.72 7.273 42.744 ;
     RECT  7.292 19.2 7.379 19.224 ;
     RECT  7.261 30.816 7.427 30.84 ;
     RECT  7.429 15.072 7.516 15.096 ;
     RECT  7.429 47.28 7.516 47.304 ;
     RECT  7.436 41.04 7.523 41.064 ;
     RECT  5.944 3.312 7.549 3.336 ;
     RECT  7.484 13.056 7.571 13.08 ;
     RECT  5.944 43.872 7.628 43.896 ;
     RECT  7.628 43.728 7.715 43.896 ;
     RECT  7.549 2.784 7.717 3.336 ;
     RECT  7.676 65.616 7.763 65.64 ;
     RECT  6.803 71.376 7.765 77.256 ;
     RECT  7.685 58.704 7.769 58.728 ;
     RECT  7.765 71.376 7.813 77.304 ;
     RECT  7.868 39.168 7.955 39.192 ;
     RECT  7.868 52.32 7.955 52.344 ;
     RECT  7.813 71.376 8.005 77.4 ;
     RECT  7.715 43.872 8.017 43.896 ;
     RECT  6.323 33.6 8.021 33.624 ;
     RECT  8.017 43.872 8.057 44.328 ;
     RECT  8.005 70.704 8.147 77.4 ;
     RECT  7.717 2.784 8.165 3.864 ;
     RECT  6.949 37.632 8.204 38.184 ;
     RECT  8.161 50.736 8.273 50.76 ;
     RECT  8.005 55.824 8.273 55.848 ;
     RECT  8.204 37.584 8.291 38.184 ;
     RECT  8.437 68.688 8.485 68.712 ;
     RECT  8.485 67.872 8.525 68.712 ;
     RECT  8.525 67.872 8.569 67.896 ;
     RECT  8.557 54.768 8.641 54.792 ;
     RECT  8.165 2.784 8.737 3.336 ;
     RECT  7.868 63.168 8.773 63.192 ;
     RECT  8.665 66.768 8.773 66.792 ;
     RECT  8.773 62.736 8.809 63.192 ;
     RECT  8.732 65.376 8.819 65.4 ;
     RECT  8.291 38.16 8.849 38.184 ;
     RECT  8.809 62.736 8.857 63.288 ;
     RECT  8.857 63.264 8.915 63.288 ;
     RECT  7.801 27.312 8.921 27.336 ;
     RECT  8.876 42.72 8.963 42.744 ;
     RECT  8.917 39.888 9.001 39.912 ;
     RECT  8.725 57.024 9.065 57.048 ;
     RECT  9.02 47.28 9.107 47.304 ;
     RECT  8.965 49.584 9.137 49.608 ;
     RECT  9.061 52.32 9.148 52.344 ;
     RECT  8.725 12.864 9.164 12.888 ;
     RECT  8.773 66.576 9.168 66.792 ;
     RECT  9.164 12.864 9.205 13.512 ;
     RECT  8.147 71.232 9.245 77.4 ;
     RECT  9.205 12.864 9.251 14.376 ;
     RECT  9.241 67.248 9.347 67.272 ;
     RECT  9.251 14.352 9.353 14.376 ;
     RECT  8.057 44.304 9.397 44.328 ;
     RECT  9.404 63.744 9.491 63.768 ;
     RECT  8.557 58.656 9.565 58.68 ;
     RECT  9.245 71.232 9.565 77.064 ;
     RECT  5.944 7.872 9.589 7.896 ;
     RECT  9.457 0.144 9.637 0.168 ;
     RECT  9.565 58.128 9.644 58.68 ;
     RECT  9.493 69.312 9.677 69.336 ;
     RECT  9.397 44.016 9.685 44.328 ;
     RECT  9.644 58.128 9.692 59.064 ;
     RECT  9.692 57.552 9.731 59.064 ;
     RECT  9.731 57.552 9.779 58.104 ;
     RECT  9.685 53.616 9.821 53.64 ;
     RECT  9.301 18.72 9.829 18.744 ;
     RECT  8.809 30.816 9.857 30.84 ;
     RECT  9.565 71.136 9.877 77.064 ;
     RECT  9.829 18.72 9.916 19.56 ;
     RECT  9.685 43.728 10.019 44.328 ;
     RECT  8.821 61.584 10.037 61.608 ;
     RECT  9.973 42.72 10.06 42.744 ;
     RECT  9.877 71.088 10.309 77.064 ;
     RECT  10.165 68.352 10.357 68.376 ;
     RECT  10.019 44.304 10.364 44.328 ;
     RECT  8.869 15.456 10.453 15.48 ;
     RECT  8.737 2.016 10.537 3.336 ;
     RECT  9.251 12.864 10.549 12.888 ;
     RECT  10.261 60.672 10.781 60.696 ;
     RECT  10.537 2.016 10.789 3.384 ;
     RECT  9.925 25.056 10.825 25.08 ;
     RECT  10.309 70.704 10.825 77.064 ;
     RECT  9.779 58.08 10.885 58.104 ;
     RECT  10.321 59.28 10.885 59.304 ;
     RECT  10.549 11.952 10.925 12.888 ;
     RECT  5.944 6.768 10.933 6.792 ;
     RECT  10.925 11.952 10.933 13.368 ;
     RECT  10.46 46.992 10.933 47.016 ;
     RECT  10.177 56.928 10.933 56.952 ;
     RECT  10.885 58.08 10.933 59.304 ;
     RECT  10.825 70.512 11.029 77.064 ;
     RECT  9.637 0.048 11.048 0.168 ;
     RECT  10.789 2.016 11.048 3.864 ;
     RECT  10.933 6.768 11.048 6.84 ;
     RECT  9.589 7.872 11.048 8.472 ;
     RECT  10.892 9.744 11.048 9.768 ;
     RECT  10.933 11.952 11.048 13.608 ;
     RECT  10.453 15.456 11.048 15.816 ;
     RECT  9.916 18.72 11.048 18.744 ;
     RECT  10.285 22.176 11.048 22.2 ;
     RECT  10.825 24.576 11.048 25.08 ;
     RECT  10.825 26.784 11.048 26.808 ;
     RECT  10.969 27.936 11.048 27.96 ;
     RECT  10.261 37.584 11.048 37.608 ;
     RECT  10.364 44.304 11.048 44.904 ;
     RECT  10.933 46.224 11.048 47.016 ;
     RECT  10.837 49.536 11.048 49.56 ;
     RECT  10.261 50.88 11.048 50.904 ;
     RECT  10.609 52.992 11.048 53.592 ;
     RECT  10.309 54.672 11.048 54.888 ;
     RECT  10.933 56.928 11.048 59.304 ;
     RECT  10.781 60.432 11.048 60.696 ;
     RECT  10.309 62.16 11.048 62.184 ;
     RECT  10.429 63.264 11.048 63.288 ;
     RECT  10.357 68.064 11.048 68.376 ;
     RECT  11.029 70.512 11.048 77.112 ;
     RECT  11.048 0.048 11.077 77.112 ;
     RECT  11.077 0.048 11.125 77.208 ;
     RECT  11.125 0.048 11.344 77.304 ;
     RECT  11.344 10.56 11.369 15.72 ;
     RECT  11.344 70.08 11.413 77.304 ;
     RECT  11.344 46.752 11.657 46.824 ;
     RECT  11.344 63.744 11.747 63.768 ;
     RECT  11.344 57.024 11.773 58.728 ;
     RECT  11.344 43.68 11.795 43.704 ;
     RECT  11.773 58.704 11.837 58.728 ;
     RECT  11.344 40.992 11.843 41.016 ;
     RECT  11.413 70.08 11.843 77.352 ;
     RECT  11.344 18.72 11.945 18.744 ;
     RECT  11.369 10.56 11.98 13.032 ;
     RECT  11.773 57.024 11.981 57.624 ;
     RECT  11.344 22.752 11.987 22.872 ;
     RECT  11.344 60.72 11.987 60.744 ;
     RECT  11.344 37.344 12.025 37.368 ;
     RECT  11.344 62.16 12.035 62.616 ;
     RECT  11.344 64.8 12.035 67.848 ;
     RECT  11.98 10.56 12.125 12.888 ;
     RECT  12.035 65.568 12.241 67.848 ;
     RECT  11.344 1.392 12.275 3.96 ;
     RECT  12.241 66.144 12.275 67.848 ;
     RECT  11.843 70.08 12.313 77.016 ;
     RECT  11.344 26.208 12.325 26.76 ;
     RECT  11.981 57.024 12.371 57.24 ;
     RECT  12.371 57.024 12.377 57.048 ;
     RECT  12.275 66.144 12.377 67.32 ;
     RECT  12.325 25.68 12.413 26.76 ;
     RECT  12.337 50.736 12.449 50.76 ;
     RECT  12.377 66.72 12.449 67.32 ;
     RECT  12.38 21.264 12.467 21.288 ;
     RECT  11.344 0.048 12.517 0.264 ;
     RECT  12.275 1.392 12.517 3.384 ;
     RECT  11.657 46.8 12.556 46.824 ;
     RECT  12.469 61.776 12.556 61.8 ;
     RECT  11.987 22.848 12.557 22.872 ;
     RECT  12.413 26.64 12.563 26.76 ;
     RECT  12.409 32.544 12.563 32.568 ;
     RECT  11.344 27.936 12.661 27.96 ;
     RECT  12.613 58.8 12.7 59.208 ;
     RECT  12.661 27.936 12.701 28.488 ;
     RECT  12.373 49.344 12.709 49.368 ;
     RECT  12.7 58.8 12.709 58.824 ;
     RECT  12.661 45.312 12.748 45.336 ;
     RECT  12.709 49.344 12.796 49.896 ;
     RECT  12.757 39.6 12.844 39.624 ;
     RECT  12.733 30.672 12.881 30.792 ;
     RECT  11.344 5.904 12.917 5.928 ;
     RECT  12.881 30.672 12.947 30.696 ;
     RECT  12.86 69.552 12.947 69.576 ;
     RECT  12.313 70.704 12.997 77.016 ;
     RECT  12.125 11.04 13.045 12.888 ;
     RECT  11.369 14.208 13.045 15.72 ;
     RECT  13.045 11.04 13.061 15.72 ;
     RECT  13.061 13.632 13.091 15.72 ;
     RECT  12.701 28.464 13.093 28.488 ;
     RECT  11.344 47.808 13.097 47.832 ;
     RECT  12.697 63.264 13.097 63.288 ;
     RECT  13.045 41.856 13.132 41.88 ;
     RECT  13.091 13.632 13.133 13.656 ;
     RECT  13.093 28.464 13.133 28.584 ;
     RECT  13.129 43.248 13.213 43.272 ;
     RECT  12.563 26.64 13.277 26.664 ;
     RECT  13.285 37.344 13.372 37.368 ;
     RECT  13.093 18.672 13.379 18.696 ;
     RECT  13.309 55.248 13.427 55.272 ;
     RECT  12.997 23.136 13.429 23.16 ;
     RECT  12.997 70.704 13.436 77.064 ;
     RECT  11.344 7.776 13.477 8.472 ;
     RECT  13.429 23.136 13.516 23.592 ;
     RECT  12.449 66.72 13.523 67.272 ;
     RECT  13.436 70.128 13.523 77.064 ;
     RECT  13.309 41.04 13.565 41.064 ;
     RECT  13.093 49.2 13.565 49.224 ;
     RECT  13.523 70.752 13.565 77.064 ;
     RECT  13.565 70.944 13.573 77.064 ;
     RECT  13.561 58.704 13.58 58.728 ;
     RECT  13.061 11.04 13.601 12.552 ;
     RECT  13.523 66.72 13.621 66.84 ;
     RECT  13.58 57.792 13.645 58.728 ;
     RECT  13.645 57.792 13.667 57.816 ;
     RECT  13.621 66.672 13.667 66.84 ;
     RECT  13.573 70.944 13.681 77.112 ;
     RECT  13.628 60.864 13.715 60.888 ;
     RECT  11.344 53.472 13.717 53.496 ;
     RECT  13.717 53.04 13.745 53.496 ;
     RECT  13.669 44.448 13.753 44.472 ;
     RECT  12.517 0.048 13.885 3.384 ;
     RECT  13.477 7.776 13.889 9.432 ;
     RECT  13.745 53.04 13.993 53.064 ;
     RECT  13.964 25.968 14.051 26.232 ;
     RECT  13.885 0.048 14.053 3.912 ;
     RECT  13.669 6 14.101 6.024 ;
     RECT  13.667 66.672 14.101 66.744 ;
     RECT  14.021 50.16 14.105 50.184 ;
     RECT  14.053 54.096 14.149 54.12 ;
     RECT  14.101 66.624 14.185 66.744 ;
     RECT  13.993 52.176 14.195 53.064 ;
     RECT  14.149 54.096 14.236 54.168 ;
     RECT  13.133 28.56 14.245 28.584 ;
     RECT  14.197 44.976 14.293 45 ;
     RECT  14.245 27.744 14.332 28.584 ;
     RECT  14.051 26.208 14.357 26.232 ;
     RECT  14.293 44.976 14.38 45.432 ;
     RECT  14.195 52.368 14.428 53.064 ;
     RECT  14.053 0.048 14.437 3.96 ;
     RECT  14.101 5.088 14.437 6.024 ;
     RECT  13.601 12.528 14.485 12.552 ;
     RECT  14.461 30.912 14.492 30.936 ;
     RECT  14.029 33.6 14.497 33.624 ;
     RECT  14.497 33.6 14.533 33.864 ;
     RECT  13.573 34.896 14.533 34.92 ;
     RECT  14.437 35.904 14.533 35.928 ;
     RECT  14.533 33.6 14.537 34.92 ;
     RECT  14.38 44.976 14.537 45 ;
     RECT  14.236 54.096 14.537 54.12 ;
     RECT  14.588 24.864 14.605 24.888 ;
     RECT  14.533 35.904 14.627 36.504 ;
     RECT  14.485 12.528 14.641 13.08 ;
     RECT  14.437 0.048 14.645 6.024 ;
     RECT  14.605 24.384 14.675 24.888 ;
     RECT  14.492 30.768 14.677 30.936 ;
     RECT  13.681 71.04 14.677 77.112 ;
     RECT  14.533 46.752 14.681 46.776 ;
     RECT  14.428 53.04 14.681 53.064 ;
     RECT  14.332 28.56 14.717 28.584 ;
     RECT  14.677 70.944 14.725 77.112 ;
     RECT  14.627 35.904 14.789 35.928 ;
     RECT  14.461 62.688 14.789 62.712 ;
     RECT  14.677 30.768 14.819 31.032 ;
     RECT  14.713 32.448 14.819 32.472 ;
     RECT  14.537 33.84 14.819 34.92 ;
     RECT  14.677 59.664 14.819 59.688 ;
     RECT  14.741 53.568 14.825 53.592 ;
     RECT  14.725 70.944 14.825 77.16 ;
     RECT  14.185 66.624 14.857 66.648 ;
     RECT  14.819 30.768 14.861 30.792 ;
     RECT  14.675 24.384 14.867 24.408 ;
     RECT  13.601 11.04 14.869 11.064 ;
     RECT  14.821 37.68 14.905 37.704 ;
     RECT  14.857 66.144 14.941 66.648 ;
     RECT  14.876 14.064 14.963 14.088 ;
     RECT  14.924 19.2 15.011 19.656 ;
     RECT  14.924 24.24 15.011 24.264 ;
     RECT  14.924 67.968 15.011 67.992 ;
     RECT  14.819 34.8 15.029 34.92 ;
     RECT  14.725 58.656 15.041 58.68 ;
     RECT  13.957 69.504 15.073 69.528 ;
     RECT  14.869 11.04 15.077 11.16 ;
     RECT  15.02 63.216 15.107 63.24 ;
     RECT  15.073 57.6 15.109 57.624 ;
     RECT  15.029 34.8 15.113 35.4 ;
     RECT  14.825 70.944 15.157 77.064 ;
     RECT  14.645 5.616 15.181 6.024 ;
     RECT  13.516 23.136 15.185 23.16 ;
     RECT  15.109 57.456 15.196 57.624 ;
     RECT  15.181 5.616 15.217 6.792 ;
     RECT  15.196 57.6 15.251 57.624 ;
     RECT  15.077 11.136 15.308 11.16 ;
     RECT  14.641 12.48 15.308 13.08 ;
     RECT  15.308 11.136 15.395 13.08 ;
     RECT  15.317 27.84 15.401 27.864 ;
     RECT  15.073 69.504 15.433 69.576 ;
     RECT  13.091 15.072 15.437 15.72 ;
     RECT  15.113 34.8 15.481 34.92 ;
     RECT  15.397 57.792 15.481 57.816 ;
     RECT  15.433 69.024 15.541 69.576 ;
     RECT  15.157 70.656 15.541 77.064 ;
     RECT  15.541 69.024 15.733 77.064 ;
     RECT  14.941 66.624 15.893 66.648 ;
     RECT  15.253 19.152 15.973 19.176 ;
     RECT  15.685 39.6 15.973 39.624 ;
     RECT  15.217 5.616 16.045 6.888 ;
     RECT  15.973 39.072 16.069 39.912 ;
     RECT  15.145 41.04 16.069 41.064 ;
     RECT  15.733 68.976 16.069 77.064 ;
     RECT  16.069 38.784 16.076 39.912 ;
     RECT  16.021 51.504 16.117 51.528 ;
     RECT  14.645 0.048 16.165 4.392 ;
     RECT  16.069 68.976 16.189 77.352 ;
     RECT  15.973 19.152 16.213 19.992 ;
     RECT  15.973 23.088 16.213 23.112 ;
     RECT  15.973 65.424 16.213 65.448 ;
     RECT  15.893 66.624 16.213 67.272 ;
     RECT  15.109 60.24 16.369 60.264 ;
     RECT  16.165 0.048 16.448 4.536 ;
     RECT  16.045 5.616 16.448 7.416 ;
     RECT  13.889 8.448 16.448 9.432 ;
     RECT  15.395 11.136 16.448 11.16 ;
     RECT  15.395 12.48 16.448 13.08 ;
     RECT  15.437 15.072 16.448 15.48 ;
     RECT  16.213 18.816 16.448 20.088 ;
     RECT  16.213 23.088 16.448 23.928 ;
     RECT  15.541 27.36 16.448 27.384 ;
     RECT  15.397 29.088 16.448 29.112 ;
     RECT  15.925 31.536 16.448 31.56 ;
     RECT  15.481 34.896 16.448 34.92 ;
     RECT  16.076 38.16 16.448 39.912 ;
     RECT  16.069 41.04 16.448 41.496 ;
     RECT  16.297 43.344 16.448 43.368 ;
     RECT  16.117 51.504 16.448 51.912 ;
     RECT  16.369 60.24 16.448 60.696 ;
     RECT  16.045 62.736 16.448 62.76 ;
     RECT  16.213 65.424 16.448 67.272 ;
     RECT  16.189 68.928 16.448 77.352 ;
     RECT  16.448 0.048 16.549 77.352 ;
     RECT  16.549 0.048 16.744 77.4 ;
     RECT  16.744 0.048 16.805 3.96 ;
     RECT  16.744 23.088 16.805 23.928 ;
     RECT  16.744 70.704 16.837 77.4 ;
     RECT  16.744 15.456 16.841 15.48 ;
     RECT  16.837 70.704 16.844 77.448 ;
     RECT  16.744 16.512 16.883 17.112 ;
     RECT  16.744 47.808 16.885 47.832 ;
     RECT  16.805 0.096 16.913 3.96 ;
     RECT  16.805 23.088 16.913 23.112 ;
     RECT  16.744 68.256 16.921 68.28 ;
     RECT  16.913 0.144 16.931 3.96 ;
     RECT  16.744 55.824 16.931 59.64 ;
     RECT  16.844 70.704 16.931 77.544 ;
     RECT  16.744 41.04 16.949 41.496 ;
     RECT  16.931 55.824 16.949 55.848 ;
     RECT  16.744 69.504 16.949 69.528 ;
     RECT  16.744 30.816 16.979 31.08 ;
     RECT  16.744 60.672 16.979 63.24 ;
     RECT  16.744 66.672 16.979 66.792 ;
     RECT  16.744 32.448 17.02 32.472 ;
     RECT  16.744 34.032 17.02 34.92 ;
     RECT  16.949 41.472 17.021 41.496 ;
     RECT  16.979 62.64 17.021 63.24 ;
     RECT  16.744 29.52 17.027 29.544 ;
     RECT  16.931 57.024 17.057 59.64 ;
     RECT  16.931 0.144 17.075 3.912 ;
     RECT  17.057 57.024 17.075 58.728 ;
     RECT  17.021 62.64 17.075 63.048 ;
     RECT  16.979 66.72 17.093 66.744 ;
     RECT  17.075 63.024 17.116 63.048 ;
     RECT  16.979 31.056 17.123 31.08 ;
     RECT  16.744 13.632 17.237 13.656 ;
     RECT  16.744 5.088 17.273 5.16 ;
     RECT  16.744 21.792 17.273 21.816 ;
     RECT  16.931 70.704 17.273 77.448 ;
     RECT  16.744 10.224 17.363 11.976 ;
     RECT  16.744 50.736 17.453 51.288 ;
     RECT  16.744 54.048 17.459 54.072 ;
     RECT  17.453 50.736 17.525 50.76 ;
     RECT  16.979 60.672 17.525 60.696 ;
     RECT  17.075 57.84 17.596 58.728 ;
     RECT  17.363 10.224 17.777 11.688 ;
     RECT  16.744 6.24 17.891 7.416 ;
     RECT  16.744 38.256 17.993 38.28 ;
     RECT  18.085 68.976 18.172 69 ;
     RECT  17.953 44.064 18.181 44.088 ;
     RECT  18.133 31.344 18.227 31.368 ;
     RECT  18.181 43.104 18.227 44.088 ;
     RECT  17.273 5.088 18.245 5.112 ;
     RECT  18.227 43.104 18.268 43.128 ;
     RECT  17.02 34.896 18.317 34.92 ;
     RECT  16.744 64.992 18.373 65.592 ;
     RECT  17.075 0.144 18.421 3.144 ;
     RECT  18.373 64.992 18.461 65.688 ;
     RECT  17.273 70.704 18.469 77.304 ;
     RECT  18.421 60.432 18.505 60.456 ;
     RECT  17.777 10.224 18.533 10.632 ;
     RECT  18.517 24.624 18.604 24.648 ;
     RECT  18.469 46.752 18.605 46.776 ;
     RECT  17.777 11.664 18.641 11.688 ;
     RECT  18.229 68.304 18.677 68.328 ;
     RECT  17.891 6.24 18.707 7.368 ;
     RECT  18.461 64.992 18.709 65.016 ;
     RECT  18.673 42.768 18.716 42.792 ;
     RECT  18.421 0.096 18.781 3.144 ;
     RECT  18.493 4.512 18.781 4.536 ;
     RECT  18.709 64.416 18.793 65.016 ;
     RECT  18.716 42.144 18.803 42.792 ;
     RECT  18.601 66.624 18.821 66.648 ;
     RECT  18.793 64.896 18.851 65.016 ;
     RECT  18.061 62.016 18.857 62.04 ;
     RECT  18.805 13.632 18.892 13.656 ;
     RECT  18.845 44.448 18.929 44.472 ;
     RECT  18.853 37.68 18.937 37.704 ;
     RECT  18.853 54.624 18.937 54.648 ;
     RECT  18.956 40.512 19.043 40.536 ;
     RECT  18.533 10.224 19.139 10.248 ;
     RECT  18.421 20.208 19.145 20.232 ;
     RECT  18.853 28.512 19.148 28.536 ;
     RECT  18.851 64.896 19.181 64.92 ;
     RECT  19.1 24.864 19.187 24.888 ;
     RECT  18.709 26.256 19.189 26.28 ;
     RECT  19.148 28.512 19.189 28.872 ;
     RECT  19.177 56.448 19.261 56.472 ;
     RECT  18.781 0.096 19.285 4.536 ;
     RECT  19.189 28.512 19.289 29.16 ;
     RECT  18.313 31.728 19.292 31.752 ;
     RECT  19.189 26.256 19.331 26.808 ;
     RECT  19.289 29.136 19.331 29.16 ;
     RECT  18.707 6.24 19.357 6.408 ;
     RECT  19.292 31.248 19.379 32.376 ;
     RECT  17.596 58.704 19.388 58.728 ;
     RECT  19.388 58.704 19.397 58.872 ;
     RECT  19.333 63.792 19.42 63.816 ;
     RECT  19.397 58.848 19.475 58.872 ;
     RECT  18.469 70.704 19.477 77.448 ;
     RECT  19.477 69.84 19.613 77.448 ;
     RECT  19.532 56.88 19.619 56.904 ;
     RECT  19.501 46.608 19.649 46.728 ;
     RECT  19.676 36.24 19.763 36.264 ;
     RECT  19.717 27.36 19.801 27.384 ;
     RECT  19.525 43.056 19.813 43.176 ;
     RECT  19.813 42.768 19.82 43.176 ;
     RECT  19.285 0.048 19.859 4.536 ;
     RECT  19.82 42.144 19.907 43.176 ;
     RECT  19.897 38.64 19.916 38.664 ;
     RECT  19.613 70.176 19.945 77.448 ;
     RECT  19.916 38.16 20.003 38.664 ;
     RECT  19.925 34.416 20.009 34.44 ;
     RECT  19.621 12.96 20.06 12.984 ;
     RECT  19.249 68.352 20.108 68.376 ;
     RECT  19.813 11.376 20.113 11.4 ;
     RECT  20.06 12.912 20.147 12.984 ;
     RECT  20.108 49.2 20.195 49.224 ;
     RECT  20.108 67.68 20.195 68.376 ;
     RECT  20.113 10.8 20.225 11.4 ;
     RECT  20.147 12.96 20.225 12.984 ;
     RECT  19.859 0.048 20.243 4.488 ;
     RECT  20.195 67.872 20.257 68.376 ;
     RECT  19.945 70.416 20.268 77.448 ;
     RECT  19.753 19.344 20.291 19.368 ;
     RECT  16.883 16.512 20.293 16.536 ;
     RECT  19.907 42.768 20.297 43.176 ;
     RECT  20.245 47.472 20.332 47.496 ;
     RECT  20.297 43.152 20.333 43.176 ;
     RECT  20.149 64.416 20.339 64.44 ;
     RECT  20.197 60.288 20.369 60.312 ;
     RECT  20.293 15.648 20.387 16.536 ;
     RECT  20.225 11.376 20.396 11.4 ;
     RECT  20.257 67.872 20.435 68.424 ;
     RECT  20.435 67.872 20.441 68.376 ;
     RECT  19.916 45.552 20.473 45.576 ;
     RECT  20.396 11.376 20.483 11.544 ;
     RECT  20.396 20.208 20.483 20.232 ;
     RECT  20.113 52.464 20.485 52.488 ;
     RECT  20.268 70.416 20.513 77.544 ;
     RECT  20.437 39.744 20.521 39.768 ;
     RECT  20.473 45.552 20.521 46.152 ;
     RECT  20.387 16.464 20.531 16.536 ;
     RECT  20.485 51.84 20.531 52.488 ;
     RECT  20.465 55.2 20.549 55.224 ;
     RECT  20.521 46.128 20.557 46.152 ;
     RECT  20.483 11.376 20.657 11.4 ;
     RECT  20.636 65.52 20.723 65.544 ;
     RECT  20.653 58.752 20.725 58.776 ;
     RECT  20.293 13.488 20.729 13.512 ;
     RECT  20.645 37.632 20.729 37.656 ;
     RECT  20.645 62.64 20.729 62.664 ;
     RECT  20.243 0.048 20.771 4.008 ;
     RECT  20.725 30.816 20.819 30.84 ;
     RECT  20.545 60.768 20.933 60.792 ;
     RECT  20.725 58.704 20.977 58.776 ;
     RECT  20.473 38.688 21.085 38.712 ;
     RECT  21.121 49.056 21.25 49.08 ;
     RECT  21.25 49.008 21.301 49.08 ;
     RECT  21.301 49.008 21.337 49.128 ;
     RECT  20.581 56.832 21.337 56.856 ;
     RECT  21.157 50.784 21.397 50.808 ;
     RECT  20.531 51.84 21.397 52.104 ;
     RECT  20.977 58.704 21.397 59.304 ;
     RECT  21.373 18.768 21.445 18.792 ;
     RECT  21.02 35.904 21.509 35.928 ;
     RECT  21.397 50.784 21.517 52.104 ;
     RECT  19.357 5.664 21.541 6.408 ;
     RECT  21.061 66.624 21.589 66.648 ;
     RECT  20.441 67.92 21.589 68.376 ;
     RECT  21.397 69.456 21.589 69.576 ;
     RECT  21.625 22.848 21.637 22.872 ;
     RECT  20.513 70.608 21.665 77.544 ;
     RECT  21.337 56.832 21.685 57.624 ;
     RECT  21.517 50.688 21.692 52.104 ;
     RECT  21.692 50.688 21.725 53.016 ;
     RECT  21.541 5.664 21.733 6.84 ;
     RECT  20.905 34.224 21.733 34.248 ;
     RECT  21.085 38.688 21.733 39 ;
     RECT  20.933 60.768 21.733 61.032 ;
     RECT  21.589 67.92 21.733 69.576 ;
     RECT  21.665 70.608 21.733 77.4 ;
     RECT  20.771 0.048 21.848 3.96 ;
     RECT  21.733 5.472 21.848 6.84 ;
     RECT  20.725 9.504 21.848 9.528 ;
     RECT  21.349 13.056 21.848 13.08 ;
     RECT  20.531 16.512 21.848 16.536 ;
     RECT  21.445 18.192 21.848 18.792 ;
     RECT  21.253 20.304 21.848 20.328 ;
     RECT  21.637 22.08 21.848 22.872 ;
     RECT  21.637 24.912 21.848 24.936 ;
     RECT  19.331 26.256 21.848 26.28 ;
     RECT  21.373 29.664 21.848 29.688 ;
     RECT  21.733 33.264 21.848 34.248 ;
     RECT  21.509 35.328 21.848 35.928 ;
     RECT  21.733 38.4 21.848 39 ;
     RECT  21.685 41.616 21.848 41.64 ;
     RECT  21.437 45.024 21.848 45.048 ;
     RECT  21.049 46.704 21.848 46.728 ;
     RECT  21.337 49.008 21.848 49.56 ;
     RECT  21.725 50.688 21.848 53.592 ;
     RECT  21.553 55.296 21.848 55.32 ;
     RECT  21.685 56.352 21.848 57.624 ;
     RECT  21.397 58.656 21.848 59.304 ;
     RECT  21.733 60.768 21.848 61.224 ;
     RECT  20.869 63.216 21.848 63.24 ;
     RECT  21.589 66.624 21.848 66.792 ;
     RECT  21.733 67.872 21.848 77.4 ;
     RECT  21.848 0.048 22.144 77.4 ;
     RECT  22.144 69.84 22.169 70.68 ;
     RECT  22.144 60.336 22.259 61.608 ;
     RECT  22.259 60.432 22.285 61.608 ;
     RECT  22.144 47.328 22.355 47.352 ;
     RECT  22.144 16.8 22.396 20.328 ;
     RECT  22.144 53.52 22.403 53.784 ;
     RECT  22.144 58.704 22.421 58.824 ;
     RECT  22.144 42.768 22.429 42.792 ;
     RECT  22.285 60.432 22.499 60.456 ;
     RECT  22.144 49.536 22.547 49.656 ;
     RECT  22.396 17.52 22.601 20.328 ;
     RECT  22.144 54.768 22.601 54.792 ;
     RECT  22.144 0.048 22.637 6.84 ;
     RECT  22.421 58.704 22.709 58.728 ;
     RECT  22.144 8.976 22.739 9.096 ;
     RECT  22.601 18.192 22.787 20.328 ;
     RECT  22.144 23.088 22.787 23.976 ;
     RECT  22.547 49.536 22.835 49.56 ;
     RECT  22.144 66.72 22.883 68.664 ;
     RECT  22.144 63.216 22.889 63.816 ;
     RECT  22.144 32.784 22.897 33.288 ;
     RECT  22.883 67.92 22.897 68.664 ;
     RECT  22.144 56.352 22.931 57.672 ;
     RECT  22.144 71.76 22.933 77.4 ;
     RECT  22.403 53.52 22.961 53.544 ;
     RECT  22.931 56.352 22.969 57.48 ;
     RECT  22.144 34.896 22.979 34.92 ;
     RECT  22.787 23.088 22.997 23.784 ;
     RECT  22.969 56.352 23.033 56.856 ;
     RECT  22.933 71.76 23.069 77.448 ;
     RECT  22.897 33.072 23.075 33.288 ;
     RECT  22.889 63.216 23.075 63.24 ;
     RECT  22.897 67.92 23.171 68.424 ;
     RECT  22.144 13.056 23.173 13.08 ;
     RECT  22.169 70.128 23.221 70.68 ;
     RECT  22.144 46.128 23.267 46.152 ;
     RECT  23.173 12.912 23.293 13.08 ;
     RECT  22.144 38.688 23.315 39 ;
     RECT  23.324 31.536 23.345 31.56 ;
     RECT  22.997 23.472 23.356 23.784 ;
     RECT  22.637 4.464 23.363 6.84 ;
     RECT  23.245 51.312 23.363 51.336 ;
     RECT  22.787 19.344 23.429 20.328 ;
     RECT  23.345 31.392 23.429 31.56 ;
     RECT  22.285 61.584 23.429 61.608 ;
     RECT  23.42 10.8 23.461 10.824 ;
     RECT  23.356 23.76 23.609 23.784 ;
     RECT  22.637 0.144 23.641 3.144 ;
     RECT  22.883 66.72 23.641 66.744 ;
     RECT  23.363 4.464 23.651 5.16 ;
     RECT  23.069 71.808 23.747 77.448 ;
     RECT  23.461 10.656 23.753 10.824 ;
     RECT  23.651 5.088 23.788 5.16 ;
     RECT  23.461 34.752 23.789 34.776 ;
     RECT  23.221 70.128 23.789 70.728 ;
     RECT  23.641 66.144 23.821 66.744 ;
     RECT  23.789 70.128 23.825 70.152 ;
     RECT  23.429 31.536 23.861 31.56 ;
     RECT  23.365 53.568 23.861 53.688 ;
     RECT  23.747 71.856 23.869 77.448 ;
     RECT  23.753 10.8 23.929 10.824 ;
     RECT  23.557 11.856 23.929 11.88 ;
     RECT  23.821 65.712 23.929 66.744 ;
     RECT  23.641 9.648 23.939 9.672 ;
     RECT  23.852 55.68 23.939 55.704 ;
     RECT  23.315 38.688 23.941 38.712 ;
     RECT  23.605 44.208 23.948 44.232 ;
     RECT  23.921 46.512 24.005 46.536 ;
     RECT  23.921 53.76 24.005 54.072 ;
     RECT  23.929 65.568 24.005 66.744 ;
     RECT  24.005 65.568 24.013 65.736 ;
     RECT  23.941 37.488 24.028 37.512 ;
     RECT  23.948 44.208 24.035 44.856 ;
     RECT  23.533 7.968 24.037 7.992 ;
     RECT  23.929 10.8 24.083 11.88 ;
     RECT  23.171 68.352 24.083 68.424 ;
     RECT  24.037 7.968 24.131 8.664 ;
     RECT  23.653 62.736 24.131 62.76 ;
     RECT  23.797 48.672 24.181 48.696 ;
     RECT  24.188 64.032 24.275 64.056 ;
     RECT  23.293 12.912 24.277 12.936 ;
     RECT  23.869 72.576 24.293 77.448 ;
     RECT  23.788 5.136 24.329 5.16 ;
     RECT  24.253 59.28 24.337 59.304 ;
     RECT  24.181 68.976 24.371 69 ;
     RECT  24.181 48.672 24.373 49.512 ;
     RECT  24.325 16.512 24.412 16.536 ;
     RECT  23.641 0.048 24.469 3.144 ;
     RECT  24.083 11.664 24.515 11.88 ;
     RECT  24.373 47.856 24.541 49.512 ;
     RECT  24.005 53.76 24.553 53.784 ;
     RECT  24.565 41.28 24.649 41.304 ;
     RECT  24.649 40.992 24.652 41.304 ;
     RECT  24.541 47.424 24.653 49.512 ;
     RECT  23.075 33.072 24.659 33.096 ;
     RECT  24.131 7.968 24.707 7.992 ;
     RECT  23.941 38.592 24.709 38.712 ;
     RECT  24.652 40.992 24.733 41.064 ;
     RECT  23.713 26.784 24.829 26.808 ;
     RECT  24.293 72.576 24.833 77.304 ;
     RECT  24.709 38.592 24.901 39.336 ;
     RECT  24.005 66.72 24.937 66.744 ;
     RECT  24.901 38.208 24.985 39.336 ;
     RECT  24.653 47.856 25.049 49.512 ;
     RECT  24.733 41.04 25.091 41.064 ;
     RECT  24.833 72.576 25.1 77.064 ;
     RECT  24.085 14.784 25.121 14.808 ;
     RECT  24.829 26.784 25.139 27.384 ;
     RECT  23.965 29.712 25.153 29.736 ;
     RECT  25.153 29.664 25.154 29.736 ;
     RECT  25.093 34.368 25.18 34.392 ;
     RECT  24.793 5.088 25.187 5.112 ;
     RECT  25.1 72.336 25.187 77.064 ;
     RECT  25.154 29.664 25.331 29.688 ;
     RECT  25.244 60.192 25.331 60.216 ;
     RECT  24.757 55.248 25.373 55.272 ;
     RECT  25.429 19.2 25.517 19.224 ;
     RECT  24.937 66.72 25.517 67.272 ;
     RECT  25.187 72.816 25.517 77.064 ;
     RECT  25.369 45.312 25.523 45.336 ;
     RECT  25.093 68.4 25.553 68.424 ;
     RECT  24.277 12.912 25.58 13.656 ;
     RECT  24.949 58.128 25.589 58.152 ;
     RECT  24.985 38.544 25.661 39.336 ;
     RECT  25.58 12.912 25.667 14.328 ;
     RECT  23.429 20.304 25.697 20.328 ;
     RECT  25.441 5.04 25.729 5.064 ;
     RECT  25.517 73.248 25.733 77.064 ;
     RECT  25.729 4.992 25.813 5.064 ;
     RECT  23.363 6.144 25.813 6.84 ;
     RECT  25.405 10.128 25.873 10.152 ;
     RECT  24.515 11.856 25.909 11.88 ;
     RECT  25.667 12.912 25.909 13.656 ;
     RECT  23.033 56.832 25.955 56.856 ;
     RECT  25.733 73.248 25.985 76.92 ;
     RECT  25.765 54.144 26.051 54.168 ;
     RECT  26.012 36.672 26.099 36.696 ;
     RECT  25.049 48.672 26.108 49.512 ;
     RECT  25.873 10.128 26.165 10.824 ;
     RECT  26.108 48.384 26.195 49.512 ;
     RECT  25.909 11.856 26.236 13.656 ;
     RECT  25.985 73.584 26.237 76.92 ;
     RECT  25.813 6.144 26.273 6.888 ;
     RECT  26.197 53.76 26.284 53.784 ;
     RECT  26.236 11.856 26.389 11.976 ;
     RECT  26.195 48.432 26.389 49.512 ;
     RECT  25.139 26.784 26.437 26.808 ;
     RECT  26.305 64.608 26.437 64.632 ;
     RECT  24.013 65.712 26.437 65.736 ;
     RECT  22.787 18.192 26.629 18.216 ;
     RECT  26.533 45.456 26.636 45.48 ;
     RECT  26.389 48.432 26.657 49.896 ;
     RECT  26.273 6.144 26.773 6.84 ;
     RECT  26.629 18 26.773 18.216 ;
     RECT  25.661 38.688 26.821 39.336 ;
     RECT  26.773 37.44 26.837 37.464 ;
     RECT  26.821 38.688 26.837 39.912 ;
     RECT  24.469 0.048 26.845 4.008 ;
     RECT  25.813 5.04 26.845 5.064 ;
     RECT  26.197 7.968 26.869 7.992 ;
     RECT  26.821 14.976 26.965 15 ;
     RECT  26.953 15.984 26.965 16.008 ;
     RECT  26.701 25.68 26.965 25.704 ;
     RECT  26.965 41.664 27.061 41.688 ;
     RECT  26.437 26.784 27.109 27.192 ;
     RECT  26.845 0.048 27.248 5.064 ;
     RECT  26.773 6.048 27.248 6.84 ;
     RECT  26.869 7.92 27.248 7.992 ;
     RECT  26.165 10.128 27.248 10.152 ;
     RECT  26.389 11.664 27.248 11.976 ;
     RECT  26.236 13.632 27.248 13.656 ;
     RECT  26.965 14.832 27.248 15 ;
     RECT  26.965 15.984 27.248 16.776 ;
     RECT  26.773 18 27.248 18.984 ;
     RECT  26.54 20.544 27.248 20.568 ;
     RECT  26.732 22.704 27.248 22.728 ;
     RECT  26.965 25.056 27.248 25.704 ;
     RECT  27.109 26.784 27.248 27.432 ;
     RECT  26.837 37.44 27.248 39.912 ;
     RECT  27.061 41.04 27.248 41.688 ;
     RECT  24.035 44.208 27.248 44.232 ;
     RECT  26.636 45.456 27.248 46.248 ;
     RECT  26.636 47.232 27.248 47.256 ;
     RECT  26.657 48.432 27.248 50.808 ;
     RECT  26.809 60.672 27.248 60.696 ;
     RECT  26.773 63.12 27.248 63.144 ;
     RECT  26.437 64.608 27.248 65.736 ;
     RECT  25.517 67.248 27.248 67.272 ;
     RECT  26.197 68.352 27.248 68.376 ;
     RECT  26.237 73.584 27.248 76.776 ;
     RECT  27.248 0.048 27.44 76.776 ;
     RECT  27.44 0.048 27.544 76.962 ;
     RECT  27.544 49.488 27.605 49.896 ;
     RECT  27.544 11.952 27.641 13.656 ;
     RECT  27.605 49.872 27.641 49.896 ;
     RECT  27.544 76.56 27.641 76.776 ;
     RECT  27.544 20.352 27.677 20.568 ;
     RECT  27.544 15.984 27.683 16.008 ;
     RECT  27.544 18.864 27.683 19.128 ;
     RECT  27.544 7.92 27.713 7.944 ;
     RECT  27.544 48.24 27.713 48.264 ;
     RECT  27.677 20.448 27.721 20.568 ;
     RECT  27.641 11.952 27.731 12.744 ;
     RECT  27.683 19.104 27.857 19.128 ;
     RECT  27.544 51.888 27.868 51.912 ;
     RECT  27.544 75.12 27.893 75.144 ;
     RECT  27.544 69.744 27.923 69.768 ;
     RECT  27.641 76.56 27.965 76.584 ;
     RECT  27.544 43.824 28.019 45.48 ;
     RECT  27.544 26.496 28.073 27.192 ;
     RECT  28.019 44.592 28.073 45.48 ;
     RECT  27.544 4.464 28.145 6.84 ;
     RECT  27.544 41.52 28.259 41.544 ;
     RECT  27.544 10.128 28.307 10.152 ;
     RECT  28.073 26.496 28.307 26.76 ;
     RECT  28.145 4.464 28.355 6.312 ;
     RECT  27.544 56.496 28.499 56.52 ;
     RECT  27.731 11.952 28.505 12.552 ;
     RECT  27.544 22.992 28.547 23.016 ;
     RECT  27.544 32.688 28.547 32.712 ;
     RECT  28.355 4.512 28.613 6.312 ;
     RECT  28.073 44.592 28.739 44.856 ;
     RECT  27.721 20.544 28.787 20.568 ;
     RECT  28.753 11.712 28.825 11.736 ;
     RECT  28.825 10.848 28.937 11.736 ;
     RECT  28.613 4.512 29.045 6.072 ;
     RECT  28.937 10.848 29.045 11.256 ;
     RECT  29.045 10.944 29.189 11.256 ;
     RECT  29.189 10.944 29.212 11.16 ;
     RECT  29.228 28.848 29.315 28.872 ;
     RECT  29.212 11.04 29.333 11.16 ;
     RECT  29.317 46.224 29.404 46.248 ;
     RECT  29.365 15.744 29.452 15.768 ;
     RECT  29.045 4.512 29.603 5.16 ;
     RECT  27.544 60.768 29.653 60.792 ;
     RECT  29.573 26.688 29.657 26.712 ;
     RECT  29.573 44.064 29.657 44.088 ;
     RECT  29.401 7.92 29.701 7.944 ;
     RECT  27.544 0.048 29.708 2.856 ;
     RECT  29.701 7.872 29.788 7.944 ;
     RECT  29.708 0.048 29.795 3.432 ;
     RECT  29.756 20.544 29.843 20.568 ;
     RECT  29.845 17.616 29.981 17.64 ;
     RECT  29.333 11.088 29.987 11.16 ;
     RECT  29.653 60.768 30.053 60.84 ;
     RECT  29.689 35.952 30.227 35.976 ;
     RECT  30.053 60.768 30.229 60.792 ;
     RECT  29.987 11.088 30.233 11.112 ;
     RECT  27.544 39.84 30.233 39.864 ;
     RECT  29.603 5.136 30.265 5.16 ;
     RECT  29.941 38.736 30.268 38.76 ;
     RECT  30.229 60.048 30.341 60.792 ;
     RECT  29.509 15.984 30.377 16.008 ;
     RECT  30.265 5.136 30.589 5.688 ;
     RECT  30.341 60.192 30.707 60.792 ;
     RECT  30.589 33.888 30.755 33.912 ;
     RECT  30.589 4.512 30.769 5.688 ;
     RECT  30.769 4.512 30.805 6.264 ;
     RECT  30.725 47.232 30.844 47.256 ;
     RECT  30.805 26.496 30.889 26.52 ;
     RECT  30.805 4.512 30.899 6.888 ;
     RECT  30.899 5.376 30.995 6.888 ;
     RECT  31.004 23.808 31.091 23.832 ;
     RECT  29.725 22.128 31.097 22.152 ;
     RECT  31.045 36.672 31.132 36.696 ;
     RECT  31.045 26.448 31.133 26.472 ;
     RECT  31.148 14.784 31.235 14.808 ;
     RECT  30.707 60.768 31.235 60.792 ;
     RECT  30.553 10.848 31.333 10.872 ;
     RECT  29.788 7.92 31.475 7.944 ;
     RECT  31.333 10.848 31.477 11.16 ;
     RECT  31.477 10.704 31.529 11.16 ;
     RECT  31.529 10.704 31.601 10.728 ;
     RECT  31.532 56.112 31.619 56.136 ;
     RECT  29.795 0.048 31.637 3.096 ;
     RECT  31.333 19.776 31.637 19.8 ;
     RECT  30.995 6.816 31.921 6.888 ;
     RECT  30.995 5.376 32.281 5.4 ;
     RECT  32.281 5.376 32.353 5.688 ;
     RECT  31.921 6.816 32.353 7.416 ;
     RECT  30.805 35.328 32.353 35.352 ;
     RECT  31.676 15.072 32.533 15.096 ;
     RECT  32.461 27.36 32.533 27.384 ;
     RECT  31.637 0.048 32.648 2.808 ;
     RECT  32.065 3.936 32.648 3.96 ;
     RECT  32.353 5.376 32.648 7.416 ;
     RECT  31.916 8.4 32.648 8.424 ;
     RECT  32.533 14.112 32.648 15.096 ;
     RECT  32.533 16.368 32.648 16.392 ;
     RECT  32.533 27.36 32.648 27.768 ;
     RECT  32.348 29.904 32.648 29.928 ;
     RECT  32.252 32.688 32.648 32.712 ;
     RECT  32.353 34.368 32.648 35.352 ;
     RECT  31.909 61.248 32.648 61.272 ;
     RECT  27.544 64.608 32.648 64.632 ;
     RECT  27.544 65.712 32.648 65.736 ;
     RECT  32.648 0.048 32.84 76.692 ;
     RECT  32.84 0.048 32.944 76.962 ;
     RECT  32.944 9.744 33.1 9.768 ;
     RECT  32.944 5.136 33.409 5.16 ;
     RECT  32.944 10.8 33.545 10.92 ;
     RECT  32.944 7.584 33.683 7.608 ;
     RECT  33.545 10.896 33.797 10.92 ;
     RECT  32.944 43.872 33.869 43.896 ;
     RECT  32.944 0.048 33.977 2.808 ;
     RECT  33.977 0.096 34.037 2.808 ;
     RECT  32.944 34.224 34.115 34.392 ;
     RECT  34.037 0.096 34.121 2.856 ;
     RECT  34.121 0.096 34.193 2.808 ;
     RECT  32.944 3.936 34.477 3.96 ;
     RECT  34.405 31.92 34.489 31.944 ;
     RECT  34.193 0.096 34.517 2.664 ;
     RECT  34.297 6.72 34.517 6.84 ;
     RECT  34.213 56.496 34.625 56.52 ;
     RECT  34.115 34.224 34.643 34.248 ;
     RECT  34.517 6.768 34.661 6.84 ;
     RECT  34.765 69.696 34.849 69.72 ;
     RECT  34.477 3.888 35.029 3.96 ;
     RECT  35.029 3.888 35.233 4.584 ;
     RECT  35.233 3.888 35.651 5.112 ;
     RECT  34.517 0.096 35.66 2.328 ;
     RECT  34.661 6.768 35.777 6.792 ;
     RECT  35.873 6.24 35.957 6.264 ;
     RECT  35.66 0.096 36.097 2.712 ;
     RECT  36.097 0.096 36.133 2.856 ;
     RECT  35.651 3.888 36.133 4.584 ;
     RECT  36.133 0.096 36.275 4.584 ;
     RECT  36.275 0.096 36.317 2.952 ;
     RECT  36.349 29.088 36.467 29.112 ;
     RECT  36.421 5.712 36.533 5.928 ;
     RECT  36.275 4.56 36.569 4.584 ;
     RECT  36.317 0.288 36.821 2.952 ;
     RECT  36.781 30.24 36.865 30.264 ;
     RECT  36.821 2.784 36.893 2.952 ;
     RECT  36.709 35.328 36.893 35.352 ;
     RECT  36.821 0.288 37.537 1.8 ;
     RECT  36.533 5.904 37.645 5.928 ;
     RECT  37.537 0.24 37.813 1.8 ;
     RECT  36.893 2.784 37.813 2.904 ;
     RECT  37.813 0.24 37.861 2.904 ;
     RECT  37.861 0.144 38.048 2.904 ;
     RECT  37.645 5.088 38.048 5.928 ;
     RECT  38.048 0.144 38.24 76.692 ;
     RECT  38.24 0.144 38.344 76.962 ;
     RECT  38.344 0.144 38.579 1.56 ;
     RECT  38.579 0.144 38.627 1.176 ;
     RECT  38.627 0.144 38.771 0.936 ;
     RECT  38.771 0.912 39.132 0.936 ;
    LAYER M5 ;
     RECT  38.736 0.133 38.76 0.144 ;
     RECT  14.064 0.144 38.76 0.323 ;
     RECT  0.24 0.517 0.36 0.787 ;
     RECT  5.64 0.517 5.76 0.787 ;
     RECT  11.04 0.517 11.16 0.787 ;
     RECT  14.112 0.323 38.616 1.187 ;
     RECT  14.112 1.187 38.568 1.571 ;
     RECT  14.112 1.571 38.352 1.763 ;
     RECT  14.256 1.763 38.352 1.859 ;
     RECT  14.592 1.859 38.352 2.915 ;
     RECT  5.64 0.787 5.952 3.301 ;
     RECT  11.04 0.787 11.352 3.829 ;
     RECT  10.8 3.829 11.64 3.925 ;
     RECT  14.592 2.915 36.84 3.925 ;
     RECT  14.064 3.925 36.84 4.595 ;
     RECT  14.064 4.595 34.632 5.123 ;
     RECT  35.616 4.595 36.84 5.123 ;
     RECT  37.92 2.915 38.352 5.123 ;
     RECT  29.52 5.123 34.632 5.171 ;
     RECT  14.064 5.123 28.44 5.699 ;
     RECT  30.624 5.171 32.952 5.699 ;
     RECT  14.064 5.699 28.296 5.989 ;
     RECT  36.432 5.123 36.84 6.191 ;
     RECT  30.96 5.699 32.952 6.275 ;
     RECT  35.904 6.191 36.84 6.275 ;
     RECT  5.64 3.301 6.216 6.757 ;
     RECT  7.728 3.829 7.752 6.757 ;
     RECT  5.64 6.757 7.752 6.841 ;
     RECT  4.512 7.391 4.536 7.475 ;
     RECT  31.44 6.275 32.952 7.541 ;
     RECT  34.08 5.171 34.632 7.541 ;
     RECT  31.44 7.541 34.632 7.629 ;
     RECT  29.52 5.171 29.544 7.669 ;
     RECT  29.52 7.669 29.736 7.907 ;
     RECT  31.44 7.629 32.952 7.955 ;
     RECT  8.784 3.205 8.808 8.437 ;
     RECT  31.968 7.955 32.952 8.461 ;
     RECT  5.64 6.841 6.216 9.349 ;
     RECT  7.2 6.841 7.752 9.349 ;
     RECT  13.68 5.989 28.296 9.397 ;
     RECT  5.64 9.349 7.752 9.451 ;
     RECT  32.16 8.461 32.952 9.717 ;
     RECT  5.64 9.451 6.216 9.781 ;
     RECT  32.16 9.717 33.048 9.805 ;
     RECT  5.088 9.781 6.216 9.865 ;
     RECT  13.488 9.397 28.296 10.163 ;
     RECT  32.16 9.805 32.952 10.693 ;
     RECT  29.52 7.907 29.544 10.805 ;
     RECT  29.52 10.805 29.976 10.933 ;
     RECT  10.8 3.925 12.264 11.029 ;
     RECT  31.488 10.693 32.952 11.125 ;
     RECT  29.136 10.933 29.976 11.171 ;
     RECT  31.344 11.125 32.952 11.209 ;
     RECT  29.136 11.171 29.544 11.267 ;
     RECT  8.784 8.437 9.624 11.941 ;
     RECT  10.8 11.029 12.312 11.941 ;
     RECT  13.488 10.163 27.816 12.563 ;
     RECT  13.488 12.563 27.72 12.755 ;
     RECT  8.784 11.941 12.312 12.853 ;
     RECT  4.128 12.901 4.152 13.099 ;
     RECT  8.736 12.853 12.312 13.621 ;
     RECT  13.488 12.755 27.672 13.621 ;
     RECT  8.736 13.621 27.672 14.243 ;
     RECT  5.64 9.865 6.216 14.709 ;
     RECT  7.2 9.451 7.752 14.709 ;
     RECT  32.16 11.209 32.952 14.773 ;
     RECT  5.64 14.709 7.752 14.955 ;
     RECT  8.736 14.243 12.312 15.637 ;
     RECT  13.488 14.243 27.672 15.637 ;
     RECT  29.52 11.267 29.544 15.699 ;
     RECT  29.376 15.699 29.544 15.787 ;
     RECT  8.736 15.637 27.672 16.019 ;
     RECT  29.52 15.787 29.544 16.019 ;
     RECT  29.856 17.567 29.88 17.651 ;
     RECT  8.736 16.019 27.552 18.853 ;
     RECT  8.736 18.853 27.672 19.139 ;
     RECT  8.736 19.139 27.552 20.437 ;
     RECT  8.736 20.437 27.672 20.523 ;
     RECT  28.752 20.499 28.776 20.587 ;
     RECT  29.808 20.499 29.832 20.587 ;
     RECT  5.64 14.955 6.216 21.621 ;
     RECT  7.2 14.955 7.752 21.621 ;
     RECT  4.512 21.589 4.536 21.675 ;
     RECT  31.2 14.773 32.952 22.117 ;
     RECT  30.192 22.117 32.952 22.201 ;
     RECT  5.64 21.621 7.752 22.211 ;
     RECT  8.736 20.523 27.552 22.965 ;
     RECT  8.736 22.965 28.536 23.053 ;
     RECT  31.2 22.201 32.952 23.733 ;
     RECT  31.056 23.733 32.952 23.843 ;
     RECT  31.2 23.843 32.952 26.421 ;
     RECT  8.736 23.053 27.552 26.451 ;
     RECT  31.056 26.421 32.952 26.485 ;
     RECT  30.816 26.485 32.952 26.569 ;
     RECT  3.792 26.643 3.816 26.731 ;
     RECT  29.616 26.677 29.64 26.761 ;
     RECT  8.736 26.451 28.296 26.771 ;
     RECT  5.64 22.211 6.216 26.899 ;
     RECT  4.8 26.899 6.216 26.987 ;
     RECT  5.64 26.987 6.216 28.261 ;
     RECT  5.52 28.261 6.216 28.459 ;
     RECT  4.512 28.405 4.536 28.931 ;
     RECT  29.28 28.837 29.304 29.035 ;
     RECT  5.64 28.459 6.216 29.039 ;
     RECT  7.2 22.211 7.752 29.039 ;
     RECT  5.64 29.039 7.752 29.123 ;
     RECT  36.432 6.275 36.84 29.123 ;
     RECT  8.736 26.771 27.552 29.699 ;
     RECT  36.72 29.123 36.84 30.275 ;
     RECT  25.92 29.699 27.552 32.629 ;
     RECT  25.92 32.629 28.536 32.723 ;
     RECT  5.64 29.123 6.216 33.269 ;
     RECT  7.2 29.123 7.752 33.269 ;
     RECT  3.984 33.253 4.008 33.337 ;
     RECT  5.64 33.269 7.752 33.635 ;
     RECT  31.2 26.569 32.952 33.839 ;
     RECT  30.72 33.839 32.952 33.923 ;
     RECT  34.08 7.629 34.632 34.259 ;
     RECT  8.736 29.699 24.936 34.323 ;
     RECT  25.92 32.723 27.552 34.323 ;
     RECT  34.08 34.259 34.104 34.403 ;
     RECT  8.736 34.323 27.552 34.411 ;
     RECT  31.2 33.923 32.952 35.317 ;
     RECT  36.72 30.275 36.744 35.363 ;
     RECT  30.816 35.317 32.952 35.401 ;
     RECT  30.192 35.893 30.216 35.987 ;
     RECT  31.2 35.401 32.952 36.661 ;
     RECT  31.056 36.661 32.952 37.035 ;
     RECT  5.64 33.635 6.216 37.477 ;
     RECT  5.088 37.477 6.216 37.557 ;
     RECT  7.2 33.635 7.752 37.557 ;
     RECT  8.736 34.411 24.936 37.557 ;
     RECT  5.088 37.557 24.936 37.611 ;
     RECT  5.64 37.611 24.936 37.645 ;
     RECT  8.736 37.645 24.936 38.243 ;
     RECT  25.92 34.411 27.552 38.533 ;
     RECT  25.584 38.533 27.552 38.699 ;
     RECT  30.192 38.645 30.216 38.771 ;
     RECT  5.64 37.645 7.752 39.123 ;
     RECT  8.736 38.243 24.36 39.123 ;
     RECT  5.64 39.123 24.36 39.211 ;
     RECT  8.736 39.211 24.36 39.301 ;
     RECT  25.92 38.699 27.552 39.829 ;
     RECT  25.92 39.829 28.488 39.915 ;
     RECT  8.736 39.301 24.744 40.991 ;
     RECT  25.92 39.915 27.552 40.991 ;
     RECT  8.736 40.991 27.552 41.075 ;
     RECT  25.92 41.075 27.552 41.491 ;
     RECT  25.92 41.491 28.248 41.579 ;
     RECT  5.64 39.211 7.752 42.133 ;
     RECT  5.088 42.133 7.752 43.379 ;
     RECT  25.92 41.579 27.552 43.795 ;
     RECT  31.2 37.035 32.952 43.861 ;
     RECT  31.2 43.861 33.672 44.075 ;
     RECT  29.616 44.015 29.64 44.099 ;
     RECT  25.92 43.795 28.008 44.581 ;
     RECT  25.92 44.581 28.536 44.597 ;
     RECT  25.92 44.597 28.728 44.665 ;
     RECT  28.704 44.665 28.728 44.867 ;
     RECT  8.736 41.075 24.744 45.301 ;
     RECT  25.92 44.665 27.552 45.301 ;
     RECT  29.328 46.197 29.352 46.285 ;
     RECT  31.2 44.075 32.952 47.187 ;
     RECT  30.768 47.187 32.952 47.275 ;
     RECT  8.736 45.301 27.552 48.181 ;
     RECT  8.736 48.181 27.672 48.275 ;
     RECT  5.64 43.379 7.752 49.333 ;
     RECT  5.088 49.333 7.752 49.427 ;
     RECT  5.184 49.427 7.752 49.515 ;
     RECT  8.736 48.275 27.552 51.637 ;
     RECT  8.736 51.637 27.816 51.923 ;
     RECT  5.64 49.515 7.752 52.309 ;
     RECT  8.736 51.923 27.552 52.309 ;
     RECT  5.64 52.309 27.552 52.395 ;
     RECT  5.64 52.395 7.752 53.893 ;
     RECT  5.472 53.893 7.752 54.709 ;
     RECT  8.736 52.395 27.552 54.709 ;
     RECT  5.472 54.709 27.552 54.803 ;
     RECT  5.472 54.803 7.752 55.813 ;
     RECT  8.736 54.803 27.552 55.813 ;
     RECT  5.472 55.813 27.552 56.437 ;
     RECT  5.472 56.437 28.488 56.531 ;
     RECT  34.224 56.437 34.248 56.531 ;
     RECT  5.472 56.531 27.552 57.589 ;
     RECT  3.84 57.973 3.864 58.117 ;
     RECT  3.84 58.117 4.152 58.155 ;
     RECT  5.424 57.589 27.552 58.805 ;
     RECT  5.28 58.805 27.552 59.115 ;
     RECT  4.128 58.155 4.152 59.221 ;
     RECT  5.28 59.115 9.336 59.221 ;
     RECT  4.128 59.221 9.336 59.797 ;
     RECT  31.2 47.275 32.952 59.829 ;
     RECT  30.672 59.829 32.952 59.999 ;
     RECT  30.24 59.999 32.952 60.083 ;
     RECT  30.672 60.083 32.952 60.267 ;
     RECT  10.464 59.115 27.552 60.467 ;
     RECT  3.936 59.797 9.336 60.661 ;
     RECT  10.464 60.467 17.496 60.661 ;
     RECT  31.2 60.267 32.952 60.803 ;
     RECT  29.664 60.767 29.688 60.851 ;
     RECT  3.936 60.661 17.496 60.907 ;
     RECT  18.72 60.467 27.552 61.043 ;
     RECT  3.936 60.907 9.336 61.535 ;
     RECT  3.888 61.535 9.336 61.619 ;
     RECT  10.464 60.907 17.496 62.149 ;
     RECT  18.72 61.043 20.52 62.611 ;
     RECT  21.504 61.043 27.552 62.611 ;
     RECT  18.72 62.611 27.552 63.275 ;
     RECT  10.32 62.149 17.496 63.299 ;
     RECT  3.936 61.619 9.336 63.669 ;
     RECT  10.32 63.299 12.408 63.669 ;
     RECT  3.936 63.669 12.408 63.779 ;
     RECT  2.832 63.781 2.856 63.865 ;
     RECT  18.72 63.275 20.52 64.451 ;
     RECT  0.24 0.787 0.552 65.269 ;
     RECT  13.488 63.299 17.496 65.461 ;
     RECT  18.816 64.451 20.52 65.461 ;
     RECT  21.504 63.275 27.552 65.461 ;
     RECT  13.488 65.461 27.552 65.515 ;
     RECT  19.536 65.515 27.552 65.555 ;
     RECT  13.488 65.515 18.408 65.603 ;
     RECT  18.384 65.603 18.408 65.699 ;
     RECT  31.728 60.803 32.952 65.747 ;
     RECT  19.536 65.555 20.52 66.613 ;
     RECT  21.504 65.555 27.552 66.613 ;
     RECT  3.936 63.779 9.336 67.283 ;
     RECT  13.488 65.603 17.304 67.283 ;
     RECT  14.064 67.283 17.304 68.255 ;
     RECT  14.064 68.255 18.264 68.339 ;
     RECT  10.32 63.779 12.408 68.341 ;
     RECT  0.24 65.269 0.888 68.389 ;
     RECT  3.936 67.283 9 69.301 ;
     RECT  10.176 68.341 12.408 69.301 ;
     RECT  14.064 68.339 18.12 69.493 ;
     RECT  3.936 69.301 12.408 69.523 ;
     RECT  3.936 69.523 12.936 69.611 ;
     RECT  19.536 66.613 27.552 69.685 ;
     RECT  34.8 69.685 34.824 69.769 ;
     RECT  19.536 69.685 27.912 69.779 ;
     RECT  19.536 69.779 27.552 69.829 ;
     RECT  13.968 69.493 18.12 70.117 ;
     RECT  13.488 70.117 18.12 70.691 ;
     RECT  13.488 70.691 18.168 70.703 ;
     RECT  19.488 69.829 27.552 70.837 ;
     RECT  13.392 70.703 18.168 71.125 ;
     RECT  19.392 70.837 27.552 71.125 ;
     RECT  3.936 69.611 12.408 71.413 ;
     RECT  13.392 71.125 27.552 71.413 ;
     RECT  3.936 71.413 27.552 72.787 ;
     RECT  0.24 68.389 1.128 72.949 ;
     RECT  2.976 72.787 27.552 72.997 ;
     RECT  0.24 72.949 1.656 73.381 ;
     RECT  0.24 73.381 1.704 73.429 ;
     RECT  2.784 72.997 27.552 73.429 ;
     RECT  0.24 73.429 27.552 75.875 ;
     RECT  0.24 75.875 25.752 76.884 ;
     RECT  27.24 75.875 27.552 76.884 ;
     RECT  32.64 65.747 32.952 76.884 ;
     RECT  38.04 5.123 38.352 76.884 ;
     RECT  0.432 76.884 25.752 76.973 ;
     RECT  27.432 76.884 27.552 76.973 ;
     RECT  32.832 76.884 32.952 76.973 ;
     RECT  38.232 76.884 38.352 76.973 ;
     RECT  0.624 76.973 25.752 77.035 ;
     RECT  0.624 77.035 25.176 77.584 ;
    LAYER M6 ;
     RECT  0 76.596 1.973 76.884 ;
     RECT  1.973 76.596 2.101 77.152 ;
     RECT  2.101 76.416 2.293 77.152 ;
     RECT  2.293 75.84 2.387 77.152 ;
     RECT  1.957 74.048 2.414 74.08 ;
     RECT  0 60.396 2.421 61.26 ;
     RECT  2.387 75.84 2.531 77.024 ;
     RECT  0 71.196 2.965 72.06 ;
     RECT  2.414 73.536 2.965 74.08 ;
     RECT  2.965 71.196 3.189 74.08 ;
     RECT  2.531 75.84 3.189 76.884 ;
     RECT  3.189 71.196 3.243 76.884 ;
     RECT  0 27.996 3.781 28.86 ;
     RECT  2.421 59.776 3.829 61.26 ;
     RECT  3.829 57.984 3.877 61.26 ;
     RECT  3.877 57.984 3.947 61.6 ;
     RECT  0 33.396 3.973 34.26 ;
     RECT  0 11.796 4.117 12.66 ;
     RECT  3.243 73.408 4.117 76.884 ;
     RECT  0 65.796 4.213 66.66 ;
     RECT  2.821 63.808 4.267 63.84 ;
     RECT  3.243 71.196 4.341 72.06 ;
     RECT  0 49.596 4.405 50.46 ;
     RECT  0 6.396 4.501 7.26 ;
     RECT  0 22.596 4.501 23.46 ;
     RECT  4.341 70.976 4.725 72.06 ;
     RECT  4.117 73.408 4.725 77.024 ;
     RECT  3.781 26.688 4.843 28.86 ;
     RECT  0 38.796 5.077 39.66 ;
     RECT  4.405 49.472 5.077 50.46 ;
     RECT  4.453 68.672 5.154 68.704 ;
     RECT  3.947 58.816 5.171 61.26 ;
     RECT  5.154 68.672 5.173 69.664 ;
     RECT  4.725 70.976 5.173 77.024 ;
     RECT  5.173 68.672 5.227 77.024 ;
     RECT  5.227 70.464 5.941 77.024 ;
     RECT  5.941 70.464 6.083 77.088 ;
     RECT  6.083 71.196 6.085 77.088 ;
     RECT  0 44.196 6.229 45.06 ;
     RECT  6.085 71.196 6.251 77.408 ;
     RECT  6.251 71.196 6.275 77.216 ;
     RECT  4.501 21.632 6.323 23.46 ;
     RECT  3.973 33.28 6.323 34.26 ;
     RECT  0 54.996 6.565 55.86 ;
     RECT  6.565 54.996 6.645 56.736 ;
     RECT  5.077 49.344 6.709 50.46 ;
     RECT  5.171 58.816 6.827 58.848 ;
     RECT  5.077 9.792 6.837 9.824 ;
     RECT  6.805 14.912 6.837 14.944 ;
     RECT  6.837 9.408 6.891 9.824 ;
     RECT  6.645 54.996 6.899 56.928 ;
     RECT  6.837 14.72 6.91 14.944 ;
     RECT  4.843 27.996 6.965 28.86 ;
     RECT  4.501 6.396 7.019 7.456 ;
     RECT  6.965 27.996 7.043 29.088 ;
     RECT  4.213 65.152 7.043 66.66 ;
     RECT  6.891 9.408 7.187 9.44 ;
     RECT  0 17.196 7.333 18.06 ;
     RECT  6.91 14.912 7.349 14.944 ;
     RECT  7.333 17.196 7.349 19.232 ;
     RECT  7.349 17.196 7.403 19.552 ;
     RECT  6.323 21.696 7.403 23.46 ;
     RECT  6.373 46.784 7.413 46.816 ;
     RECT  6.709 49.344 7.467 50.912 ;
     RECT  7.349 14.912 7.475 15.136 ;
     RECT  7.413 46.784 7.486 47.264 ;
     RECT  4.117 11.796 7.525 13.088 ;
     RECT  6.275 71.196 7.571 77.024 ;
     RECT  6.229 44.032 7.65 45.06 ;
     RECT  7.65 43.776 7.723 45.06 ;
     RECT  7.486 46.784 7.723 46.816 ;
     RECT  6.899 54.996 7.723 56.736 ;
     RECT  6.517 53.568 7.909 53.6 ;
     RECT  7.477 41.024 7.979 41.056 ;
     RECT  7.571 73.984 8.053 77.024 ;
     RECT  7.043 65.408 8.485 66.66 ;
     RECT  5.227 68.672 8.485 68.704 ;
     RECT  7.909 52.352 8.558 53.6 ;
     RECT  7.723 54.996 8.558 55.86 ;
     RECT  8.558 52.352 8.627 55.86 ;
     RECT  8.485 65.408 8.773 68.704 ;
     RECT  5.077 37.568 8.885 39.66 ;
     RECT  8.885 37.568 8.963 39.904 ;
     RECT  7.571 71.196 9.109 72.352 ;
     RECT  8.053 73.984 9.109 77.088 ;
     RECT  8.627 52.352 9.131 53.6 ;
     RECT  9.061 58.688 9.205 58.72 ;
     RECT  9.109 71.196 9.205 77.088 ;
     RECT  9.205 71.04 9.274 77.088 ;
     RECT  7.909 63.296 9.445 63.328 ;
     RECT  9.274 71.196 9.445 77.088 ;
     RECT  5.171 60.396 9.461 61.26 ;
     RECT  9.445 71.196 9.493 77.152 ;
     RECT  9.445 63.296 9.515 63.712 ;
     RECT  8.773 65.344 9.515 68.704 ;
     RECT  9.461 60.396 9.643 61.408 ;
     RECT  9.515 65.408 9.717 68.704 ;
     RECT  9.131 53.568 9.731 53.6 ;
     RECT  9.205 58.688 9.731 59.104 ;
     RECT  7.467 49.596 9.781 50.912 ;
     RECT  7.403 19.52 9.875 19.552 ;
     RECT  9.781 49.472 9.973 50.912 ;
     RECT  8.885 42.688 10.019 42.72 ;
     RECT  9.493 71.196 10.117 77.28 ;
     RECT  9.717 65.408 10.211 69.024 ;
     RECT  8.627 54.996 10.213 55.86 ;
     RECT  9.733 57.536 10.213 58.08 ;
     RECT  8.963 37.568 10.307 39.66 ;
     RECT  9.973 49.216 10.307 50.912 ;
     RECT  10.213 54.996 10.309 58.08 ;
     RECT  10.211 65.408 10.403 67.872 ;
     RECT  10.309 54.848 10.411 58.08 ;
     RECT  9.061 46.976 10.558 47.008 ;
     RECT  7.403 22.596 10.741 23.46 ;
     RECT  7.525 11.796 10.914 13.344 ;
     RECT  7.475 14.912 10.914 14.944 ;
     RECT  10.741 22.272 10.933 23.46 ;
     RECT  10.213 25.024 10.933 25.056 ;
     RECT  7.723 44.032 10.933 45.06 ;
     RECT  10.914 11.796 10.987 14.944 ;
     RECT  10.987 14.912 11.317 14.944 ;
     RECT  10.117 71.196 11.317 77.408 ;
     RECT  11.317 14.912 11.371 15.136 ;
     RECT  10.933 22.272 11.381 25.056 ;
     RECT  9.643 60.396 11.381 61.26 ;
     RECT  11.381 22.272 11.435 25.696 ;
     RECT  10.411 54.996 11.459 57.056 ;
     RECT  10.933 9.728 11.509 9.76 ;
     RECT  10.987 11.796 11.509 12.66 ;
     RECT  11.317 70.976 11.509 77.408 ;
     RECT  11.509 9.728 11.563 12.66 ;
     RECT  11.509 70.592 11.578 77.472 ;
     RECT  11.578 70.592 11.893 77.408 ;
     RECT  11.381 60.396 11.989 62.24 ;
     RECT  11.701 63.68 11.989 63.712 ;
     RECT  10.403 65.408 11.989 66.66 ;
     RECT  11.989 60.396 12.014 66.66 ;
     RECT  12.014 60.396 12.075 67.296 ;
     RECT  11.563 10.496 12.083 12.66 ;
     RECT  12.075 65.408 12.083 67.296 ;
     RECT  11.893 70.528 12.139 77.408 ;
     RECT  11.435 25.664 12.371 25.696 ;
     RECT  11.435 22.272 12.421 23.46 ;
     RECT  10.933 44.032 12.45 46.24 ;
     RECT  12.139 70.528 12.515 77.28 ;
     RECT  7.043 27.996 12.517 28.86 ;
     RECT  6.323 33.396 12.517 34.26 ;
     RECT  12.45 44.032 12.523 46.816 ;
     RECT  12.075 60.396 12.523 61.856 ;
     RECT  12.523 60.396 12.597 61.26 ;
     RECT  12.597 59.2 12.661 61.26 ;
     RECT  12.661 58.752 12.67 61.26 ;
     RECT  12.325 57.216 12.715 57.248 ;
     RECT  10.307 38.796 12.725 39.66 ;
     RECT  11.797 41.024 12.725 41.056 ;
     RECT  12.67 58.752 12.73 58.784 ;
     RECT  12.725 38.796 12.779 41.824 ;
     RECT  12.779 38.796 12.803 39.776 ;
     RECT  7.381 30.848 12.901 30.88 ;
     RECT  12.515 70.528 12.901 77.216 ;
     RECT  12.901 30.72 12.971 30.88 ;
     RECT  12.517 32.512 12.971 34.26 ;
     RECT  12.779 41.792 13.091 41.824 ;
     RECT  12.523 44.032 13.109 45.344 ;
     RECT  10.307 49.216 13.139 50.46 ;
     RECT  13.109 43.264 13.187 45.344 ;
     RECT  11.941 37.312 13.285 37.344 ;
     RECT  12.803 38.796 13.285 39.66 ;
     RECT  13.285 37.312 13.331 39.66 ;
     RECT  7.403 17.196 13.333 18.06 ;
     RECT  12.901 69.568 13.355 77.216 ;
     RECT  13.333 17.196 13.365 18.784 ;
     RECT  12.421 21.312 13.365 23.46 ;
     RECT  13.365 17.196 13.419 19.68 ;
     RECT  13.365 21.312 13.419 23.584 ;
     RECT  13.355 70.72 13.419 77.216 ;
     RECT  13.419 70.72 13.427 72.06 ;
     RECT  13.419 22.596 13.475 23.584 ;
     RECT  13.427 70.976 13.69 72.06 ;
     RECT  13.685 53.056 13.763 53.088 ;
     RECT  12.517 26.752 14.005 28.86 ;
     RECT  11.459 54.996 14.005 55.86 ;
     RECT  13.69 71.04 14.014 72.06 ;
     RECT  13.419 74.112 14.074 77.216 ;
     RECT  14.005 54.144 14.195 55.86 ;
     RECT  13.621 57.792 14.325 57.824 ;
     RECT  13.187 44.032 14.339 45.344 ;
     RECT  14.339 44.032 14.379 45.06 ;
     RECT  14.149 52.16 14.398 52.448 ;
     RECT  14.005 25.92 14.629 28.86 ;
     RECT  0 0.996 14.677 1.86 ;
     RECT  14.074 75.84 14.677 77.216 ;
     RECT  14.629 24.832 14.699 28.86 ;
     RECT  14.014 71.196 14.709 72.06 ;
     RECT  12.67 60.396 14.773 61.26 ;
     RECT  13.475 22.596 14.821 23.46 ;
     RECT  14.709 71.196 14.821 72.416 ;
     RECT  14.074 74.112 14.821 74.528 ;
     RECT  14.821 71.196 14.827 74.528 ;
     RECT  12.971 30.848 14.837 30.88 ;
     RECT  13.331 37.632 14.867 39.66 ;
     RECT  14.699 26.752 14.891 28.86 ;
     RECT  14.837 30.848 14.891 31.328 ;
     RECT  12.083 10.624 14.917 12.66 ;
     RECT  13.419 17.196 14.946 18.06 ;
     RECT  13.419 19.648 14.946 19.68 ;
     RECT  14.827 71.196 14.963 74.208 ;
     RECT  11.371 15.104 15.019 15.136 ;
     RECT  14.946 17.196 15.019 19.68 ;
     RECT  12.971 33.396 15.061 34.26 ;
     RECT  14.891 31.296 15.147 31.328 ;
     RECT  15.061 33.396 15.147 35.36 ;
     RECT  14.325 57.472 15.155 57.824 ;
     RECT  15.155 57.792 15.443 57.824 ;
     RECT  14.965 68.288 15.445 68.32 ;
     RECT  14.677 0.996 15.781 2.016 ;
     RECT  12.083 65.408 15.781 66.66 ;
     RECT  15.445 68.288 15.797 69.024 ;
     RECT  15.781 65.408 15.979 66.784 ;
     RECT  15.979 65.408 16.019 66.66 ;
     RECT  15.781 0.996 16.165 2.592 ;
     RECT  14.963 71.196 16.245 73.44 ;
     RECT  15.797 68.288 16.299 69.536 ;
     RECT  15.019 17.196 16.309 18.06 ;
     RECT  15.019 19.648 16.309 19.68 ;
     RECT  14.677 75.84 16.309 77.28 ;
     RECT  16.309 17.196 16.355 19.68 ;
     RECT  16.165 0.384 16.645 2.592 ;
     RECT  16.309 75.648 16.741 77.28 ;
     RECT  16.355 17.196 16.757 19.168 ;
     RECT  14.891 27.84 16.757 28.86 ;
     RECT  16.645 0.256 16.811 2.592 ;
     RECT  16.757 17.024 16.811 19.168 ;
     RECT  16.245 71.196 16.821 74.08 ;
     RECT  16.741 75.648 16.821 77.344 ;
     RECT  16.757 27.84 16.875 29.6 ;
     RECT  16.811 0.448 16.883 2.592 ;
     RECT  16.811 17.024 16.883 18.06 ;
     RECT  14.325 47.808 16.883 47.84 ;
     RECT  15.061 63.232 16.883 63.264 ;
     RECT  14.821 22.596 16.885 24.416 ;
     RECT  15.147 33.396 16.885 34.26 ;
     RECT  16.821 71.196 16.885 77.344 ;
     RECT  16.883 0.576 16.931 2.592 ;
     RECT  14.773 59.648 16.931 61.26 ;
     RECT  16.885 70.08 16.931 77.344 ;
     RECT  16.931 70.08 16.954 77.216 ;
     RECT  16.931 0.64 16.979 2.592 ;
     RECT  16.885 32.448 16.979 34.26 ;
     RECT  16.875 27.996 17.027 29.6 ;
     RECT  16.954 71.196 17.027 77.216 ;
     RECT  14.917 10.624 17.123 13.728 ;
     RECT  14.195 54.996 17.413 55.86 ;
     RECT  17.413 54.08 17.515 55.86 ;
     RECT  17.461 57.792 17.555 57.824 ;
     RECT  16.979 0.996 17.843 2.592 ;
     RECT  14.379 44.196 18.101 45.06 ;
     RECT  18.101 43.136 18.227 45.06 ;
     RECT  17.123 10.624 18.275 12.66 ;
     RECT  16.299 68.288 18.275 68.32 ;
     RECT  17.027 71.196 18.357 77.024 ;
     RECT  14.867 38.208 18.853 39.66 ;
     RECT  17.843 0.996 18.869 2.528 ;
     RECT  13.139 49.596 18.869 50.46 ;
     RECT  14.398 52.16 18.869 52.192 ;
     RECT  18.227 44.032 18.899 45.06 ;
     RECT  17.515 54.592 18.899 55.86 ;
     RECT  16.019 65.472 18.899 66.66 ;
     RECT  18.853 37.632 18.923 39.66 ;
     RECT  18.923 38.144 18.997 39.66 ;
     RECT  18.357 70.848 19.061 77.024 ;
     RECT  16.885 22.596 19.141 24.608 ;
     RECT  17.027 27.996 19.189 28.86 ;
     RECT  16.979 33.396 19.317 34.26 ;
     RECT  16.757 31.04 19.379 31.072 ;
     RECT  19.317 32.384 19.39 34.4 ;
     RECT  19.061 69.888 19.523 77.024 ;
     RECT  18.899 54.996 19.573 55.86 ;
     RECT  18.899 44.196 19.701 45.06 ;
     RECT  16.931 60.396 19.829 61.26 ;
     RECT  18.997 38.144 19.893 40.544 ;
     RECT  18.757 42.112 19.893 42.144 ;
     RECT  19.429 58.816 19.893 58.848 ;
     RECT  19.523 70.144 19.907 77.024 ;
     RECT  19.893 38.144 19.947 42.144 ;
     RECT  19.573 54.996 19.947 56.928 ;
     RECT  19.893 58.688 19.947 58.848 ;
     RECT  19.39 33.396 20.003 34.4 ;
     RECT  19.947 38.144 20.011 39.776 ;
     RECT  19.333 63.808 20.021 63.84 ;
     RECT  18.275 11.796 20.101 12.66 ;
     RECT  18.899 65.796 20.13 66.66 ;
     RECT  18.869 49.596 20.149 52.192 ;
     RECT  19.829 60.288 20.243 61.26 ;
     RECT  18.869 0.832 20.245 2.528 ;
     RECT  20.245 0.384 20.277 2.528 ;
     RECT  20.13 65.796 20.341 67.744 ;
     RECT  20.277 0.256 20.35 2.528 ;
     RECT  20.101 11.796 20.437 12.96 ;
     RECT  20.011 38.796 20.483 39.776 ;
     RECT  20.341 15.616 20.485 15.648 ;
     RECT  16.883 17.196 20.485 18.06 ;
     RECT  19.701 44.196 20.485 45.6 ;
     RECT  20.437 11.52 20.523 12.96 ;
     RECT  20.485 15.616 20.523 18.06 ;
     RECT  19.141 22.596 20.523 24.928 ;
     RECT  19.907 70.656 20.533 77.024 ;
     RECT  20.533 70.656 20.581 77.152 ;
     RECT  20.021 63.232 20.654 63.84 ;
     RECT  20.341 65.796 20.661 67.872 ;
     RECT  20.654 62.656 20.715 63.84 ;
     RECT  20.35 0.832 20.723 2.528 ;
     RECT  20.715 62.656 20.723 63.264 ;
     RECT  20.661 65.472 20.734 67.872 ;
     RECT  20.723 63.232 20.915 63.264 ;
     RECT  20.485 44.196 21.038 46.176 ;
     RECT  20.149 49.216 21.099 52.192 ;
     RECT  20.581 70.656 21.251 77.28 ;
     RECT  20.734 65.796 21.301 67.872 ;
     RECT  21.301 65.796 21.37 68.384 ;
     RECT  21.099 49.596 21.443 52.192 ;
     RECT  19.947 58.688 21.443 58.72 ;
     RECT  21.557 53.504 21.621 53.536 ;
     RECT  20.723 0.832 21.637 1.86 ;
     RECT  20.523 22.596 21.637 23.46 ;
     RECT  21.251 71.196 21.637 77.28 ;
     RECT  21.443 51.904 21.675 51.936 ;
     RECT  20.523 24.896 21.683 24.928 ;
     RECT  19.947 41.6 21.731 41.632 ;
     RECT  20.003 33.396 21.733 34.26 ;
     RECT  20.243 60.396 21.733 61.26 ;
     RECT  21.637 71.196 21.739 77.344 ;
     RECT  21.37 65.796 21.779 67.936 ;
     RECT  21.739 71.196 21.931 77.28 ;
     RECT  21.637 0.384 22.067 1.86 ;
     RECT  21.733 60.396 22.123 61.536 ;
     RECT  21.931 74.176 22.123 75.296 ;
     RECT  20.437 20.224 22.197 20.256 ;
     RECT  22.067 0.576 22.211 1.86 ;
     RECT  22.197 19.648 22.251 20.256 ;
     RECT  21.637 21.696 22.251 23.46 ;
     RECT  22.123 74.688 22.251 75.296 ;
     RECT  21.038 44.196 22.309 46.752 ;
     RECT  20.523 16.576 22.355 18.06 ;
     RECT  21.621 53.504 22.357 53.664 ;
     RECT  19.947 54.996 22.357 55.86 ;
     RECT  22.309 44.196 22.379 47.328 ;
     RECT  22.355 17.196 22.405 18.06 ;
     RECT  22.251 19.648 22.405 19.68 ;
     RECT  22.405 17.196 22.451 19.68 ;
     RECT  22.251 22.596 22.741 23.46 ;
     RECT  22.357 53.504 22.835 55.86 ;
     RECT  21.733 33.216 22.933 34.26 ;
     RECT  19.717 35.904 22.933 35.936 ;
     RECT  21.931 76.596 22.979 77.28 ;
     RECT  19.189 27.996 23.029 29.024 ;
     RECT  23.029 26.752 23.083 29.024 ;
     RECT  22.933 33.216 23.083 35.936 ;
     RECT  23.083 26.752 23.093 28.86 ;
     RECT  23.093 26.688 23.157 28.86 ;
     RECT  22.979 76.596 23.219 77.216 ;
     RECT  23.157 26.496 23.339 28.86 ;
     RECT  22.741 22.596 23.411 23.776 ;
     RECT  23.029 31.36 23.411 31.584 ;
     RECT  22.835 53.632 23.411 55.86 ;
     RECT  21.931 71.196 23.413 72.8 ;
     RECT  22.251 75.2 23.413 75.296 ;
     RECT  23.219 76.596 23.413 76.884 ;
     RECT  23.413 75.2 23.747 76.884 ;
     RECT  21.779 65.796 23.918 66.66 ;
     RECT  20.483 38.796 23.925 39.66 ;
     RECT  22.379 44.196 23.987 46.56 ;
     RECT  23.918 65.536 23.987 66.66 ;
     RECT  22.837 68.48 24.037 68.512 ;
     RECT  24.037 68.352 24.083 68.512 ;
     RECT  23.029 63.104 24.229 63.136 ;
     RECT  24.229 63.104 24.299 64.032 ;
     RECT  22.123 60.396 24.437 61.26 ;
     RECT  20.523 11.796 24.469 12.66 ;
     RECT  24.546 41.28 24.619 41.312 ;
     RECT  23.987 44.196 24.747 45.92 ;
     RECT  23.747 76.416 24.805 76.884 ;
     RECT  24.805 76.416 24.853 77.024 ;
     RECT  24.853 76.416 25.067 77.088 ;
     RECT  23.083 33.396 25.139 34.4 ;
     RECT  23.413 71.196 25.141 72.928 ;
     RECT  25.141 71.196 25.515 73.568 ;
     RECT  25.013 75.008 25.589 75.04 ;
     RECT  25.067 76.416 25.589 77.024 ;
     RECT  25.589 75.008 25.763 77.024 ;
     RECT  25.765 5.056 25.835 5.088 ;
     RECT  24.085 8.576 25.835 8.608 ;
     RECT  24.469 11.648 26.082 12.66 ;
     RECT  26.082 11.648 26.149 12.832 ;
     RECT  21.443 49.596 26.149 50.46 ;
     RECT  26.149 11.648 26.165 12.96 ;
     RECT  26.053 36.672 26.165 36.704 ;
     RECT  23.925 38.656 26.165 39.66 ;
     RECT  24.661 41.024 26.165 41.056 ;
     RECT  26.165 11.136 26.219 12.96 ;
     RECT  22.451 17.196 26.219 19.104 ;
     RECT  26.165 36.672 26.219 41.056 ;
     RECT  23.411 53.76 26.243 55.86 ;
     RECT  24.083 68.352 26.243 68.384 ;
     RECT  26.149 48.384 26.549 50.46 ;
     RECT  26.549 20.544 26.627 20.576 ;
     RECT  26.549 48.192 26.658 50.46 ;
     RECT  25.515 73.536 26.675 73.568 ;
     RECT  24.747 44.196 26.677 45.06 ;
     RECT  26.658 47.232 26.677 50.46 ;
     RECT  23.339 26.496 26.725 26.528 ;
     RECT  26.677 44.196 26.731 51.68 ;
     RECT  23.411 22.596 26.773 23.46 ;
     RECT  25.621 14.272 26.805 14.304 ;
     RECT  26.219 17.196 26.805 18.976 ;
     RECT  26.805 14.272 26.819 18.976 ;
     RECT  26.219 37.44 26.819 37.472 ;
     RECT  24.299 63.104 26.819 63.136 ;
     RECT  26.819 14.272 26.859 18.06 ;
     RECT  26.219 38.796 26.867 41.056 ;
     RECT  26.859 14.912 26.878 18.06 ;
     RECT  25.763 75.008 26.915 76.884 ;
     RECT  26.878 15.744 27.011 18.06 ;
     RECT  26.915 75.584 27.059 76.884 ;
     RECT  26.867 41.024 27.107 41.056 ;
     RECT  26.725 25.664 27.109 26.528 ;
     RECT  23.339 27.996 27.109 28.86 ;
     RECT  22.211 0.832 27.205 1.86 ;
     RECT  27.205 0.32 27.347 1.86 ;
     RECT  27.109 25.664 27.371 28.86 ;
     RECT  26.731 48.192 27.683 48.224 ;
     RECT  26.773 22.464 27.691 23.46 ;
     RECT  27.347 0.832 27.701 1.86 ;
     RECT  7.019 6.396 27.701 7.26 ;
     RECT  27.637 20.48 27.706 20.512 ;
     RECT  27.701 0.832 27.779 2.848 ;
     RECT  26.731 49.596 27.827 51.68 ;
     RECT  26.731 44.196 27.973 46.24 ;
     RECT  26.867 38.796 28.213 39.66 ;
     RECT  28.194 41.536 28.267 41.568 ;
     RECT  26.243 54.996 28.453 55.86 ;
     RECT  28.213 38.796 28.499 39.904 ;
     RECT  25.139 33.396 28.501 34.26 ;
     RECT  27.973 43.84 28.715 46.24 ;
     RECT  27.371 26.496 29.269 28.86 ;
     RECT  29.269 26.496 29.355 29.024 ;
     RECT  28.501 32.64 29.355 34.26 ;
     RECT  28.715 44.032 29.363 46.24 ;
     RECT  27.011 15.744 29.411 15.776 ;
     RECT  29.355 26.496 29.651 28.86 ;
     RECT  28.741 20.544 29.813 20.576 ;
     RECT  29.813 19.776 29.867 20.576 ;
     RECT  26.219 11.136 29.941 12.66 ;
     RECT  27.691 22.596 30.181 23.46 ;
     RECT  28.499 38.796 30.181 39.66 ;
     RECT  30.181 35.904 30.197 35.936 ;
     RECT  30.181 38.656 30.251 39.66 ;
     RECT  24.437 60.032 30.638 61.26 ;
     RECT  30.638 59.84 30.707 61.26 ;
     RECT  30.707 60.224 30.709 61.26 ;
     RECT  30.709 60.224 30.763 61.408 ;
     RECT  29.355 33.396 30.773 34.26 ;
     RECT  30.197 35.904 30.773 37.024 ;
     RECT  30.773 32.64 30.827 37.024 ;
     RECT  30.757 47.232 30.827 47.264 ;
     RECT  29.651 26.496 30.851 26.528 ;
     RECT  30.827 32.64 30.851 35.36 ;
     RECT  30.181 22.144 31.029 23.46 ;
     RECT  31.029 22.144 31.083 23.776 ;
     RECT  30.827 36.992 31.091 37.024 ;
     RECT  31.083 22.596 31.102 23.776 ;
     RECT  31.029 26.432 31.102 26.464 ;
     RECT  30.851 32.64 31.354 34.848 ;
     RECT  29.867 19.776 31.379 19.808 ;
     RECT  27.701 6.396 31.925 7.712 ;
     RECT  29.941 10.816 31.925 12.66 ;
     RECT  30.763 60.396 31.955 61.408 ;
     RECT  31.925 6.396 32.003 8.416 ;
     RECT  27.779 0.832 32.149 1.86 ;
     RECT  29.651 27.996 32.389 28.86 ;
     RECT  32.389 27.996 32.437 29.984 ;
     RECT  32.003 6.396 32.485 7.584 ;
     RECT  31.925 9.728 32.491 12.66 ;
     RECT  32.437 27.776 32.491 29.984 ;
     RECT  31.354 32.64 32.491 34.26 ;
     RECT  27.011 17.196 32.533 18.06 ;
     RECT  32.491 27.776 32.579 28.86 ;
     RECT  32.149 0.384 32.581 1.86 ;
     RECT  32.581 0.192 32.683 1.86 ;
     RECT  32.485 5.76 32.683 7.584 ;
     RECT  32.491 11.328 32.747 12.66 ;
     RECT  32.533 14.144 32.747 14.176 ;
     RECT  32.533 16.32 32.747 18.06 ;
     RECT  32.683 0.256 32.939 1.86 ;
     RECT  32.491 9.728 33.059 9.76 ;
     RECT  32.939 0.384 33.067 1.86 ;
     RECT  29.363 44.032 33.683 45.06 ;
     RECT  32.683 6.208 33.707 7.584 ;
     RECT  28.453 54.996 34.259 56.48 ;
     RECT  27.877 69.696 34.835 69.728 ;
     RECT  35.797 4.544 35.829 4.576 ;
     RECT  33.707 6.208 35.829 7.26 ;
     RECT  35.829 4.544 35.883 7.26 ;
     RECT  35.883 5.696 36.515 7.26 ;
     RECT  33.067 0.832 36.709 1.86 ;
     RECT  36.709 0.576 36.725 1.86 ;
     RECT  36.725 0.256 37.813 1.86 ;
     RECT  36.515 6.396 38.16 7.26 ;
     RECT  32.747 11.796 38.16 12.66 ;
     RECT  32.747 17.196 38.16 18.06 ;
     RECT  31.102 22.596 38.16 23.46 ;
     RECT  32.579 27.996 38.16 28.86 ;
     RECT  32.491 33.396 38.16 34.26 ;
     RECT  30.251 38.796 38.16 39.66 ;
     RECT  33.683 44.196 38.16 45.06 ;
     RECT  27.827 49.596 38.16 50.46 ;
     RECT  34.259 54.996 38.16 55.86 ;
     RECT  31.955 60.396 38.16 61.26 ;
     RECT  23.987 65.796 38.16 66.66 ;
     RECT  25.515 71.196 38.16 72.06 ;
     RECT  27.059 76.596 38.16 76.884 ;
     RECT  37.813 0.256 38.187 2.016 ;
     RECT  38.187 0.256 38.483 1.86 ;
     RECT  38.483 0.256 38.675 0.288 ;
     RECT  38.483 1.572 38.944 1.86 ;
     RECT  38.16 6.972 38.944 7.26 ;
     RECT  38.16 12.372 38.944 12.66 ;
     RECT  38.16 17.772 38.944 18.06 ;
     RECT  38.16 23.172 38.944 23.46 ;
     RECT  38.16 28.572 38.944 28.86 ;
     RECT  38.16 33.972 38.944 34.26 ;
     RECT  38.16 39.372 38.944 39.66 ;
     RECT  38.16 44.772 38.944 45.06 ;
     RECT  38.16 50.172 38.944 50.46 ;
     RECT  38.16 55.572 38.944 55.86 ;
     RECT  38.16 60.972 38.944 61.26 ;
     RECT  38.16 66.372 38.944 66.66 ;
     RECT  38.16 71.772 38.944 72.06 ;
    LAYER M7 ;
     RECT  32.64 0.181 32.672 0.245 ;
     RECT  32.64 0.245 32.928 0.373 ;
     RECT  20.288 0.245 20.32 0.427 ;
     RECT  16.768 0.245 16.8 0.491 ;
     RECT  32.512 0.373 33.056 0.531 ;
     RECT  38.144 0.245 38.176 0.531 ;
     RECT  36.736 0.245 36.768 0.619 ;
     RECT  32.512 0.531 33.544 0.811 ;
     RECT  38.144 0.531 38.944 2.027 ;
     RECT  27.856 0.531 28.144 2.805 ;
     RECT  35.84 4.533 35.872 5.739 ;
     RECT  32.64 0.811 33.544 5.803 ;
     RECT  33.256 5.803 33.544 6.197 ;
     RECT  6.256 0.531 6.544 6.773 ;
     RECT  11.656 0.531 11.944 6.773 ;
     RECT  6.256 6.773 6.88 7.413 ;
     RECT  31.488 6.773 31.52 7.541 ;
     RECT  33.256 6.197 33.696 7.595 ;
     RECT  27.712 2.805 28.144 7.723 ;
     RECT  31.488 7.541 31.968 7.723 ;
     RECT  25.792 5.045 25.824 8.619 ;
     RECT  6.256 7.413 7.008 9.451 ;
     RECT  31.936 7.723 31.968 9.717 ;
     RECT  33.256 7.595 33.544 9.717 ;
     RECT  11.2 6.773 11.944 9.771 ;
     RECT  31.936 9.717 33.544 9.771 ;
     RECT  11.52 9.771 11.944 10.539 ;
     RECT  32.448 9.771 33.544 11.371 ;
     RECT  20.416 1.397 20.448 11.509 ;
     RECT  26.176 11.125 26.208 11.637 ;
     RECT  11.656 10.539 11.944 13.621 ;
     RECT  17.056 0.531 17.344 13.685 ;
     RECT  26.112 11.637 26.208 14.261 ;
     RECT  27.856 7.723 28.144 14.261 ;
     RECT  26.112 14.261 28.144 14.315 ;
     RECT  10.944 13.621 11.944 14.955 ;
     RECT  6.256 9.451 6.88 15.093 ;
     RECT  11.328 14.955 11.944 15.147 ;
     RECT  20.416 11.509 20.512 15.659 ;
     RECT  32.704 11.371 33.544 16.363 ;
     RECT  26.176 14.315 28.144 16.747 ;
     RECT  26.176 16.747 26.208 18.933 ;
     RECT  27.856 16.747 28.144 18.933 ;
     RECT  22.456 0.531 22.744 19.061 ;
     RECT  26.176 18.933 28.144 19.115 ;
     RECT  16.768 13.685 17.344 19.179 ;
     RECT  22.456 19.061 23.136 19.637 ;
     RECT  26.56 19.115 28.144 20.587 ;
     RECT  29.824 17.589 29.856 20.587 ;
     RECT  6.256 15.093 7.392 21.739 ;
     RECT  22.208 19.637 23.136 21.739 ;
     RECT  11.656 15.147 11.944 22.965 ;
     RECT  27.648 20.587 28.144 23.019 ;
     RECT  13.376 18.741 13.408 23.029 ;
     RECT  14.976 15.093 15.008 23.029 ;
     RECT  17.056 19.179 17.344 23.029 ;
     RECT  20.416 15.659 20.448 23.029 ;
     RECT  13.376 23.029 15.008 23.595 ;
     RECT  14.656 23.595 15.008 24.235 ;
     RECT  18.88 0.821 18.912 24.373 ;
     RECT  20.416 23.029 20.512 24.373 ;
     RECT  18.88 24.373 20.512 24.427 ;
     RECT  16.896 23.029 17.344 24.619 ;
     RECT  27.856 23.019 28.144 25.653 ;
     RECT  11.392 22.965 11.944 25.707 ;
     RECT  14.656 24.235 14.88 25.963 ;
     RECT  31.04 22.133 31.072 26.475 ;
     RECT  22.456 21.739 23.136 26.485 ;
     RECT  27.328 25.653 28.144 26.677 ;
     RECT  22.456 26.485 23.328 26.731 ;
     RECT  22.456 26.731 23.2 26.795 ;
     RECT  27.328 26.677 29.344 27.435 ;
     RECT  33.256 16.363 33.544 27.765 ;
     RECT  17.056 24.619 17.344 27.829 ;
     RECT  6.256 21.739 6.544 28.405 ;
     RECT  4.8 26.677 4.832 28.459 ;
     RECT  6.256 28.405 7.008 29.099 ;
     RECT  16.832 27.829 17.344 29.557 ;
     RECT  11.656 25.707 11.944 30.709 ;
     RECT  16.768 29.557 17.344 31.083 ;
     RECT  14.848 25.963 14.88 31.285 ;
     RECT  14.848 31.285 15.136 31.339 ;
     RECT  17.056 31.083 17.344 32.437 ;
     RECT  11.656 30.709 12.96 32.555 ;
     RECT  27.856 27.435 29.344 32.683 ;
     RECT  32.448 27.765 33.544 32.683 ;
     RECT  30.784 32.629 30.816 33.845 ;
     RECT  16.896 32.437 17.344 33.899 ;
     RECT  30.784 33.845 31.328 33.899 ;
     RECT  31.296 33.899 31.328 34.859 ;
     RECT  15.104 31.339 15.136 35.371 ;
     RECT  22.456 26.795 23.072 35.947 ;
     RECT  30.784 35.317 30.816 35.947 ;
     RECT  11.656 32.555 11.944 37.301 ;
     RECT  18.88 24.427 20.448 37.675 ;
     RECT  22.456 35.947 22.744 38.645 ;
     RECT  30.208 36.981 30.24 38.699 ;
     RECT  22.456 38.645 23.968 39.211 ;
     RECT  19.904 37.675 20.448 39.787 ;
     RECT  7.936 37.557 7.968 39.861 ;
     RECT  27.856 32.683 28.144 39.861 ;
     RECT  7.936 39.861 8.928 41.067 ;
     RECT  26.176 36.661 26.208 41.067 ;
     RECT  24.704 41.013 24.736 41.269 ;
     RECT  11.656 37.301 12.768 41.835 ;
     RECT  19.904 39.787 20 42.155 ;
     RECT  8.896 41.067 8.928 42.731 ;
     RECT  17.056 33.899 17.344 43.125 ;
     RECT  11.656 41.835 11.944 43.253 ;
     RECT  6.256 29.099 6.544 43.765 ;
     RECT  27.856 39.861 28.256 43.829 ;
     RECT  11.656 43.253 13.152 44.021 ;
     RECT  11.656 44.021 14.368 44.075 ;
     RECT  11.656 44.075 12.512 44.597 ;
     RECT  24.576 41.269 24.736 44.651 ;
     RECT  19.968 42.155 20 45.557 ;
     RECT  22.456 39.211 22.744 45.877 ;
     RECT  24.704 44.651 24.736 45.931 ;
     RECT  27.856 43.829 28.704 46.251 ;
     RECT  19.712 45.557 20 46.709 ;
     RECT  21.44 45.877 22.744 46.709 ;
     RECT  6.256 43.765 7.712 46.827 ;
     RECT  10.496 44.597 12.512 46.827 ;
     RECT  10.496 46.827 11.944 47.019 ;
     RECT  27.856 46.251 28.144 47.221 ;
     RECT  26.688 47.221 28.144 48.181 ;
     RECT  6.256 46.827 7.456 49.387 ;
     RECT  9.984 49.205 10.016 49.461 ;
     RECT  11.656 47.019 11.944 49.973 ;
     RECT  19.712 46.709 22.744 50.795 ;
     RECT  6.256 49.387 6.544 50.869 ;
     RECT  17.056 43.125 18.144 51.509 ;
     RECT  19.712 50.795 20 51.509 ;
     RECT  21.44 50.795 22.744 51.947 ;
     RECT  17.056 51.509 20 52.203 ;
     RECT  9.792 49.461 10.016 52.341 ;
     RECT  11.656 49.973 12.768 53.045 ;
     RECT  14.336 44.075 14.368 53.045 ;
     RECT  21.632 51.947 22.744 53.493 ;
     RECT  9.088 52.341 10.016 53.557 ;
     RECT  21.568 53.493 22.744 53.749 ;
     RECT  8.576 53.557 10.016 54.763 ;
     RECT  9.792 54.763 10.016 54.837 ;
     RECT  11.656 53.045 14.368 54.837 ;
     RECT  21.568 53.749 23.904 55.467 ;
     RECT  30.784 47.221 30.816 56.437 ;
     RECT  30.656 56.437 30.816 56.491 ;
     RECT  6.256 50.869 6.752 56.693 ;
     RECT  17.056 52.203 19.744 56.885 ;
     RECT  9.792 54.837 14.368 57.461 ;
     RECT  9.792 57.461 14.56 57.781 ;
     RECT  4.416 49.461 4.448 57.973 ;
     RECT  9.792 57.781 15.072 58.091 ;
     RECT  3.904 57.973 4.448 58.101 ;
     RECT  9.792 58.091 10.272 58.677 ;
     RECT  3.84 58.101 4.448 58.859 ;
     RECT  17.056 56.885 19.936 58.859 ;
     RECT  9.408 58.677 10.272 59.061 ;
     RECT  30.656 56.491 30.688 59.883 ;
     RECT  24.448 60.021 24.48 60.213 ;
     RECT  26.56 48.181 28.144 60.213 ;
     RECT  11.656 58.091 15.072 60.267 ;
     RECT  17.056 58.859 19.744 60.277 ;
     RECT  6.256 56.693 7.712 60.789 ;
     RECT  9.216 59.061 10.272 60.789 ;
     RECT  21.568 55.467 22.744 60.789 ;
     RECT  24.448 60.213 28.144 60.789 ;
     RECT  11.656 60.267 14.56 60.843 ;
     RECT  21.568 60.789 28.144 60.843 ;
     RECT  3.904 58.859 4.448 61.611 ;
     RECT  6.256 60.789 10.272 62.197 ;
     RECT  11.656 60.843 14.048 62.197 ;
     RECT  17.056 60.277 19.872 62.645 ;
     RECT  21.568 60.843 23.968 62.645 ;
     RECT  17.056 62.645 23.968 63.093 ;
     RECT  25.6 60.843 28.144 63.147 ;
     RECT  4.416 61.611 4.448 63.797 ;
     RECT  17.056 63.093 24.288 64.043 ;
     RECT  17.056 64.043 23.968 65.579 ;
     RECT  4.224 63.797 4.448 65.643 ;
     RECT  6.256 62.197 14.048 65.643 ;
     RECT  17.056 65.579 22.744 66.165 ;
     RECT  9.024 65.643 14.048 67.883 ;
     RECT  15.936 66.165 22.744 68.277 ;
     RECT  4.416 65.643 4.448 68.661 ;
     RECT  6.256 65.643 6.752 68.661 ;
     RECT  15.488 68.277 22.744 69.035 ;
     RECT  30.72 60.213 30.752 69.739 ;
     RECT  4.416 68.661 6.752 70.965 ;
     RECT  4.352 70.965 6.752 71.605 ;
     RECT  9.216 67.883 14.048 71.605 ;
     RECT  15.808 69.035 22.744 71.605 ;
     RECT  2.432 59.765 2.464 72.821 ;
     RECT  2.432 72.821 3.04 72.885 ;
     RECT  4.352 71.605 22.744 72.885 ;
     RECT  25.152 72.309 25.184 72.885 ;
     RECT  26.56 63.147 28.144 72.885 ;
     RECT  25.152 72.885 28.144 73.579 ;
     RECT  0.856 0.531 1.144 74.037 ;
     RECT  2.432 72.885 23.84 74.037 ;
     RECT  0.856 74.037 23.84 74.997 ;
     RECT  25.472 73.579 25.504 74.997 ;
     RECT  0.856 74.997 25.504 75.573 ;
     RECT  0.856 75.573 25.632 76.459 ;
     RECT  8.512 76.459 25.056 76.523 ;
     RECT  0.856 76.459 2.016 76.959 ;
     RECT  8.512 76.523 22.744 76.959 ;
     RECT  27.856 73.579 28.144 76.959 ;
     RECT  33.256 32.683 33.544 76.959 ;
     RECT  38.656 2.027 38.944 76.959 ;
     RECT  4.352 76.459 7.2 77.035 ;
     RECT  8.512 76.959 21.728 77.035 ;
     RECT  6.08 77.035 6.24 77.099 ;
     RECT  8.512 77.035 16.928 77.099 ;
     RECT  25.024 76.523 25.056 77.099 ;
     RECT  1.984 76.959 2.016 77.163 ;
     RECT  9.664 77.099 16.928 77.163 ;
     RECT  20.544 77.035 21.728 77.163 ;
     RECT  13.952 77.163 16.928 77.227 ;
     RECT  9.856 77.163 12.128 77.291 ;
     RECT  14.72 77.227 16.288 77.291 ;
     RECT  20.928 77.163 21.728 77.291 ;
     RECT  21.696 77.291 21.728 77.355 ;
     RECT  6.208 77.099 6.24 77.419 ;
     RECT  11.52 77.291 12.128 77.419 ;
     RECT  11.52 77.419 11.552 77.483 ;
  END
END hfd_stn_r33
END LIBRARY
